// Mitsubishi GX Works2 project: PJT07_16_PLC(20220517_01)   PLC: Q03UDV

FUNCTION_BLOCK Alarm_FB
VAR_INPUT
  IB_Alarm : BOOL;  (* 入力@警報発生(0:-/1:発生) *)
END_VAR
VAR
  VT_AlarmDelayTimer : TIMER;  (* 内部@異常入力ﾃﾞｨﾚｲﾀｲﾏ *)
END_VAR
VAR_INPUT
  IW_DelayTimerVal : INT;  (* 入力@ﾃﾞｨﾚｲﾀｲﾏ値 *)
END_VAR
VAR_OUTPUT
  OB_AlarmHolding : BOOL;  (* 出力@ｱﾗｰﾑ自己保持(0:-/1:保持) *)
END_VAR
VAR_INPUT
  IB_AlarmResetPB : BOOL;  (* 入力@警報ﾘｾｯﾄPB(0:-/1:ﾘｾｯﾄ) *)
END_VAR
VAR
  VT_BuzzerStopTimer : TIMER;  (* 内部@ﾌﾞｻﾞｰｽﾄｯﾌﾟﾀｲﾏ *)
END_VAR
VAR_INPUT
  IW_BzStopTVal : INT;  (* 入力@ﾌﾞｻﾞｰｽﾄｯﾌﾟﾀｲﾏ値 *)
END_VAR
VAR
  VB_BuzzerStopFLG : BOOL;  (* 内部@ﾌﾞｻﾞｰｽﾄｯﾌﾟﾃﾞﾊﾞｲｽ(0:-/1:停止) *)
END_VAR
VAR_OUTPUT
  OB_DisplayFLG : BOOL;  (* 出力@ｱﾗｰﾑ表示ﾃﾞﾊﾞｲｽ(0:点滅/1:点灯) *)
END_VAR
VAR_INPUT
  IB_BuzzerStopPB : BOOL;  (* 入力@ﾌﾞｻﾞｰｽﾄｯﾌﾟPB(0:-/1:ｽﾄｯﾌﾟ) *)
END_VAR
VAR_OUTPUT
  OB_BuzzerFLG : BOOL;  (* 出力@ﾌﾞｻﾞｰﾌﾗｸﾞ *)
END_VAR
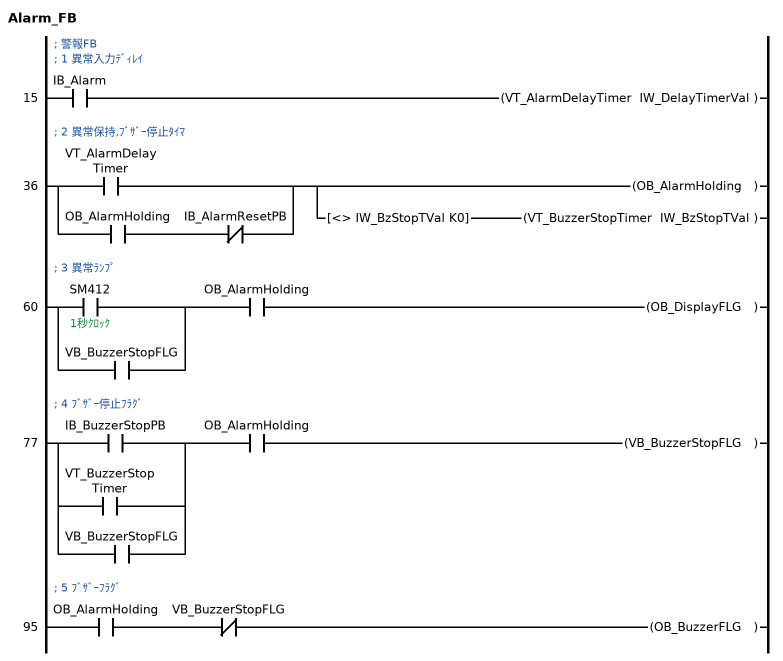
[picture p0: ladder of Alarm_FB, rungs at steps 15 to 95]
; 警報FB
; 1 異常入力ﾃﾞｨﾚｲ
15    LD      IB_Alarm
      OUT     VT_AlarmDelayTimer IW_DelayTimerVal
; 2 異常保持,ﾌﾞｻﾞｰ停止ﾀｲﾏ
36    LD      VT_AlarmDelayTimer
      LD      OB_AlarmHolding
      ANI     IB_AlarmResetPB
      ORB
      OUT     OB_AlarmHolding
      AND<>   IW_BzStopTVal K0
      OUT     VT_BuzzerStopTimer IW_BzStopTVal
; 3 異常ﾗﾝﾌﾟ
60    LD      SM412  ; 1秒ｸﾛｯｸ
      OR      VB_BuzzerStopFLG
      AND     OB_AlarmHolding
      OUT     OB_DisplayFLG
; 4 ﾌﾞｻﾞｰ停止ﾌﾗｸﾞ
77    LD      IB_BuzzerStopPB
      OR      VT_BuzzerStopTimer
      OR      VB_BuzzerStopFLG
      AND     OB_AlarmHolding
      OUT     VB_BuzzerStopFLG
; 5 ﾌﾞｻﾞｰﾌﾗｸﾞ
95    LD      OB_AlarmHolding
      ANI     VB_BuzzerStopFLG
      OUT     OB_BuzzerFLG
END_FUNCTION_BLOCK

PROGRAM 11_Alarm
VAR
  Alarm_FB_1 : Alarm_FB;
  Alarm_FB_2 : Alarm_FB;
END_VAR
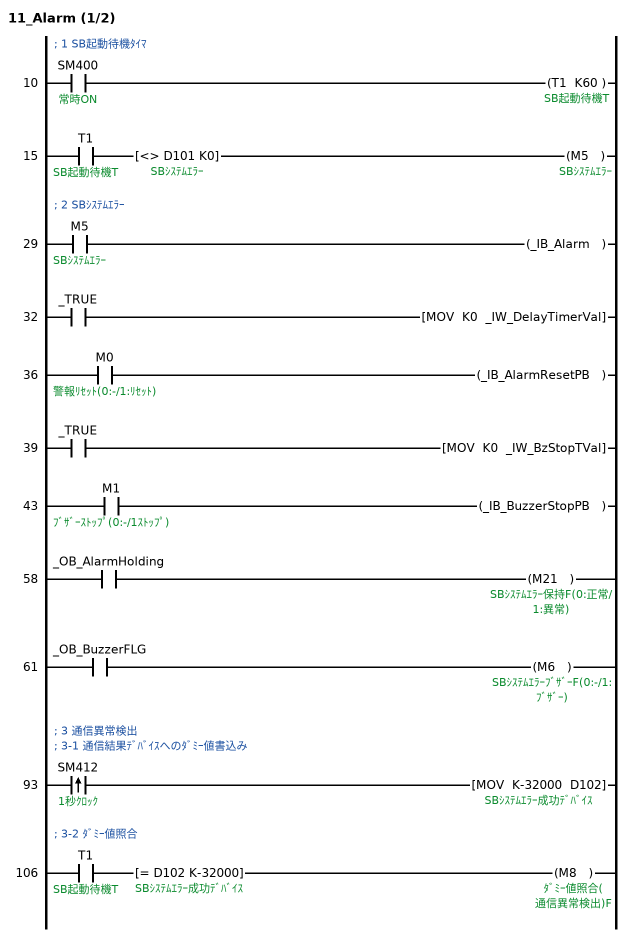
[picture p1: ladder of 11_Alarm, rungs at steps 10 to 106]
; 1 SB起動待機ﾀｲﾏ
10    LD      SM400  ; 常時ON
      OUT     T1 K60  ; SB起動待機T
15    LD      T1  ; SB起動待機T
      AND<>   D101 K0  ; SBｼｽﾃﾑｴﾗｰ
      OUT     M5  ; SBｼｽﾃﾑｴﾗｰ
; FB BLK START Alarm_FB(Alarm_FB_1)
; 2 SBｼｽﾃﾑｴﾗｰ
29    LD      M5  ; SBｼｽﾃﾑｴﾗｰ
      OUT     _IB_Alarm
32    LD      _TRUE
      MOV     K0 _IW_DelayTimerVal
36    LD      M0  ; 警報ﾘｾｯﾄ(0:-/1:ﾘｾｯﾄ)
      OUT     _IB_AlarmResetPB
39    LD      _TRUE
      MOV     K0 _IW_BzStopTVal
43    LD      M1  ; ﾌﾞｻﾞｰｽﾄｯﾌﾟ(0:-/1ｽﾄｯﾌﾟ)
      OUT     _IB_BuzzerStopPB
; FB START
; FB_NAME Alarm_FB
; INSTANCE_NAME Alarm_FB_1
; FB IN_B:IB_Alarm
; FB OUT_OB_AlarmHolding:B
; FB IN_W:IW_DelayTimerVal
; FB OUT_OB_DisplayFLG:B
; FB IN_B:IB_AlarmResetPB
; FB OUT_OB_BuzzerFLG:B
; FB IN_W:IW_BzStopTVal
; FB IN_B:IB_BuzzerStopPB
; FB END
58    LD      _OB_AlarmHolding
      OUT     M21  ; SBｼｽﾃﾑｴﾗｰ保持F(0:正常/1:異常)
61    LD      _OB_BuzzerFLG
      OUT     M6  ; SBｼｽﾃﾑｴﾗｰﾌﾞｻﾞｰF(0:-/1:ﾌﾞｻﾞｰ)
; FB BLK END
; 3 通信異常検出
; 3-1 通信結果ﾃﾞﾊﾞｲｽへのﾀﾞﾐｰ値書込み
93    LDP     SM412  ; 1秒ｸﾛｯｸ
      MOV     K-32000 D102  ; SBｼｽﾃﾑｴﾗｰ成功ﾃﾞﾊﾞｲｽ
; 3-2 ﾀﾞﾐｰ値照合
106   LD      T1  ; SB起動待機T
      AND=    D102 K-32000  ; SBｼｽﾃﾑｴﾗｰ成功ﾃﾞﾊﾞｲｽ
      OUT     M8  ; ﾀﾞﾐｰ値照合(通信異常検出)F
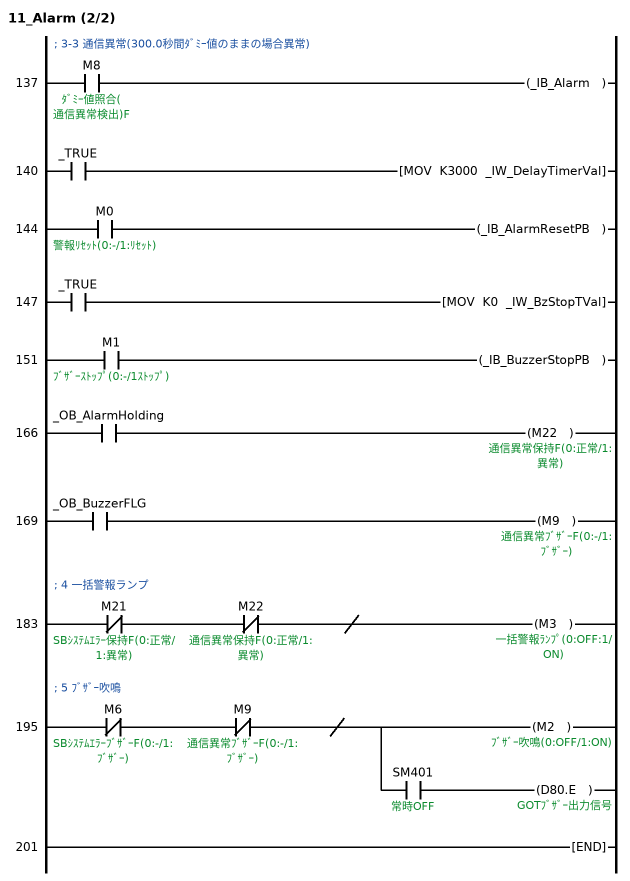
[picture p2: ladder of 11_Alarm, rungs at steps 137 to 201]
; FB BLK START Alarm_FB(Alarm_FB_2)
; 3-3 通信異常(300.0秒間ﾀﾞﾐｰ値のままの場合異常)
137   LD      M8  ; ﾀﾞﾐｰ値照合(通信異常検出)F
      OUT     _IB_Alarm
140   LD      _TRUE
      MOV     K3000 _IW_DelayTimerVal
144   LD      M0  ; 警報ﾘｾｯﾄ(0:-/1:ﾘｾｯﾄ)
      OUT     _IB_AlarmResetPB
147   LD      _TRUE
      MOV     K0 _IW_BzStopTVal
151   LD      M1  ; ﾌﾞｻﾞｰｽﾄｯﾌﾟ(0:-/1ｽﾄｯﾌﾟ)
      OUT     _IB_BuzzerStopPB
; FB START
; FB_NAME Alarm_FB
; INSTANCE_NAME Alarm_FB_2
; FB IN_B:IB_Alarm
; FB OUT_OB_AlarmHolding:B
; FB IN_W:IW_DelayTimerVal
; FB OUT_OB_DisplayFLG:B
; FB IN_B:IB_AlarmResetPB
; FB OUT_OB_BuzzerFLG:B
; FB IN_W:IW_BzStopTVal
; FB IN_B:IB_BuzzerStopPB
; FB END
166   LD      _OB_AlarmHolding
      OUT     M22  ; 通信異常保持F(0:正常/1:異常)
169   LD      _OB_BuzzerFLG
      OUT     M9  ; 通信異常ﾌﾞｻﾞｰF(0:-/1:ﾌﾞｻﾞｰ)
; FB BLK END
; 4 一括警報ランプ
183   LDI     M21  ; SBｼｽﾃﾑｴﾗｰ保持F(0:正常/1:異常)
      ANI     M22  ; 通信異常保持F(0:正常/1:異常)
      INV
      OUT     M3  ; 一括警報ﾗﾝﾌﾟ(0:OFF:1/ON)
; 5 ﾌﾞｻﾞｰ吹鳴
195   LDI     M6  ; SBｼｽﾃﾑｴﾗｰﾌﾞｻﾞｰF(0:-/1:ﾌﾞｻﾞｰ)
      ANI     M9  ; 通信異常ﾌﾞｻﾞｰF(0:-/1:ﾌﾞｻﾞｰ)
      INV
      OUT     M2  ; ﾌﾞｻﾞｰ吹鳴(0:OFF/1:ON)
      AND     SM401  ; 常時OFF
      OUT     D80.E  ; GOTﾌﾞｻﾞｰ出力信号
201   END
END_PROGRAM

PROGRAM 02_#2  // SB_Initial
VAR
  __IST_553ac48fffaf4984 : I+ST_553ac48fffaf4984;
END_VAR
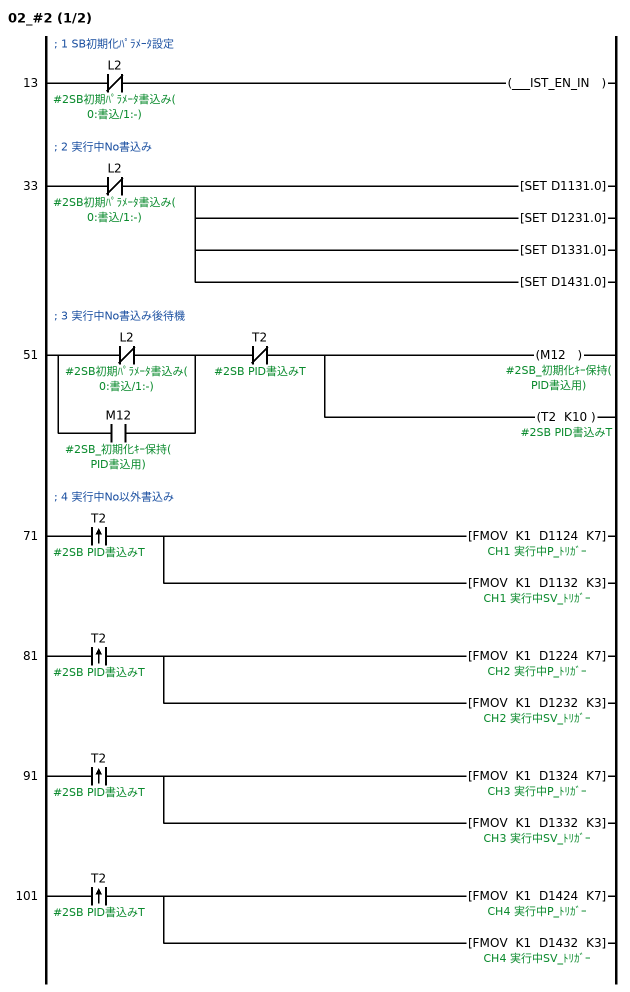
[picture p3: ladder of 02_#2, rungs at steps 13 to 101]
; FB BLK START I+ST_553ac48fffaf4984(__IST_553ac48fffaf4984)
; 1 SB初期化ﾊﾟﾗﾒｰﾀ設定
13    LDI     L2  ; #2SB初期ﾊﾟﾗﾒｰﾀ書込み(0:書込/1:-)
      OUT     ___IST_EN_IN
; FB START
; FB_NAME I+ST_553ac48fffaf4984
; INSTANCE_NAME __IST_553ac48fffaf4984
; FB IN_B:__IST_EN_IN
; FB OUT___IST_EN_OUT:B
; FB END
; FB BLK END
; 2 実行中No書込み
33    LDI     L2  ; #2SB初期ﾊﾟﾗﾒｰﾀ書込み(0:書込/1:-)
      SET     D1131.0
      SET     D1231.0
      SET     D1331.0
      SET     D1431.0
; 3 実行中No書込み後待機
51    LDI     L2  ; #2SB初期ﾊﾟﾗﾒｰﾀ書込み(0:書込/1:-)
      OR      M12  ; #2SB_初期化ｷｰ保持(PID書込用)
      ANI     T2  ; #2SB PID書込みT
      OUT     M12  ; #2SB_初期化ｷｰ保持(PID書込用)
      OUT     T2 K10  ; #2SB PID書込みT
; 4 実行中No以外書込み
71    LDP     T2  ; #2SB PID書込みT
      FMOV    K1 D1124 K7  ; CH1 実行中P_ﾄﾘｶﾞｰ
      FMOV    K1 D1132 K3  ; CH1 実行中SV_ﾄﾘｶﾞｰ
81    LDP     T2  ; #2SB PID書込みT
      FMOV    K1 D1224 K7  ; CH2 実行中P_ﾄﾘｶﾞｰ
      FMOV    K1 D1232 K3  ; CH2 実行中SV_ﾄﾘｶﾞｰ
91    LDP     T2  ; #2SB PID書込みT
      FMOV    K1 D1324 K7  ; CH3 実行中P_ﾄﾘｶﾞｰ
      FMOV    K1 D1332 K3  ; CH3 実行中SV_ﾄﾘｶﾞｰ
101   LDP     T2  ; #2SB PID書込みT
      FMOV    K1 D1424 K7  ; CH4 実行中P_ﾄﾘｶﾞｰ
      FMOV    K1 D1432 K3  ; CH4 実行中SV_ﾄﾘｶﾞｰ
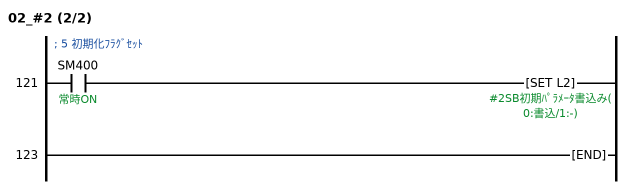
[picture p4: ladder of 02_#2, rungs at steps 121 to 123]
; 5 初期化ﾌﾗｸﾞｾｯﾄ
121   LD      SM400  ; 常時ON
      SET     L2  ; #2SB初期ﾊﾟﾗﾒｰﾀ書込み(0:書込/1:-)
123   END
END_PROGRAM

PROGRAM 22_#2  // SB100
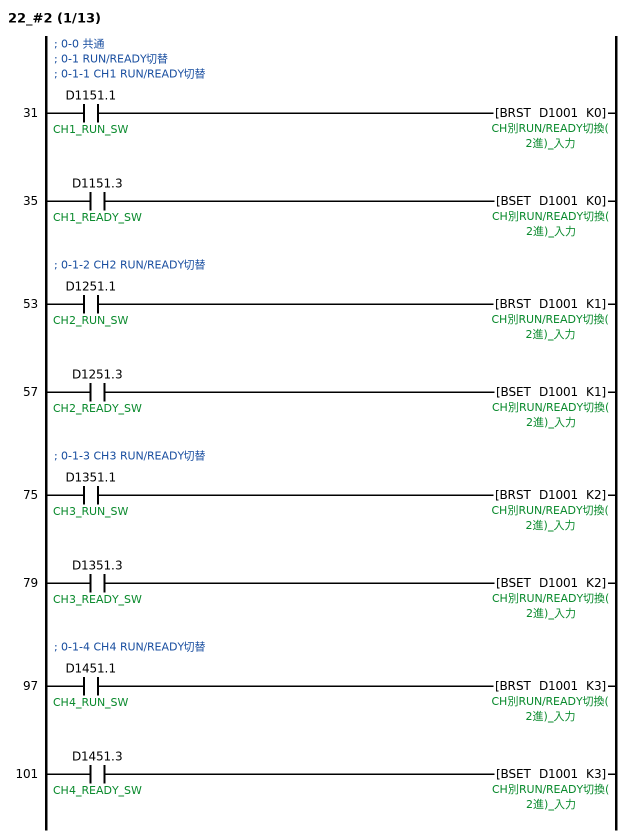
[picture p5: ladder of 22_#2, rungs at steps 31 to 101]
; 0-0 共通
; 0-1 RUN/READY切替
; 0-1-1 CH1 RUN/READY切替
31    LD      D1151.1  ; CH1_RUN_SW
      BRST    D1001 K0  ; CH別RUN/READY切換(2進)_入力
35    LD      D1151.3  ; CH1_READY_SW
      BSET    D1001 K0
; 0-1-2 CH2 RUN/READY切替
53    LD      D1251.1  ; CH2_RUN_SW
      BRST    D1001 K1
57    LD      D1251.3  ; CH2_READY_SW
      BSET    D1001 K1
; 0-1-3 CH3 RUN/READY切替
75    LD      D1351.1  ; CH3_RUN_SW
      BRST    D1001 K2
79    LD      D1351.3  ; CH3_READY_SW
      BSET    D1001 K2
; 0-1-4 CH4 RUN/READY切替
97    LD      D1451.1  ; CH4_RUN_SW
      BRST    D1001 K3
101   LD      D1451.3  ; CH4_READY_SW
      BSET    D1001 K3
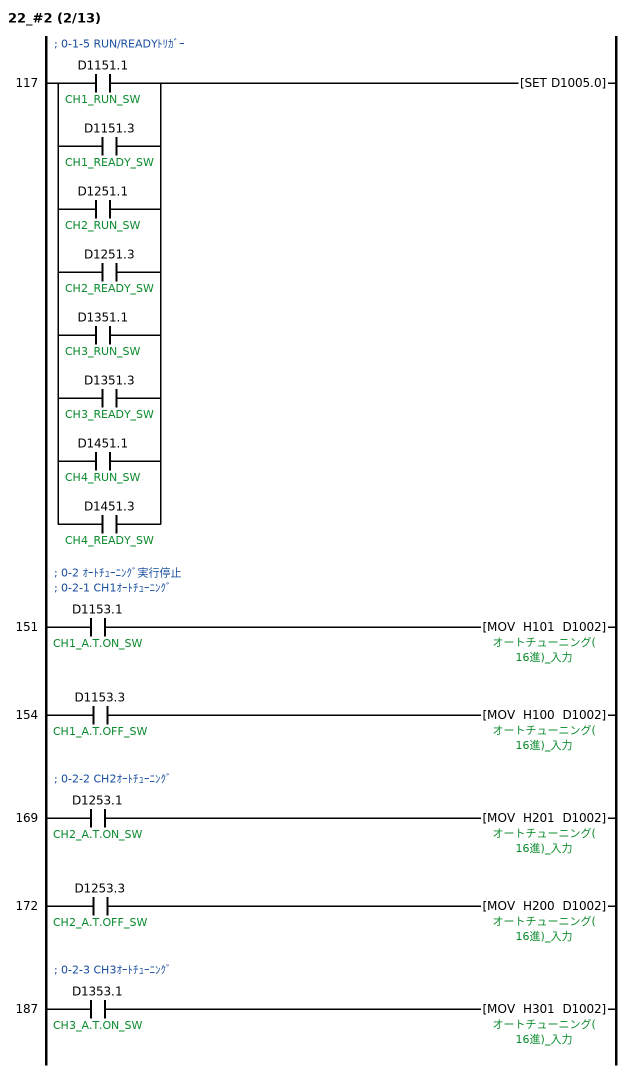
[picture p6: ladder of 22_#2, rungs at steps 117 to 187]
; 0-1-5 RUN/READYﾄﾘｶﾞｰ
117   LD      D1151.1  ; CH1_RUN_SW
      OR      D1151.3  ; CH1_READY_SW
      OR      D1251.1  ; CH2_RUN_SW
      OR      D1251.3  ; CH2_READY_SW
      OR      D1351.1  ; CH3_RUN_SW
      OR      D1351.3  ; CH3_READY_SW
      OR      D1451.1  ; CH4_RUN_SW
      OR      D1451.3  ; CH4_READY_SW
      SET     D1005.0
; 0-2 ｵｰﾄﾁｭｰﾆﾝｸﾞ実行停止
; 0-2-1 CH1ｵｰﾄﾁｭｰﾆﾝｸﾞ
151   LD      D1153.1  ; CH1_A.T.ON_SW
      MOV     H101 D1002  ; オートチューニング(16進)_入力
154   LD      D1153.3  ; CH1_A.T.OFF_SW
      MOV     H100 D1002
; 0-2-2 CH2ｵｰﾄﾁｭｰﾆﾝｸﾞ
169   LD      D1253.1  ; CH2_A.T.ON_SW
      MOV     H201 D1002
172   LD      D1253.3  ; CH2_A.T.OFF_SW
      MOV     H200 D1002
; 0-2-3 CH3ｵｰﾄﾁｭｰﾆﾝｸﾞ
187   LD      D1353.1  ; CH3_A.T.ON_SW
      MOV     H301 D1002
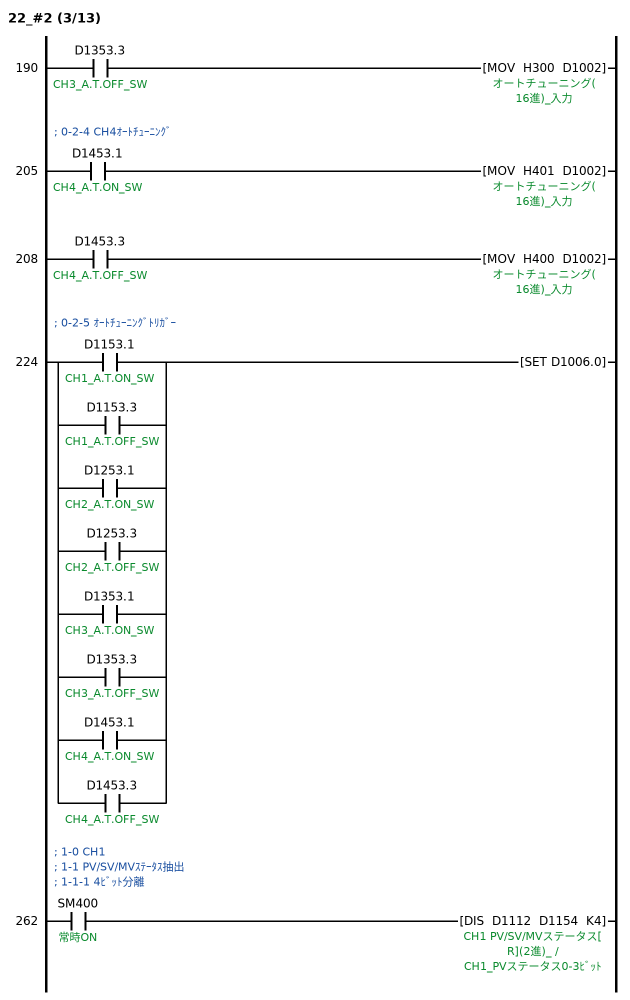
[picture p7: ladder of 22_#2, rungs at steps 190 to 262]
190   LD      D1353.3  ; CH3_A.T.OFF_SW
      MOV     H300 D1002
; 0-2-4 CH4ｵｰﾄﾁｭｰﾆﾝｸﾞ
205   LD      D1453.1  ; CH4_A.T.ON_SW
      MOV     H401 D1002
208   LD      D1453.3  ; CH4_A.T.OFF_SW
      MOV     H400 D1002
; 0-2-5 ｵｰﾄﾁｭｰﾆﾝｸﾞﾄﾘｶﾞｰ
224   LD      D1153.1  ; CH1_A.T.ON_SW
      OR      D1153.3  ; CH1_A.T.OFF_SW
      OR      D1253.1  ; CH2_A.T.ON_SW
      OR      D1253.3  ; CH2_A.T.OFF_SW
      OR      D1353.1  ; CH3_A.T.ON_SW
      OR      D1353.3  ; CH3_A.T.OFF_SW
      OR      D1453.1  ; CH4_A.T.ON_SW
      OR      D1453.3  ; CH4_A.T.OFF_SW
      SET     D1006.0
; 1-0 CH1
; 1-1 PV/SV/MVｽﾃｰﾀｽ抽出
; 1-1-1 4ﾋﾞｯﾄ分離
262   LD      SM400  ; 常時ON
      DIS     D1112 D1154 K4  ; CH1 PV/SV/MVステータス[R](2進)_ / CH1_PVステータス0-3ﾋﾞｯﾄ
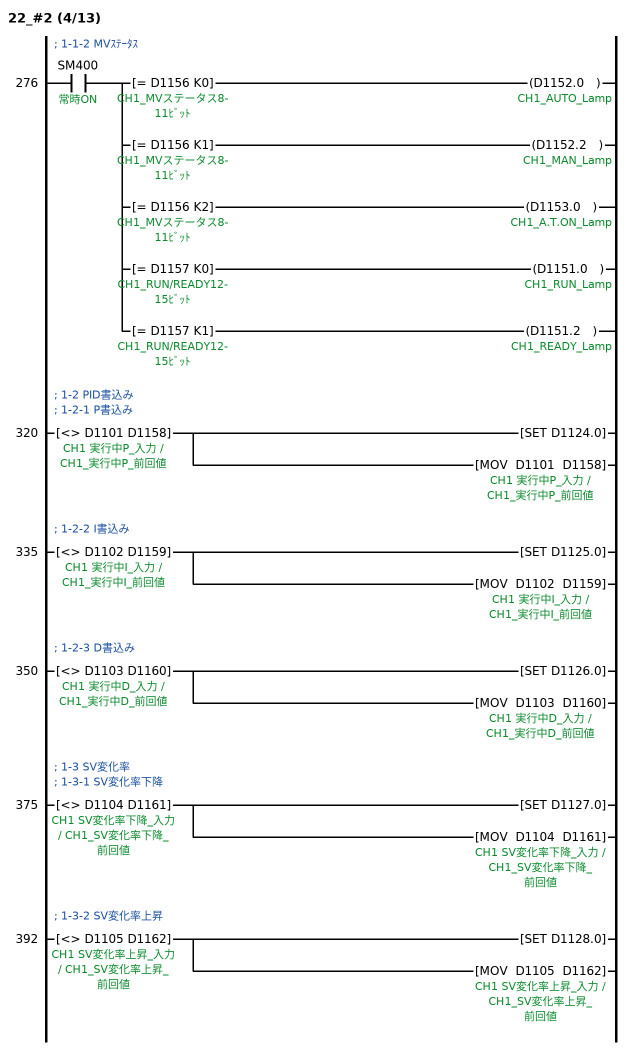
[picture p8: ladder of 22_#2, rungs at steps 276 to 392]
; 1-1-2 MVｽﾃｰﾀｽ
276   LD      SM400  ; 常時ON
      MPS
      AND=    D1156 K0  ; CH1_MVステータス8-11ﾋﾞｯﾄ
      OUT     D1152.0  ; CH1_AUTO_Lamp
      MRD
      AND=    D1156 K1  ; CH1_MVステータス8-11ﾋﾞｯﾄ
      OUT     D1152.2  ; CH1_MAN_Lamp
      MRD
      AND=    D1156 K2  ; CH1_MVステータス8-11ﾋﾞｯﾄ
      OUT     D1153.0  ; CH1_A.T.ON_Lamp
      MRD
      AND=    D1157 K0  ; CH1_RUN/READY12-15ﾋﾞｯﾄ
      OUT     D1151.0  ; CH1_RUN_Lamp
      MPP
      AND=    D1157 K1  ; CH1_RUN/READY12-15ﾋﾞｯﾄ
      OUT     D1151.2  ; CH1_READY_Lamp
; 1-2 PID書込み
; 1-2-1 P書込み
320   LD<>    D1101 D1158  ; CH1 実行中P_入力 / CH1_実行中P_前回値
      SET     D1124.0
      MOV     D1101 D1158
; 1-2-2 I書込み
335   LD<>    D1102 D1159  ; CH1 実行中I_入力 / CH1_実行中I_前回値
      SET     D1125.0
      MOV     D1102 D1159
; 1-2-3 D書込み
350   LD<>    D1103 D1160  ; CH1 実行中D_入力 / CH1_実行中D_前回値
      SET     D1126.0
      MOV     D1103 D1160
; 1-3 SV変化率
; 1-3-1 SV変化率下降
375   LD<>    D1104 D1161  ; CH1 SV変化率下降_入力 / CH1_SV変化率下降_前回値
      SET     D1127.0
      MOV     D1104 D1161
; 1-3-2 SV変化率上昇
392   LD<>    D1105 D1162  ; CH1 SV変化率上昇_入力 / CH1_SV変化率上昇_前回値
      SET     D1128.0
      MOV     D1105 D1162
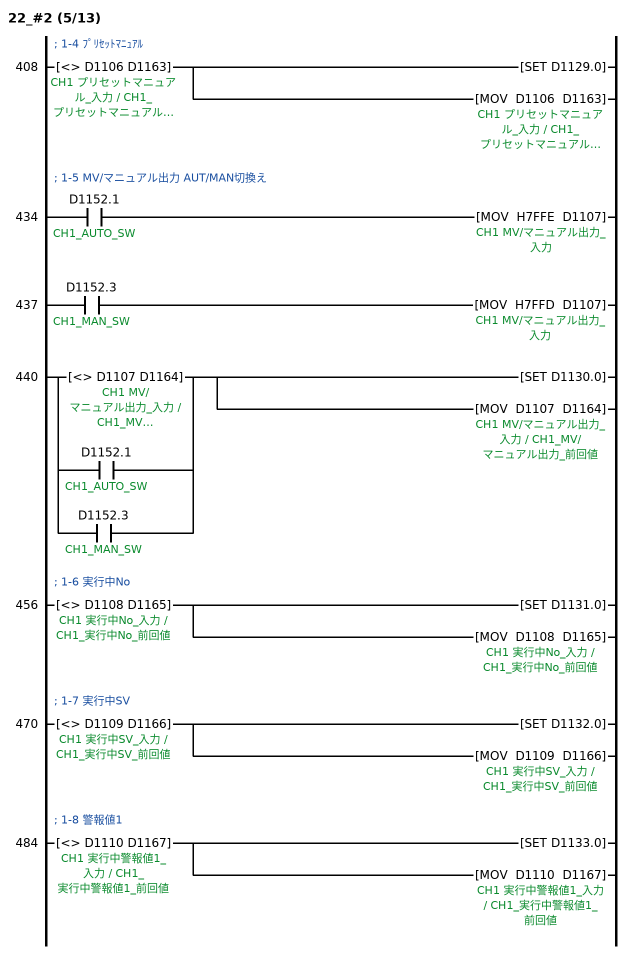
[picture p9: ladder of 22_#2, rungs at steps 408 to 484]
; 1-4 ﾌﾟﾘｾｯﾄﾏﾆｭｱﾙ
408   LD<>    D1106 D1163  ; CH1 プリセットマニュアル_入力 / CH1_プリセットマニュアル_前回値
      SET     D1129.0
      MOV     D1106 D1163
; 1-5 MV/マニュアル出力 AUT/MAN切換え
434   LD      D1152.1  ; CH1_AUTO_SW
      MOV     H7FFE D1107  ; CH1 MV/マニュアル出力_入力
437   LD      D1152.3  ; CH1_MAN_SW
      MOV     H7FFD D1107
440   LD<>    D1107 D1164  ; CH1 MV/マニュアル出力_入力 / CH1_MV/マニュアル出力_前回値
      OR      D1152.1  ; CH1_AUTO_SW
      OR      D1152.3  ; CH1_MAN_SW
      SET     D1130.0
      MOV     D1107 D1164
; 1-6 実行中No
456   LD<>    D1108 D1165  ; CH1 実行中No_入力 / CH1_実行中No_前回値
      SET     D1131.0
      MOV     D1108 D1165
; 1-7 実行中SV
470   LD<>    D1109 D1166  ; CH1 実行中SV_入力 / CH1_実行中SV_前回値
      SET     D1132.0
      MOV     D1109 D1166
; 1-8 警報値1
484   LD<>    D1110 D1167  ; CH1 実行中警報値1_入力 / CH1_実行中警報値1_前回値
      SET     D1133.0
      MOV     D1110 D1167
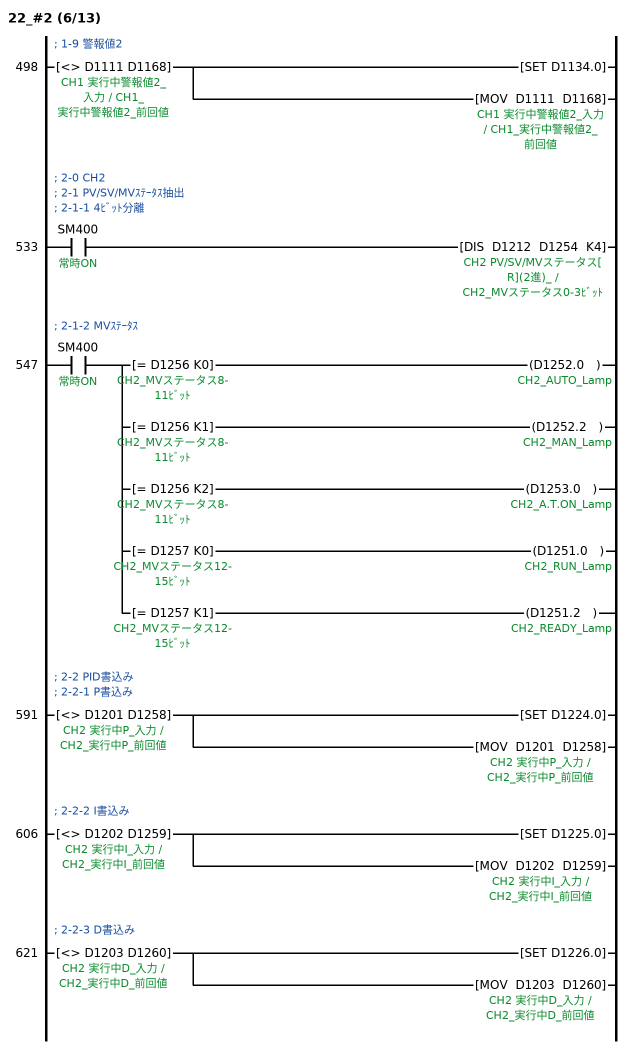
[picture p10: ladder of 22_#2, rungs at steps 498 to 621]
; 1-9 警報値2
498   LD<>    D1111 D1168  ; CH1 実行中警報値2_入力 / CH1_実行中警報値2_前回値
      SET     D1134.0
      MOV     D1111 D1168
; 2-0 CH2
; 2-1 PV/SV/MVｽﾃｰﾀｽ抽出
; 2-1-1 4ﾋﾞｯﾄ分離
533   LD      SM400  ; 常時ON
      DIS     D1212 D1254 K4  ; CH2 PV/SV/MVステータス[R](2進)_ / CH2_MVステータス0-3ﾋﾞｯﾄ
; 2-1-2 MVｽﾃｰﾀｽ
547   LD      SM400  ; 常時ON
      MPS
      AND=    D1256 K0  ; CH2_MVステータス8-11ﾋﾞｯﾄ
      OUT     D1252.0  ; CH2_AUTO_Lamp
      MRD
      AND=    D1256 K1  ; CH2_MVステータス8-11ﾋﾞｯﾄ
      OUT     D1252.2  ; CH2_MAN_Lamp
      MRD
      AND=    D1256 K2  ; CH2_MVステータス8-11ﾋﾞｯﾄ
      OUT     D1253.0  ; CH2_A.T.ON_Lamp
      MRD
      AND=    D1257 K0  ; CH2_MVステータス12-15ﾋﾞｯﾄ
      OUT     D1251.0  ; CH2_RUN_Lamp
      MPP
      AND=    D1257 K1  ; CH2_MVステータス12-15ﾋﾞｯﾄ
      OUT     D1251.2  ; CH2_READY_Lamp
; 2-2 PID書込み
; 2-2-1 P書込み
591   LD<>    D1201 D1258  ; CH2 実行中P_入力 / CH2_実行中P_前回値
      SET     D1224.0
      MOV     D1201 D1258
; 2-2-2 I書込み
606   LD<>    D1202 D1259  ; CH2 実行中I_入力 / CH2_実行中I_前回値
      SET     D1225.0
      MOV     D1202 D1259
; 2-2-3 D書込み
621   LD<>    D1203 D1260  ; CH2 実行中D_入力 / CH2_実行中D_前回値
      SET     D1226.0
      MOV     D1203 D1260
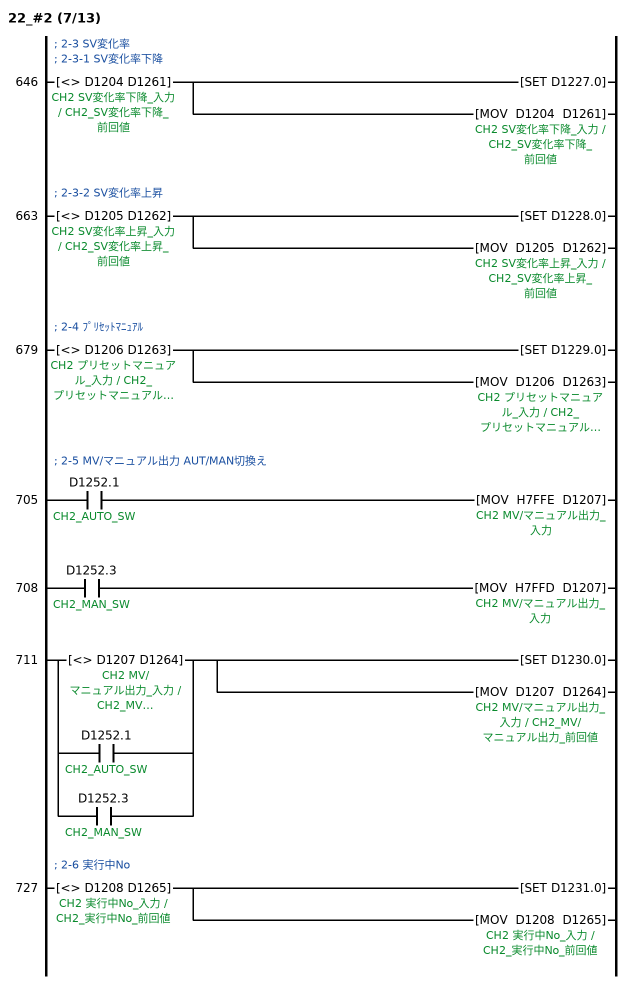
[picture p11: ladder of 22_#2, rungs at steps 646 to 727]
; 2-3 SV変化率
; 2-3-1 SV変化率下降
646   LD<>    D1204 D1261  ; CH2 SV変化率下降_入力 / CH2_SV変化率下降_前回値
      SET     D1227.0
      MOV     D1204 D1261
; 2-3-2 SV変化率上昇
663   LD<>    D1205 D1262  ; CH2 SV変化率上昇_入力 / CH2_SV変化率上昇_前回値
      SET     D1228.0
      MOV     D1205 D1262
; 2-4 ﾌﾟﾘｾｯﾄﾏﾆｭｱﾙ
679   LD<>    D1206 D1263  ; CH2 プリセットマニュアル_入力 / CH2_プリセットマニュアル_前回値
      SET     D1229.0
      MOV     D1206 D1263
; 2-5 MV/マニュアル出力 AUT/MAN切換え
705   LD      D1252.1  ; CH2_AUTO_SW
      MOV     H7FFE D1207  ; CH2 MV/マニュアル出力_入力
708   LD      D1252.3  ; CH2_MAN_SW
      MOV     H7FFD D1207
711   LD<>    D1207 D1264  ; CH2 MV/マニュアル出力_入力 / CH2_MV/マニュアル出力_前回値
      OR      D1252.1  ; CH2_AUTO_SW
      OR      D1252.3  ; CH2_MAN_SW
      SET     D1230.0
      MOV     D1207 D1264
; 2-6 実行中No
727   LD<>    D1208 D1265  ; CH2 実行中No_入力 / CH2_実行中No_前回値
      SET     D1231.0
      MOV     D1208 D1265
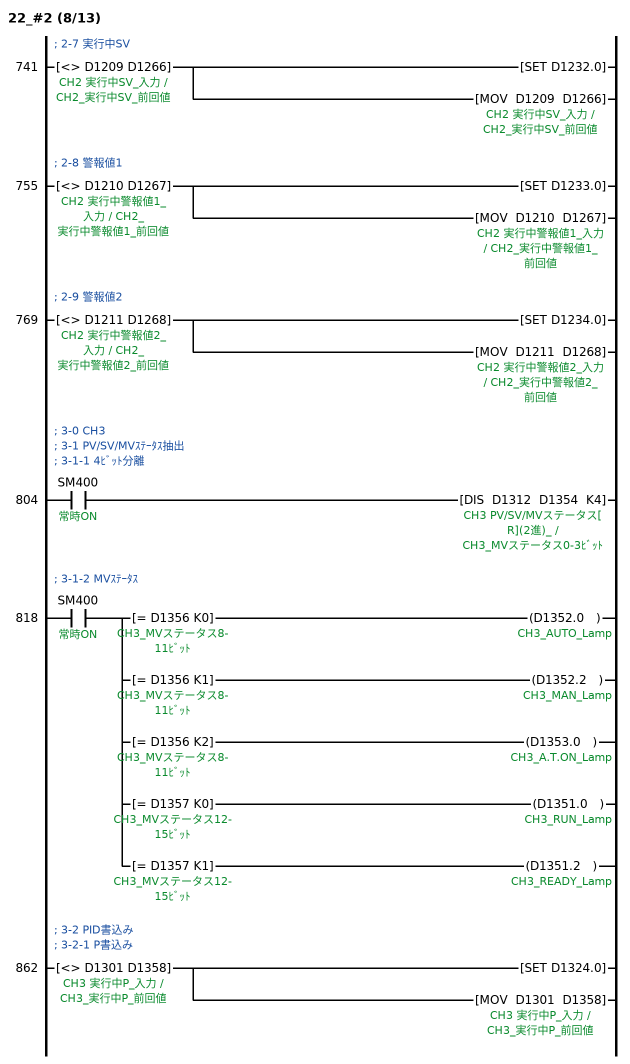
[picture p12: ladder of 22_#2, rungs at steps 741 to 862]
; 2-7 実行中SV
741   LD<>    D1209 D1266  ; CH2 実行中SV_入力 / CH2_実行中SV_前回値
      SET     D1232.0
      MOV     D1209 D1266
; 2-8 警報値1
755   LD<>    D1210 D1267  ; CH2 実行中警報値1_入力 / CH2_実行中警報値1_前回値
      SET     D1233.0
      MOV     D1210 D1267
; 2-9 警報値2
769   LD<>    D1211 D1268  ; CH2 実行中警報値2_入力 / CH2_実行中警報値2_前回値
      SET     D1234.0
      MOV     D1211 D1268
; 3-0 CH3
; 3-1 PV/SV/MVｽﾃｰﾀｽ抽出
; 3-1-1 4ﾋﾞｯﾄ分離
804   LD      SM400  ; 常時ON
      DIS     D1312 D1354 K4  ; CH3 PV/SV/MVステータス[R](2進)_ / CH3_MVステータス0-3ﾋﾞｯﾄ
; 3-1-2 MVｽﾃｰﾀｽ
818   LD      SM400  ; 常時ON
      MPS
      AND=    D1356 K0  ; CH3_MVステータス8-11ﾋﾞｯﾄ
      OUT     D1352.0  ; CH3_AUTO_Lamp
      MRD
      AND=    D1356 K1  ; CH3_MVステータス8-11ﾋﾞｯﾄ
      OUT     D1352.2  ; CH3_MAN_Lamp
      MRD
      AND=    D1356 K2  ; CH3_MVステータス8-11ﾋﾞｯﾄ
      OUT     D1353.0  ; CH3_A.T.ON_Lamp
      MRD
      AND=    D1357 K0  ; CH3_MVステータス12-15ﾋﾞｯﾄ
      OUT     D1351.0  ; CH3_RUN_Lamp
      MPP
      AND=    D1357 K1  ; CH3_MVステータス12-15ﾋﾞｯﾄ
      OUT     D1351.2  ; CH3_READY_Lamp
; 3-2 PID書込み
; 3-2-1 P書込み
862   LD<>    D1301 D1358  ; CH3 実行中P_入力 / CH3_実行中P_前回値
      SET     D1324.0
      MOV     D1301 D1358
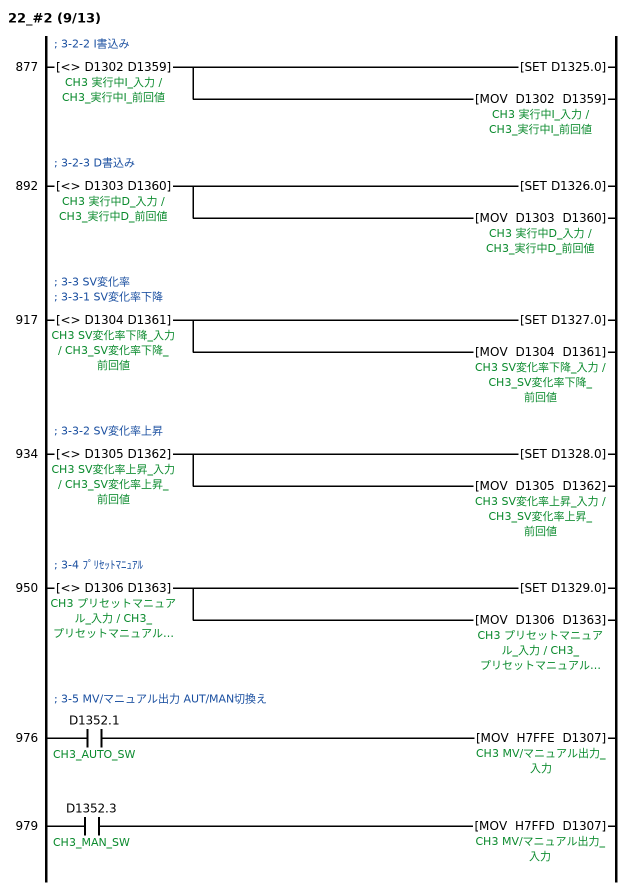
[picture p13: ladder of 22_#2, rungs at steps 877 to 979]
; 3-2-2 I書込み
877   LD<>    D1302 D1359  ; CH3 実行中I_入力 / CH3_実行中I_前回値
      SET     D1325.0
      MOV     D1302 D1359
; 3-2-3 D書込み
892   LD<>    D1303 D1360  ; CH3 実行中D_入力 / CH3_実行中D_前回値
      SET     D1326.0
      MOV     D1303 D1360
; 3-3 SV変化率
; 3-3-1 SV変化率下降
917   LD<>    D1304 D1361  ; CH3 SV変化率下降_入力 / CH3_SV変化率下降_前回値
      SET     D1327.0
      MOV     D1304 D1361
; 3-3-2 SV変化率上昇
934   LD<>    D1305 D1362  ; CH3 SV変化率上昇_入力 / CH3_SV変化率上昇_前回値
      SET     D1328.0
      MOV     D1305 D1362
; 3-4 ﾌﾟﾘｾｯﾄﾏﾆｭｱﾙ
950   LD<>    D1306 D1363  ; CH3 プリセットマニュアル_入力 / CH3_プリセットマニュアル_前回値
      SET     D1329.0
      MOV     D1306 D1363
; 3-5 MV/マニュアル出力 AUT/MAN切換え
976   LD      D1352.1  ; CH3_AUTO_SW
      MOV     H7FFE D1307  ; CH3 MV/マニュアル出力_入力
979   LD      D1352.3  ; CH3_MAN_SW
      MOV     H7FFD D1307
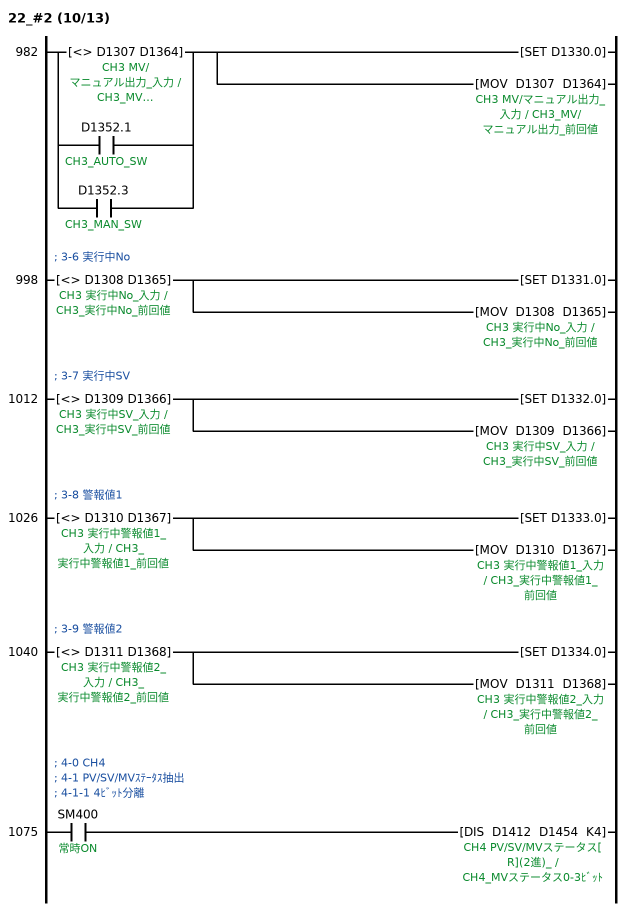
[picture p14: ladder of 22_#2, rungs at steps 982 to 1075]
982   LD<>    D1307 D1364  ; CH3 MV/マニュアル出力_入力 / CH3_MV/マニュアル出力_前回値
      OR      D1352.1  ; CH3_AUTO_SW
      OR      D1352.3  ; CH3_MAN_SW
      SET     D1330.0
      MOV     D1307 D1364
; 3-6 実行中No
998   LD<>    D1308 D1365  ; CH3 実行中No_入力 / CH3_実行中No_前回値
      SET     D1331.0
      MOV     D1308 D1365
; 3-7 実行中SV
1012  LD<>    D1309 D1366  ; CH3 実行中SV_入力 / CH3_実行中SV_前回値
      SET     D1332.0
      MOV     D1309 D1366
; 3-8 警報値1
1026  LD<>    D1310 D1367  ; CH3 実行中警報値1_入力 / CH3_実行中警報値1_前回値
      SET     D1333.0
      MOV     D1310 D1367
; 3-9 警報値2
1040  LD<>    D1311 D1368  ; CH3 実行中警報値2_入力 / CH3_実行中警報値2_前回値
      SET     D1334.0
      MOV     D1311 D1368
; 4-0 CH4
; 4-1 PV/SV/MVｽﾃｰﾀｽ抽出
; 4-1-1 4ﾋﾞｯﾄ分離
1075  LD      SM400  ; 常時ON
      DIS     D1412 D1454 K4  ; CH4 PV/SV/MVステータス[R](2進)_ / CH4_MVステータス0-3ﾋﾞｯﾄ
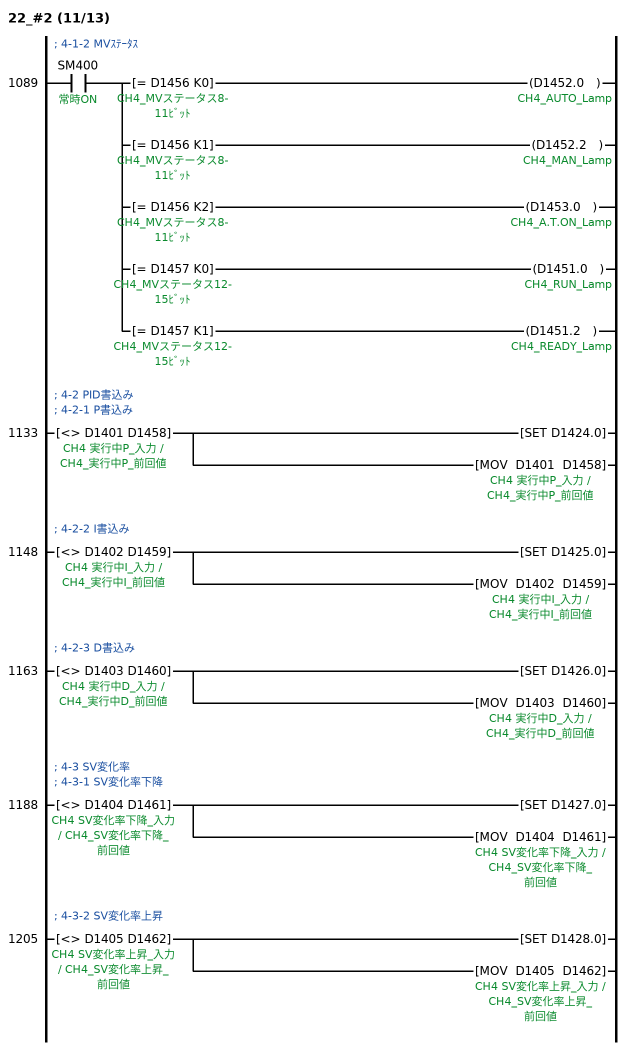
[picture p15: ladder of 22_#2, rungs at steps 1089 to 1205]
; 4-1-2 MVｽﾃｰﾀｽ
1089  LD      SM400  ; 常時ON
      MPS
      AND=    D1456 K0  ; CH4_MVステータス8-11ﾋﾞｯﾄ
      OUT     D1452.0  ; CH4_AUTO_Lamp
      MRD
      AND=    D1456 K1  ; CH4_MVステータス8-11ﾋﾞｯﾄ
      OUT     D1452.2  ; CH4_MAN_Lamp
      MRD
      AND=    D1456 K2  ; CH4_MVステータス8-11ﾋﾞｯﾄ
      OUT     D1453.0  ; CH4_A.T.ON_Lamp
      MRD
      AND=    D1457 K0  ; CH4_MVステータス12-15ﾋﾞｯﾄ
      OUT     D1451.0  ; CH4_RUN_Lamp
      MPP
      AND=    D1457 K1  ; CH4_MVステータス12-15ﾋﾞｯﾄ
      OUT     D1451.2  ; CH4_READY_Lamp
; 4-2 PID書込み
; 4-2-1 P書込み
1133  LD<>    D1401 D1458  ; CH4 実行中P_入力 / CH4_実行中P_前回値
      SET     D1424.0
      MOV     D1401 D1458
; 4-2-2 I書込み
1148  LD<>    D1402 D1459  ; CH4 実行中I_入力 / CH4_実行中I_前回値
      SET     D1425.0
      MOV     D1402 D1459
; 4-2-3 D書込み
1163  LD<>    D1403 D1460  ; CH4 実行中D_入力 / CH4_実行中D_前回値
      SET     D1426.0
      MOV     D1403 D1460
; 4-3 SV変化率
; 4-3-1 SV変化率下降
1188  LD<>    D1404 D1461  ; CH4 SV変化率下降_入力 / CH4_SV変化率下降_前回値
      SET     D1427.0
      MOV     D1404 D1461
; 4-3-2 SV変化率上昇
1205  LD<>    D1405 D1462  ; CH4 SV変化率上昇_入力 / CH4_SV変化率上昇_前回値
      SET     D1428.0
      MOV     D1405 D1462
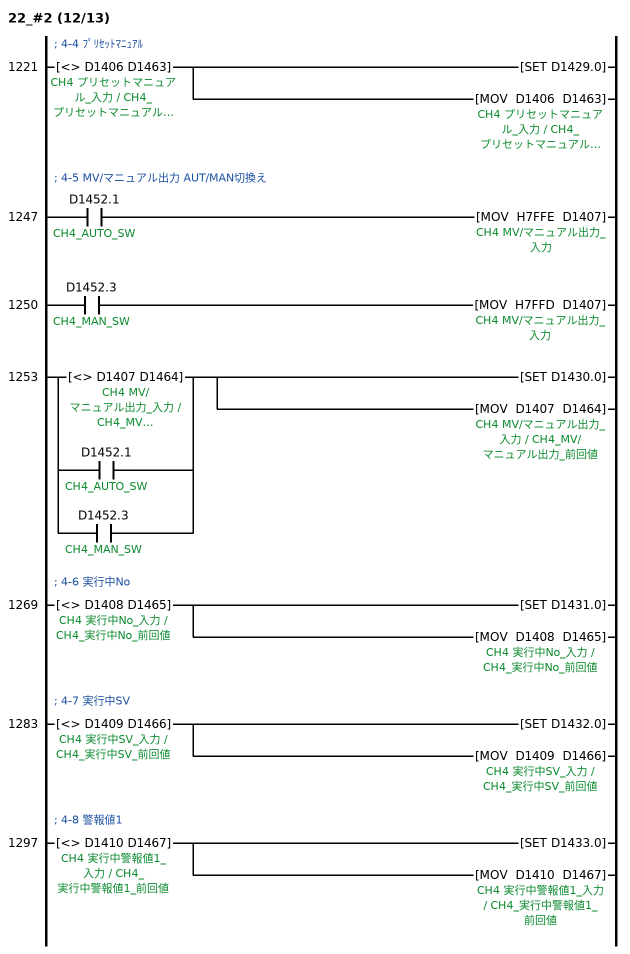
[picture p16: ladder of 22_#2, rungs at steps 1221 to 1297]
; 4-4 ﾌﾟﾘｾｯﾄﾏﾆｭｱﾙ
1221  LD<>    D1406 D1463  ; CH4 プリセットマニュアル_入力 / CH4_プリセットマニュアル_前回値
      SET     D1429.0
      MOV     D1406 D1463
; 4-5 MV/マニュアル出力 AUT/MAN切換え
1247  LD      D1452.1  ; CH4_AUTO_SW
      MOV     H7FFE D1407  ; CH4 MV/マニュアル出力_入力
1250  LD      D1452.3  ; CH4_MAN_SW
      MOV     H7FFD D1407
1253  LD<>    D1407 D1464  ; CH4 MV/マニュアル出力_入力 / CH4_MV/マニュアル出力_前回値
      OR      D1452.1  ; CH4_AUTO_SW
      OR      D1452.3  ; CH4_MAN_SW
      SET     D1430.0
      MOV     D1407 D1464
; 4-6 実行中No
1269  LD<>    D1408 D1465  ; CH4 実行中No_入力 / CH4_実行中No_前回値
      SET     D1431.0
      MOV     D1408 D1465
; 4-7 実行中SV
1283  LD<>    D1409 D1466  ; CH4 実行中SV_入力 / CH4_実行中SV_前回値
      SET     D1432.0
      MOV     D1409 D1466
; 4-8 警報値1
1297  LD<>    D1410 D1467  ; CH4 実行中警報値1_入力 / CH4_実行中警報値1_前回値
      SET     D1433.0
      MOV     D1410 D1467
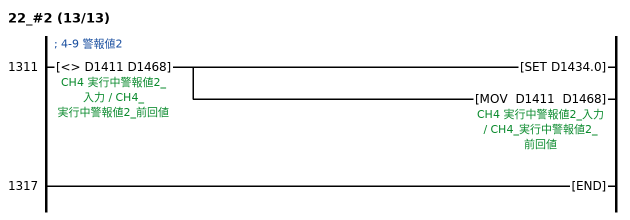
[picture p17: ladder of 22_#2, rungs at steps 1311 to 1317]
; 4-9 警報値2
1311  LD<>    D1411 D1468  ; CH4 実行中警報値2_入力 / CH4_実行中警報値2_前回値
      SET     D1434.0
      MOV     D1411 D1468
1317  END
END_PROGRAM

FUNCTION_BLOCK I+ST_553ac48fffaf4984
VAR_INPUT
  __IST_EN_IN : BOOL;
END_VAR
VAR_OUTPUT
  __IST_EN_OUT : BOOL;
END_VAR
(* IST HEADER START *)
IF NOT __IST_EN_IN THEN __IST_EN_OUT:=FALSE; RETURN; END_IF;
(* VERSION=1:TYPE=STB *)
(* IST HEADER END *)
D1101:=50;		(*CH1 実行中P*)
D1102:=60;		(*CH1 実行中I*)
D1103:=30;		(*CH1 実行中D*)
D1104:=0;		(*CH1 SV変化率下降*)
D1105:=0;		(*CH1 SV変化率上昇*)
D1106:=0;		(*CH1 プリセットマニュアル*)
D1108:=1;		(*CH1 実行中No*)
D1109:=234;		(*CH1 実行中SV*)
D1110:=30000;	(*CH1 実行中警報値1*)
D1111:=-30000;	(*CH1 実行中警報値2*)
D1201:=50;		(*CH2 実行中P*)
D1202:=60;		(*CH2 実行中I*)
D1203:=30;		(*CH2 実行中D*)
D1204:=0;		(*CH2 SV変化率下降*)
D1205:=0;		(*CH2 SV変化率上昇*)
D1206:=0;		(*CH2 プリセットマニュアル*)
D1208:=1;		(*CH2 実行中No*)
D1209:=234;		(*CH2 実行中SV*)
D1210:=30000;	(*CH2 実行中警報値1*)
D1211:=-30000;	(*CH2 実行中警報値2*)
D1301:=50;		(*CH3 実行中P*)
D1302:=60;		(*CH3 実行中I*)
D1303:=30;		(*CH3 実行中D*)
D1304:=0;		(*CH3 SV変化率下降*)
D1305:=0;		(*CH3 SV変化率上昇*)
D1306:=0;		(*CH3 プリセットマニュアル*)
D1308:=1;		(*CH3 実行中No*)
D1309:=234;		(*CH3 実行中SV*)
D1310:=30000;	(*CH3 実行中警報値1*)
D1311:=-30000;	(*CH3 実行中警報値2*)
D1401:=50;		(*CH4 実行中P*)
D1402:=60;		(*CH4 実行中I*)
D1403:=30;		(*CH4 実行中D*)
D1404:=0;		(*CH4 SV変化率下降*)
D1405:=0;		(*CH4 SV変化率上昇*)
D1406:=0;		(*CH4 プリセットマニュアル*)
D1408:=1;		(*CH4 実行中No*)
D1409:=234;		(*CH4 実行中SV*)
D1410:=30000;	(*CH4 実行中警報値1*)
D1411:=-30000;(*CH4 実行中警報値2*)
END_FUNCTION_BLOCK

PROGRAM 23_#3  // SB100
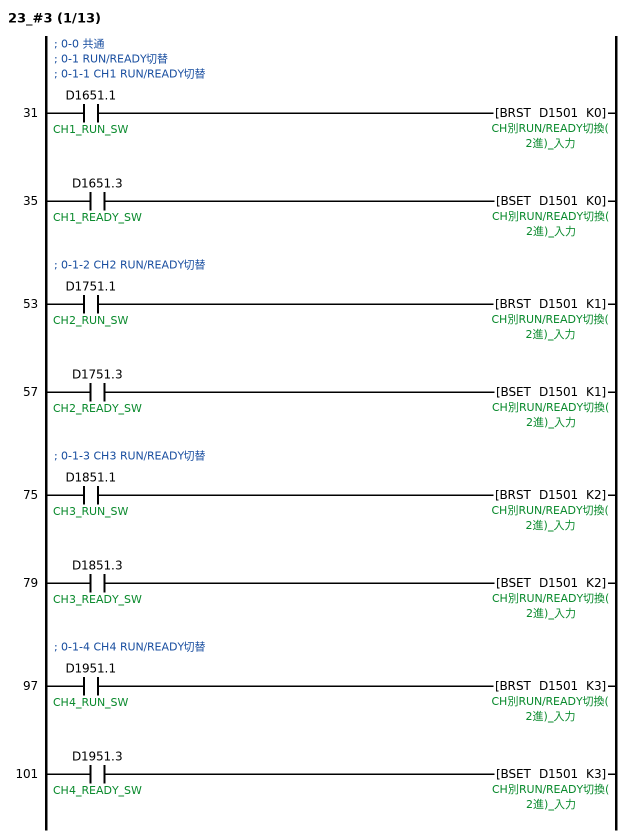
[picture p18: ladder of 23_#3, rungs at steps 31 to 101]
; 0-0 共通
; 0-1 RUN/READY切替
; 0-1-1 CH1 RUN/READY切替
31    LD      D1651.1  ; CH1_RUN_SW
      BRST    D1501 K0  ; CH別RUN/READY切換(2進)_入力
35    LD      D1651.3  ; CH1_READY_SW
      BSET    D1501 K0
; 0-1-2 CH2 RUN/READY切替
53    LD      D1751.1  ; CH2_RUN_SW
      BRST    D1501 K1
57    LD      D1751.3  ; CH2_READY_SW
      BSET    D1501 K1
; 0-1-3 CH3 RUN/READY切替
75    LD      D1851.1  ; CH3_RUN_SW
      BRST    D1501 K2
79    LD      D1851.3  ; CH3_READY_SW
      BSET    D1501 K2
; 0-1-4 CH4 RUN/READY切替
97    LD      D1951.1  ; CH4_RUN_SW
      BRST    D1501 K3
101   LD      D1951.3  ; CH4_READY_SW
      BSET    D1501 K3
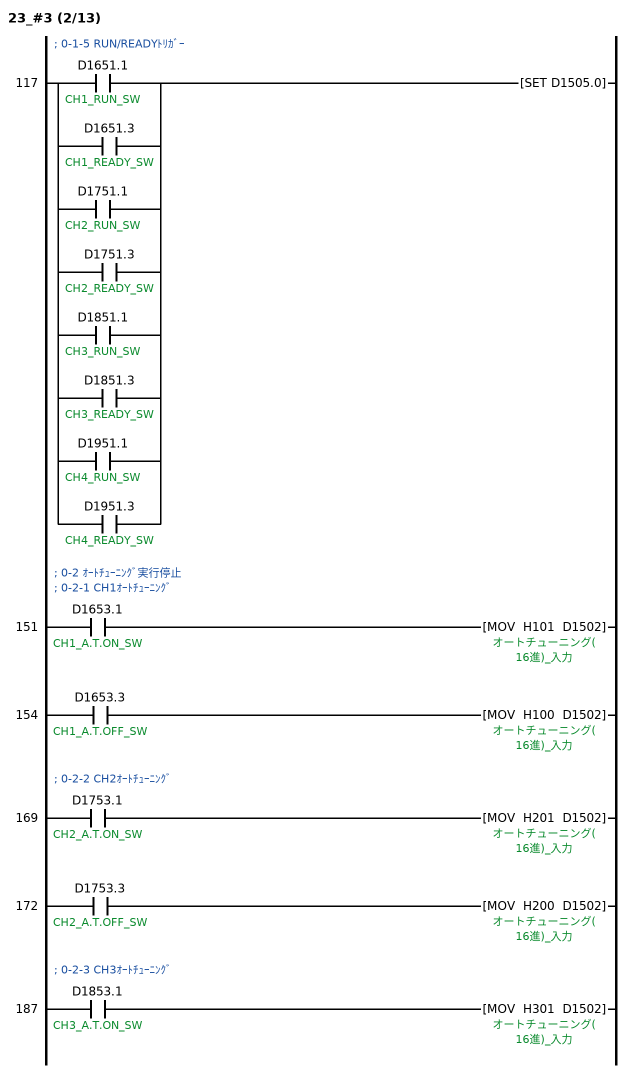
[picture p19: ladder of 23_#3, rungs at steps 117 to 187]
; 0-1-5 RUN/READYﾄﾘｶﾞｰ
117   LD      D1651.1  ; CH1_RUN_SW
      OR      D1651.3  ; CH1_READY_SW
      OR      D1751.1  ; CH2_RUN_SW
      OR      D1751.3  ; CH2_READY_SW
      OR      D1851.1  ; CH3_RUN_SW
      OR      D1851.3  ; CH3_READY_SW
      OR      D1951.1  ; CH4_RUN_SW
      OR      D1951.3  ; CH4_READY_SW
      SET     D1505.0
; 0-2 ｵｰﾄﾁｭｰﾆﾝｸﾞ実行停止
; 0-2-1 CH1ｵｰﾄﾁｭｰﾆﾝｸﾞ
151   LD      D1653.1  ; CH1_A.T.ON_SW
      MOV     H101 D1502  ; オートチューニング(16進)_入力
154   LD      D1653.3  ; CH1_A.T.OFF_SW
      MOV     H100 D1502
; 0-2-2 CH2ｵｰﾄﾁｭｰﾆﾝｸﾞ
169   LD      D1753.1  ; CH2_A.T.ON_SW
      MOV     H201 D1502
172   LD      D1753.3  ; CH2_A.T.OFF_SW
      MOV     H200 D1502
; 0-2-3 CH3ｵｰﾄﾁｭｰﾆﾝｸﾞ
187   LD      D1853.1  ; CH3_A.T.ON_SW
      MOV     H301 D1502
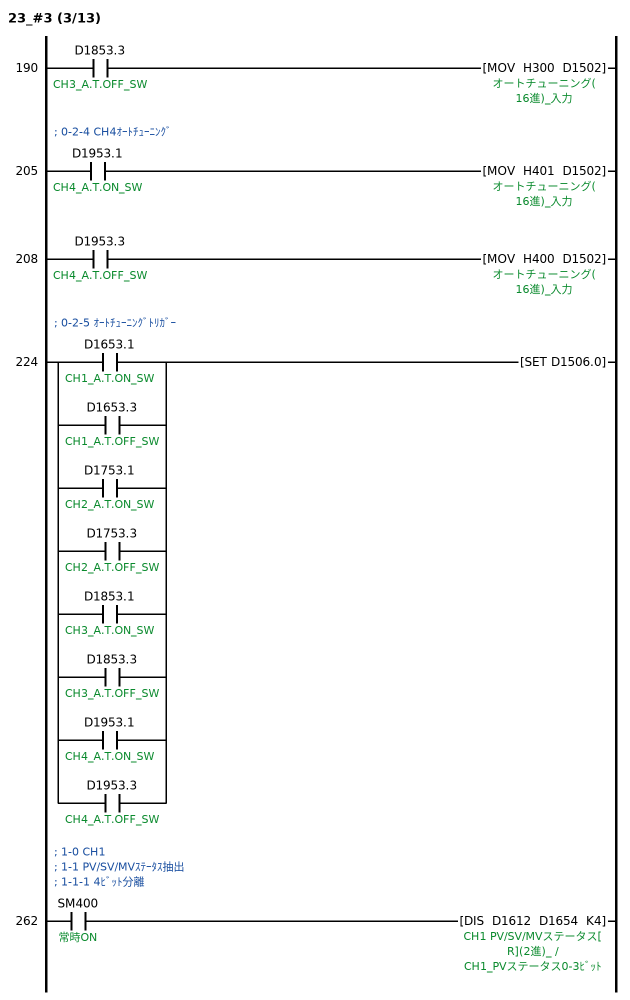
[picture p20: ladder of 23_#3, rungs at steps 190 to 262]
190   LD      D1853.3  ; CH3_A.T.OFF_SW
      MOV     H300 D1502
; 0-2-4 CH4ｵｰﾄﾁｭｰﾆﾝｸﾞ
205   LD      D1953.1  ; CH4_A.T.ON_SW
      MOV     H401 D1502
208   LD      D1953.3  ; CH4_A.T.OFF_SW
      MOV     H400 D1502
; 0-2-5 ｵｰﾄﾁｭｰﾆﾝｸﾞﾄﾘｶﾞｰ
224   LD      D1653.1  ; CH1_A.T.ON_SW
      OR      D1653.3  ; CH1_A.T.OFF_SW
      OR      D1753.1  ; CH2_A.T.ON_SW
      OR      D1753.3  ; CH2_A.T.OFF_SW
      OR      D1853.1  ; CH3_A.T.ON_SW
      OR      D1853.3  ; CH3_A.T.OFF_SW
      OR      D1953.1  ; CH4_A.T.ON_SW
      OR      D1953.3  ; CH4_A.T.OFF_SW
      SET     D1506.0
; 1-0 CH1
; 1-1 PV/SV/MVｽﾃｰﾀｽ抽出
; 1-1-1 4ﾋﾞｯﾄ分離
262   LD      SM400  ; 常時ON
      DIS     D1612 D1654 K4  ; CH1 PV/SV/MVステータス[R](2進)_ / CH1_PVステータス0-3ﾋﾞｯﾄ
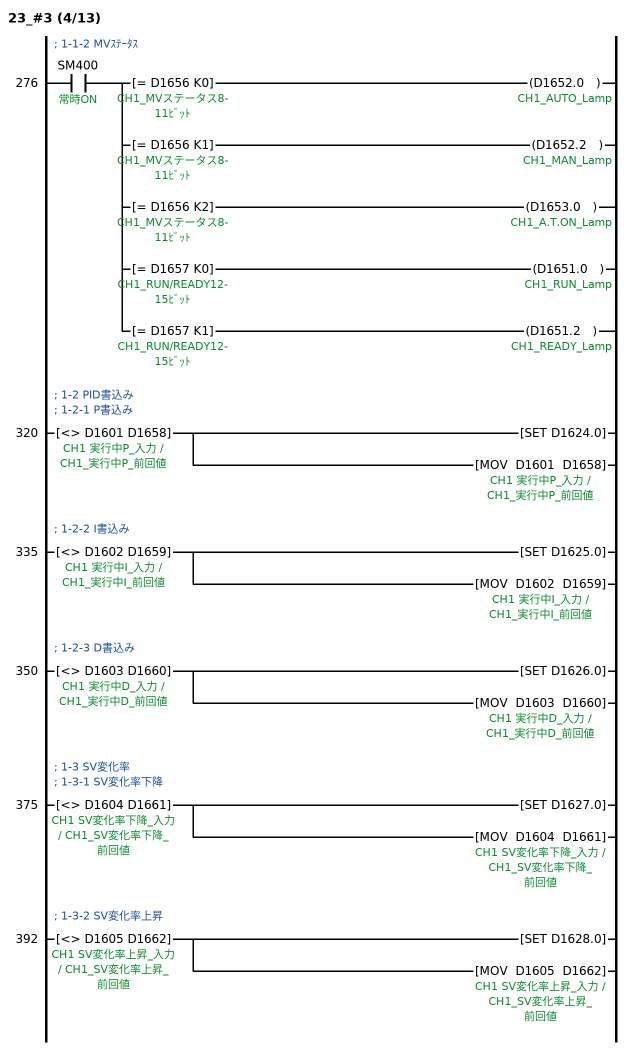
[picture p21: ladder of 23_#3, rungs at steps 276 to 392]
; 1-1-2 MVｽﾃｰﾀｽ
276   LD      SM400  ; 常時ON
      MPS
      AND=    D1656 K0  ; CH1_MVステータス8-11ﾋﾞｯﾄ
      OUT     D1652.0  ; CH1_AUTO_Lamp
      MRD
      AND=    D1656 K1  ; CH1_MVステータス8-11ﾋﾞｯﾄ
      OUT     D1652.2  ; CH1_MAN_Lamp
      MRD
      AND=    D1656 K2  ; CH1_MVステータス8-11ﾋﾞｯﾄ
      OUT     D1653.0  ; CH1_A.T.ON_Lamp
      MRD
      AND=    D1657 K0  ; CH1_RUN/READY12-15ﾋﾞｯﾄ
      OUT     D1651.0  ; CH1_RUN_Lamp
      MPP
      AND=    D1657 K1  ; CH1_RUN/READY12-15ﾋﾞｯﾄ
      OUT     D1651.2  ; CH1_READY_Lamp
; 1-2 PID書込み
; 1-2-1 P書込み
320   LD<>    D1601 D1658  ; CH1 実行中P_入力 / CH1_実行中P_前回値
      SET     D1624.0
      MOV     D1601 D1658
; 1-2-2 I書込み
335   LD<>    D1602 D1659  ; CH1 実行中I_入力 / CH1_実行中I_前回値
      SET     D1625.0
      MOV     D1602 D1659
; 1-2-3 D書込み
350   LD<>    D1603 D1660  ; CH1 実行中D_入力 / CH1_実行中D_前回値
      SET     D1626.0
      MOV     D1603 D1660
; 1-3 SV変化率
; 1-3-1 SV変化率下降
375   LD<>    D1604 D1661  ; CH1 SV変化率下降_入力 / CH1_SV変化率下降_前回値
      SET     D1627.0
      MOV     D1604 D1661
; 1-3-2 SV変化率上昇
392   LD<>    D1605 D1662  ; CH1 SV変化率上昇_入力 / CH1_SV変化率上昇_前回値
      SET     D1628.0
      MOV     D1605 D1662
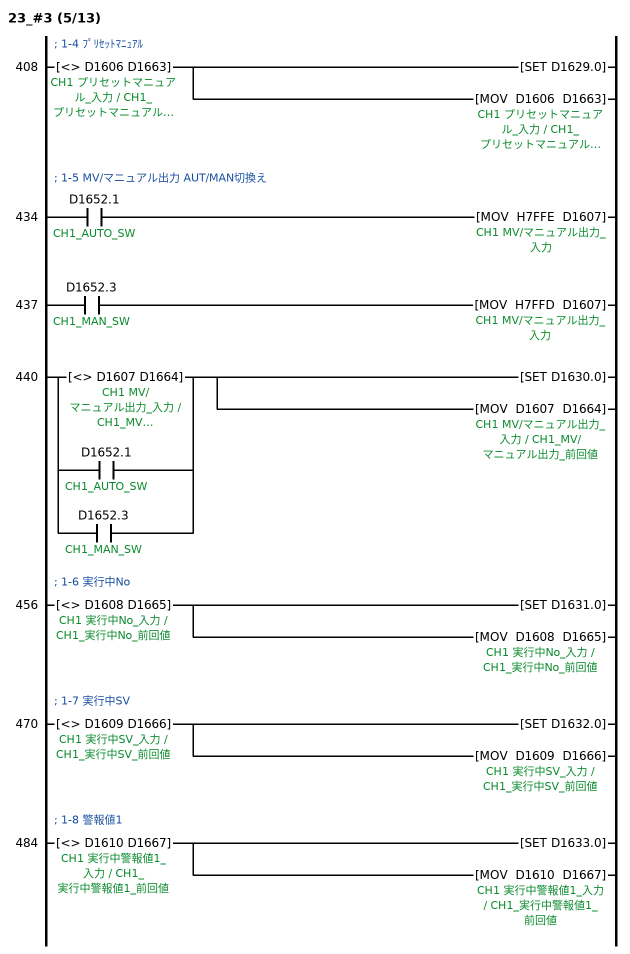
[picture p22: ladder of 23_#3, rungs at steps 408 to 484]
; 1-4 ﾌﾟﾘｾｯﾄﾏﾆｭｱﾙ
408   LD<>    D1606 D1663  ; CH1 プリセットマニュアル_入力 / CH1_プリセットマニュアル_前回値
      SET     D1629.0
      MOV     D1606 D1663
; 1-5 MV/マニュアル出力 AUT/MAN切換え
434   LD      D1652.1  ; CH1_AUTO_SW
      MOV     H7FFE D1607  ; CH1 MV/マニュアル出力_入力
437   LD      D1652.3  ; CH1_MAN_SW
      MOV     H7FFD D1607
440   LD<>    D1607 D1664  ; CH1 MV/マニュアル出力_入力 / CH1_MV/マニュアル出力_前回値
      OR      D1652.1  ; CH1_AUTO_SW
      OR      D1652.3  ; CH1_MAN_SW
      SET     D1630.0
      MOV     D1607 D1664
; 1-6 実行中No
456   LD<>    D1608 D1665  ; CH1 実行中No_入力 / CH1_実行中No_前回値
      SET     D1631.0
      MOV     D1608 D1665
; 1-7 実行中SV
470   LD<>    D1609 D1666  ; CH1 実行中SV_入力 / CH1_実行中SV_前回値
      SET     D1632.0
      MOV     D1609 D1666
; 1-8 警報値1
484   LD<>    D1610 D1667  ; CH1 実行中警報値1_入力 / CH1_実行中警報値1_前回値
      SET     D1633.0
      MOV     D1610 D1667
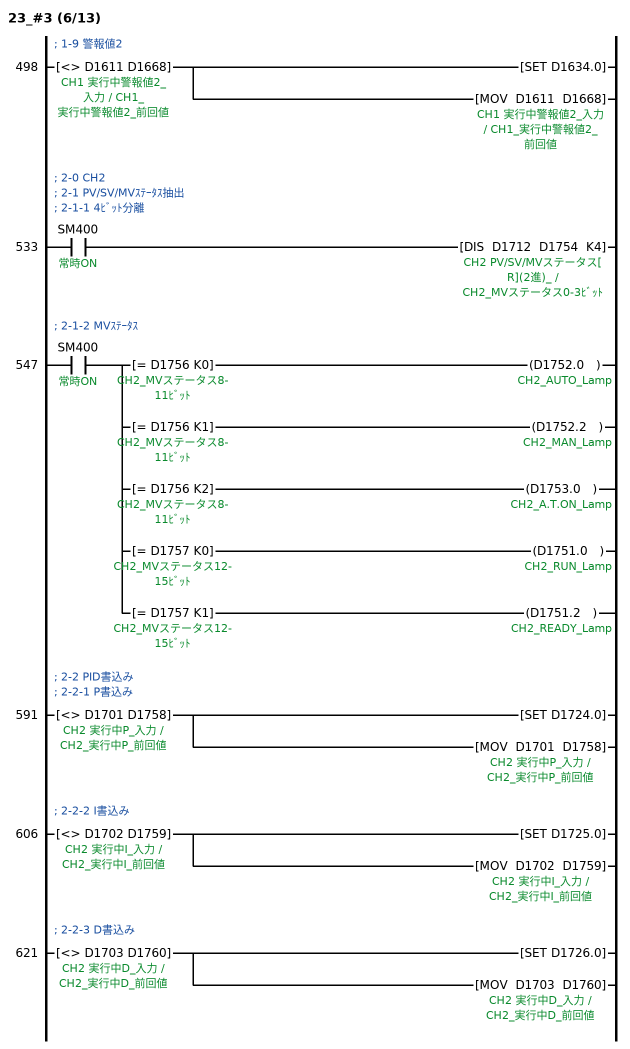
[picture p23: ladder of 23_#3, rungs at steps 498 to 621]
; 1-9 警報値2
498   LD<>    D1611 D1668  ; CH1 実行中警報値2_入力 / CH1_実行中警報値2_前回値
      SET     D1634.0
      MOV     D1611 D1668
; 2-0 CH2
; 2-1 PV/SV/MVｽﾃｰﾀｽ抽出
; 2-1-1 4ﾋﾞｯﾄ分離
533   LD      SM400  ; 常時ON
      DIS     D1712 D1754 K4  ; CH2 PV/SV/MVステータス[R](2進)_ / CH2_MVステータス0-3ﾋﾞｯﾄ
; 2-1-2 MVｽﾃｰﾀｽ
547   LD      SM400  ; 常時ON
      MPS
      AND=    D1756 K0  ; CH2_MVステータス8-11ﾋﾞｯﾄ
      OUT     D1752.0  ; CH2_AUTO_Lamp
      MRD
      AND=    D1756 K1  ; CH2_MVステータス8-11ﾋﾞｯﾄ
      OUT     D1752.2  ; CH2_MAN_Lamp
      MRD
      AND=    D1756 K2  ; CH2_MVステータス8-11ﾋﾞｯﾄ
      OUT     D1753.0  ; CH2_A.T.ON_Lamp
      MRD
      AND=    D1757 K0  ; CH2_MVステータス12-15ﾋﾞｯﾄ
      OUT     D1751.0  ; CH2_RUN_Lamp
      MPP
      AND=    D1757 K1  ; CH2_MVステータス12-15ﾋﾞｯﾄ
      OUT     D1751.2  ; CH2_READY_Lamp
; 2-2 PID書込み
; 2-2-1 P書込み
591   LD<>    D1701 D1758  ; CH2 実行中P_入力 / CH2_実行中P_前回値
      SET     D1724.0
      MOV     D1701 D1758
; 2-2-2 I書込み
606   LD<>    D1702 D1759  ; CH2 実行中I_入力 / CH2_実行中I_前回値
      SET     D1725.0
      MOV     D1702 D1759
; 2-2-3 D書込み
621   LD<>    D1703 D1760  ; CH2 実行中D_入力 / CH2_実行中D_前回値
      SET     D1726.0
      MOV     D1703 D1760
; 2-3 SV変化率
; 2-3-1 SV変化率下降
646   LD<>    D1704 D1761  ; CH2 SV変化率下降_入力 / CH2_SV変化率下降_前回値
      SET     D1727.0
      MOV     D1704 D1761
; 2-3-2 SV変化率上昇
663   LD<>    D1705 D1762  ; CH2 SV変化率上昇_入力 / CH2_SV変化率上昇_前回値
      SET     D1728.0
      MOV     D1705 D1762
; 2-4 ﾌﾟﾘｾｯﾄﾏﾆｭｱﾙ
679   LD<>    D1706 D1763  ; CH2 プリセットマニュアル_入力 / CH2_プリセットマニュアル_前回値
      SET     D1729.0
      MOV     D1706 D1763
; 2-5 MV/マニュアル出力 AUT/MAN切換え
705   LD      D1752.1  ; CH2_AUTO_SW
      MOV     H7FFE D1707  ; CH2 MV/マニュアル出力_入力
708   LD      D1752.3  ; CH2_MAN_SW
      MOV     H7FFD D1707
711   LD<>    D1707 D1764  ; CH2 MV/マニュアル出力_入力 / CH2_MV/マニュアル出力_前回値
      OR      D1752.1  ; CH2_AUTO_SW
      OR      D1752.3  ; CH2_MAN_SW
      SET     D1730.0
      MOV     D1707 D1764
; 2-6 実行中No
727   LD<>    D1708 D1765  ; CH2 実行中No_入力 / CH2_実行中No_前回値
      SET     D1731.0
      MOV     D1708 D1765
; 2-7 実行中SV
741   LD<>    D1709 D1766  ; CH2 実行中SV_入力 / CH2_実行中SV_前回値
      SET     D1732.0
      MOV     D1709 D1766
; 2-8 警報値1
755   LD<>    D1710 D1767  ; CH2 実行中警報値1_入力 / CH2_実行中警報値1_前回値
      SET     D1733.0
      MOV     D1710 D1767
; 2-9 警報値2
769   LD<>    D1711 D1768  ; CH2 実行中警報値2_入力 / CH2_実行中警報値2_前回値
      SET     D1734.0
      MOV     D1711 D1768
; 3-0 CH3
; 3-1 PV/SV/MVｽﾃｰﾀｽ抽出
; 3-1-1 4ﾋﾞｯﾄ分離
804   LD      SM400  ; 常時ON
      DIS     D1812 D1854 K4  ; CH3 PV/SV/MVステータス[R](2進)_ / CH3_MVステータス0-3ﾋﾞｯﾄ
; 3-1-2 MVｽﾃｰﾀｽ
818   LD      SM400  ; 常時ON
      MPS
      AND=    D1856 K0  ; CH3_MVステータス8-11ﾋﾞｯﾄ
      OUT     D1852.0  ; CH3_AUTO_Lamp
      MRD
      AND=    D1856 K1  ; CH3_MVステータス8-11ﾋﾞｯﾄ
      OUT     D1852.2  ; CH3_MAN_Lamp
      MRD
      AND=    D1856 K2  ; CH3_MVステータス8-11ﾋﾞｯﾄ
      OUT     D1853.0  ; CH3_A.T.ON_Lamp
      MRD
      AND=    D1857 K0  ; CH3_MVステータス12-15ﾋﾞｯﾄ
      OUT     D1851.0  ; CH3_RUN_Lamp
      MPP
      AND=    D1857 K1  ; CH3_MVステータス12-15ﾋﾞｯﾄ
      OUT     D1851.2  ; CH3_READY_Lamp
; 3-2 PID書込み
; 3-2-1 P書込み
862   LD<>    D1801 D1858  ; CH3 実行中P_入力 / CH3_実行中P_前回値
      SET     D1824.0
      MOV     D1801 D1858
; 3-2-2 I書込み
877   LD<>    D1802 D1859  ; CH3 実行中I_入力 / CH3_実行中I_前回値
      SET     D1825.0
      MOV     D1802 D1859
; 3-2-3 D書込み
892   LD<>    D1803 D1860  ; CH3 実行中D_入力 / CH3_実行中D_前回値
      SET     D1826.0
      MOV     D1803 D1860
; 3-3 SV変化率
; 3-3-1 SV変化率下降
917   LD<>    D1804 D1861  ; CH3 SV変化率下降_入力 / CH3_SV変化率下降_前回値
      SET     D1827.0
      MOV     D1804 D1861
; 3-3-2 SV変化率上昇
934   LD<>    D1805 D1862  ; CH3 SV変化率上昇_入力 / CH3_SV変化率上昇_前回値
      SET     D1828.0
      MOV     D1805 D1862
; 3-4 ﾌﾟﾘｾｯﾄﾏﾆｭｱﾙ
950   LD<>    D1806 D1863  ; CH3 プリセットマニュアル_入力 / CH3_プリセットマニュアル_前回値
      SET     D1829.0
      MOV     D1806 D1863
; 3-5 MV/マニュアル出力 AUT/MAN切換え
976   LD      D1852.1  ; CH3_AUTO_SW
      MOV     H7FFE D1807  ; CH3 MV/マニュアル出力_入力
979   LD      D1852.3  ; CH3_MAN_SW
      MOV     H7FFD D1807
982   LD<>    D1807 D1864  ; CH3 MV/マニュアル出力_入力 / CH3_MV/マニュアル出力_前回値
      OR      D1852.1  ; CH3_AUTO_SW
      OR      D1852.3  ; CH3_MAN_SW
      SET     D1830.0
      MOV     D1807 D1864
; 3-6 実行中No
998   LD<>    D1808 D1865  ; CH3 実行中No_入力 / CH3_実行中No_前回値
      SET     D1831.0
      MOV     D1808 D1865
; 3-7 実行中SV
1012  LD<>    D1809 D1866  ; CH3 実行中SV_入力 / CH3_実行中SV_前回値
      SET     D1832.0
      MOV     D1809 D1866
; 3-8 警報値1
1026  LD<>    D1810 D1867  ; CH3 実行中警報値1_入力 / CH3_実行中警報値1_前回値
      SET     D1833.0
      MOV     D1810 D1867
; 3-9 警報値2
1040  LD<>    D1811 D1868  ; CH3 実行中警報値2_入力 / CH3_実行中警報値2_前回値
      SET     D1834.0
      MOV     D1811 D1868
; 4-0 CH4
; 4-1 PV/SV/MVｽﾃｰﾀｽ抽出
; 4-1-1 4ﾋﾞｯﾄ分離
1075  LD      SM400  ; 常時ON
      DIS     D1912 D1954 K4  ; CH4 PV/SV/MVステータス[R](2進)_ / CH4_MVステータス0-3ﾋﾞｯﾄ
; 4-1-2 MVｽﾃｰﾀｽ
1089  LD      SM400  ; 常時ON
      MPS
      AND=    D1956 K0  ; CH4_MVステータス8-11ﾋﾞｯﾄ
      OUT     D1952.0  ; CH4_AUTO_Lamp
      MRD
      AND=    D1956 K1  ; CH4_MVステータス8-11ﾋﾞｯﾄ
      OUT     D1952.2  ; CH4_MAN_Lamp
      MRD
      AND=    D1956 K2  ; CH4_MVステータス8-11ﾋﾞｯﾄ
      OUT     D1953.0  ; CH4_A.T.ON_Lamp
      MRD
      AND=    D1957 K0  ; CH4_MVステータス12-15ﾋﾞｯﾄ
      OUT     D1951.0  ; CH4_RUN_Lamp
      MPP
      AND=    D1957 K1  ; CH4_MVステータス12-15ﾋﾞｯﾄ
      OUT     D1951.2  ; CH4_READY_Lamp
; 4-2 PID書込み
; 4-2-1 P書込み
1133  LD<>    D1901 D1958  ; CH4 実行中P_入力 / CH4_実行中P_前回値
      SET     D1924.0
      MOV     D1901 D1958
; 4-2-2 I書込み
1148  LD<>    D1902 D1959  ; CH4 実行中I_入力 / CH4_実行中I_前回値
      SET     D1925.0
      MOV     D1902 D1959
; 4-2-3 D書込み
1163  LD<>    D1903 D1960  ; CH4 実行中D_入力 / CH4_実行中D_前回値
      SET     D1926.0
      MOV     D1903 D1960
; 4-3 SV変化率
; 4-3-1 SV変化率下降
1188  LD<>    D1904 D1961  ; CH4 SV変化率下降_入力 / CH4_SV変化率下降_前回値
      SET     D1927.0
      MOV     D1904 D1961
; 4-3-2 SV変化率上昇
1205  LD<>    D1905 D1962  ; CH4 SV変化率上昇_入力 / CH4_SV変化率上昇_前回値
      SET     D1928.0
      MOV     D1905 D1962
; 4-4 ﾌﾟﾘｾｯﾄﾏﾆｭｱﾙ
1221  LD<>    D1906 D1963  ; CH4 プリセットマニュアル_入力 / CH4_プリセットマニュアル_前回値
      SET     D1929.0
      MOV     D1906 D1963
; 4-5 MV/マニュアル出力 AUT/MAN切換え
1247  LD      D1952.1  ; CH4_AUTO_SW
      MOV     H7FFE D1907  ; CH4 MV/マニュアル出力_入力
1250  LD      D1952.3  ; CH4_MAN_SW
      MOV     H7FFD D1907
1253  LD<>    D1907 D1964  ; CH4 MV/マニュアル出力_入力 / CH4_MV/マニュアル出力_前回値
      OR      D1952.1  ; CH4_AUTO_SW
      OR      D1952.3  ; CH4_MAN_SW
      SET     D1930.0
      MOV     D1907 D1964
; 4-6 実行中No
1269  LD<>    D1908 D1965  ; CH4 実行中No_入力 / CH4_実行中No_前回値
      SET     D1931.0
      MOV     D1908 D1965
; 4-7 実行中SV
1283  LD<>    D1909 D1966  ; CH4 実行中SV_入力 / CH4_実行中SV_前回値
      SET     D1932.0
      MOV     D1909 D1966
; 4-8 警報値1
1297  LD<>    D1910 D1967  ; CH4 実行中警報値1_入力 / CH4_実行中警報値1_前回値
      SET     D1933.0
      MOV     D1910 D1967
; 4-9 警報値2
1311  LD<>    D1911 D1968  ; CH4 実行中警報値2_入力 / CH4_実行中警報値2_前回値
      SET     D1934.0
      MOV     D1911 D1968
1317  END
END_PROGRAM

PROGRAM 24_#4  // SB100
; 0-0 共通
; 0-1 RUN/READY切替
; 0-1-1 CH1 RUN/READY切替
31    LD      D2151.1  ; CH1_RUN_SW
      BRST    D2001 K0  ; CH別RUN/READY切換(2進)_入力
35    LD      D2151.3  ; CH1_READY_SW
      BSET    D2001 K0
; 0-1-2 CH2 RUN/READY切替
53    LD      D2251.1  ; CH2_RUN_SW
      BRST    D2001 K1
57    LD      D2251.3  ; CH2_READY_SW
      BSET    D2001 K1
; 0-1-3 CH3 RUN/READY切替
75    LD      D2351.1  ; CH3_RUN_SW
      BRST    D2001 K2
79    LD      D2351.3  ; CH3_READY_SW
      BSET    D2001 K2
; 0-1-4 CH4 RUN/READY切替
97    LD      D2451.1  ; CH4_RUN_SW
      BRST    D2001 K3
101   LD      D2451.3  ; CH4_READY_SW
      BSET    D2001 K3
; 0-1-5 RUN/READYﾄﾘｶﾞｰ
117   LD      D2151.1  ; CH1_RUN_SW
      OR      D2151.3  ; CH1_READY_SW
      OR      D2251.1  ; CH2_RUN_SW
      OR      D2251.3  ; CH2_READY_SW
      OR      D2351.1  ; CH3_RUN_SW
      OR      D2351.3  ; CH3_READY_SW
      OR      D2451.1  ; CH4_RUN_SW
      OR      D2451.3  ; CH4_READY_SW
      SET     D2005.0
; 0-2 ｵｰﾄﾁｭｰﾆﾝｸﾞ実行停止
; 0-2-1 CH1ｵｰﾄﾁｭｰﾆﾝｸﾞ
151   LD      D2153.1  ; CH1_A.T.ON_SW
      MOV     H101 D2002  ; オートチューニング(16進)_入力
154   LD      D2153.3  ; CH1_A.T.OFF_SW
      MOV     H100 D2002
; 0-2-2 CH2ｵｰﾄﾁｭｰﾆﾝｸﾞ
169   LD      D2253.1  ; CH2_A.T.ON_SW
      MOV     H201 D2002
172   LD      D2253.3  ; CH2_A.T.OFF_SW
      MOV     H200 D2002
; 0-2-3 CH3ｵｰﾄﾁｭｰﾆﾝｸﾞ
187   LD      D2353.1  ; CH3_A.T.ON_SW
      MOV     H301 D2002
190   LD      D2353.3  ; CH3_A.T.OFF_SW
      MOV     H300 D2002
; 0-2-4 CH4ｵｰﾄﾁｭｰﾆﾝｸﾞ
205   LD      D2453.1  ; CH4_A.T.ON_SW
      MOV     H401 D2002
208   LD      D2453.3  ; CH4_A.T.OFF_SW
      MOV     H400 D2002
; 0-2-5 ｵｰﾄﾁｭｰﾆﾝｸﾞﾄﾘｶﾞｰ
224   LD      D2153.1  ; CH1_A.T.ON_SW
      OR      D2153.3  ; CH1_A.T.OFF_SW
      OR      D2253.1  ; CH2_A.T.ON_SW
      OR      D2253.3  ; CH2_A.T.OFF_SW
      OR      D2353.1  ; CH3_A.T.ON_SW
      OR      D2353.3  ; CH3_A.T.OFF_SW
      OR      D2453.1  ; CH4_A.T.ON_SW
      OR      D2453.3  ; CH4_A.T.OFF_SW
      SET     D2006.0
; 1-0 CH1
; 1-1 PV/SV/MVｽﾃｰﾀｽ抽出
; 1-1-1 4ﾋﾞｯﾄ分離
262   LD      SM400  ; 常時ON
      DIS     D2112 D2154 K4  ; CH1 PV/SV/MVステータス[R](2進)_ / CH1_PVステータス0-3ﾋﾞｯﾄ
; 1-1-2 MVｽﾃｰﾀｽ
276   LD      SM400  ; 常時ON
      MPS
      AND=    D2156 K0  ; CH1_MVステータス8-11ﾋﾞｯﾄ
      OUT     D2152.0  ; CH1_AUTO_Lamp
      MRD
      AND=    D2156 K1  ; CH1_MVステータス8-11ﾋﾞｯﾄ
      OUT     D2152.2  ; CH1_MAN_Lamp
      MRD
      AND=    D2156 K2  ; CH1_MVステータス8-11ﾋﾞｯﾄ
      OUT     D2153.0  ; CH1_A.T.ON_Lamp
      MRD
      AND=    D2157 K0  ; CH1_RUN/READY12-15ﾋﾞｯﾄ
      OUT     D2151.0  ; CH1_RUN_Lamp
      MPP
      AND=    D2157 K1  ; CH1_RUN/READY12-15ﾋﾞｯﾄ
      OUT     D2151.2  ; CH1_READY_Lamp
; 1-2 PID書込み
; 1-2-1 P書込み
320   LD<>    D2101 D2158  ; CH1 実行中P_入力 / CH1_実行中P_前回値
      SET     D2124.0
      MOV     D2101 D2158
; 1-2-2 I書込み
335   LD<>    D2102 D2159  ; CH1 実行中I_入力 / CH1_実行中I_前回値
      SET     D2125.0
      MOV     D2102 D2159
; 1-2-3 D書込み
350   LD<>    D2103 D2160  ; CH1 実行中D_入力 / CH1_実行中D_前回値
      SET     D2126.0
      MOV     D2103 D2160
; 1-3 SV変化率
; 1-3-1 SV変化率下降
375   LD<>    D2104 D2161  ; CH1 SV変化率下降_入力 / CH1_SV変化率下降_前回値
      SET     D2127.0
      MOV     D2104 D2161
; 1-3-2 SV変化率上昇
392   LD<>    D2105 D2162  ; CH1 SV変化率上昇_入力 / CH1_SV変化率上昇_前回値
      SET     D2128.0
      MOV     D2105 D2162
; 1-4 ﾌﾟﾘｾｯﾄﾏﾆｭｱﾙ
408   LD<>    D2106 D2163  ; CH1 プリセットマニュアル_入力 / CH1_プリセットマニュアル_前回値
      SET     D2129.0
      MOV     D2106 D2163
; 1-5 MV/マニュアル出力 AUT/MAN切換え
434   LD      D2152.1  ; CH1_AUTO_SW
      MOV     H7FFE D2107  ; CH1 MV/マニュアル出力_入力
437   LD      D2152.3  ; CH1_MAN_SW
      MOV     H7FFD D2107
440   LD<>    D2107 D2164  ; CH1 MV/マニュアル出力_入力 / CH1_MV/マニュアル出力_前回値
      OR      D2152.1  ; CH1_AUTO_SW
      OR      D2152.3  ; CH1_MAN_SW
      SET     D2130.0
      MOV     D2107 D2164
; 1-6 実行中No
456   LD<>    D2108 D2165  ; CH1 実行中No_入力 / CH1_実行中No_前回値
      SET     D2131.0
      MOV     D2108 D2165
; 1-7 実行中SV
470   LD<>    D2109 D2166  ; CH1 実行中SV_入力 / CH1_実行中SV_前回値
      SET     D2132.0
      MOV     D2109 D2166
; 1-8 警報値1
484   LD<>    D2110 D2167  ; CH1 実行中警報値1_入力 / CH1_実行中警報値1_前回値
      SET     D2133.0
      MOV     D2110 D2167
; 1-9 警報値2
498   LD<>    D2111 D2168  ; CH1 実行中警報値2_入力 / CH1_実行中警報値2_前回値
      SET     D2134.0
      MOV     D2111 D2168
; 2-0 CH2
; 2-1 PV/SV/MVｽﾃｰﾀｽ抽出
; 2-1-1 4ﾋﾞｯﾄ分離
533   LD      SM400  ; 常時ON
      DIS     D2212 D2254 K4  ; CH2 PV/SV/MVステータス[R](2進)_ / CH2_MVステータス0-3ﾋﾞｯﾄ
; 2-1-2 MVｽﾃｰﾀｽ
547   LD      SM400  ; 常時ON
      MPS
      AND=    D2256 K0  ; CH2_MVステータス8-11ﾋﾞｯﾄ
      OUT     D2252.0  ; CH2_AUTO_Lamp
      MRD
      AND=    D2256 K1  ; CH2_MVステータス8-11ﾋﾞｯﾄ
      OUT     D2252.2  ; CH2_MAN_Lamp
      MRD
      AND=    D2256 K2  ; CH2_MVステータス8-11ﾋﾞｯﾄ
      OUT     D2253.0  ; CH2_A.T.ON_Lamp
      MRD
      AND=    D2257 K0  ; CH2_MVステータス12-15ﾋﾞｯﾄ
      OUT     D2251.0  ; CH2_RUN_Lamp
      MPP
      AND=    D2257 K1  ; CH2_MVステータス12-15ﾋﾞｯﾄ
      OUT     D2251.2  ; CH2_READY_Lamp
; 2-2 PID書込み
; 2-2-1 P書込み
591   LD<>    D2201 D2258  ; CH2 実行中P_入力 / CH2_実行中P_前回値
      SET     D2224.0
      MOV     D2201 D2258
; 2-2-2 I書込み
606   LD<>    D2202 D2259  ; CH2 実行中I_入力 / CH2_実行中I_前回値
      SET     D2225.0
      MOV     D2202 D2259
; 2-2-3 D書込み
621   LD<>    D2203 D2260  ; CH2 実行中D_入力 / CH2_実行中D_前回値
      SET     D2226.0
      MOV     D2203 D2260
; 2-3 SV変化率
; 2-3-1 SV変化率下降
646   LD<>    D2204 D2261  ; CH2 SV変化率下降_入力 / CH2_SV変化率下降_前回値
      SET     D2227.0
      MOV     D2204 D2261
; 2-3-2 SV変化率上昇
663   LD<>    D2205 D2262  ; CH2 SV変化率上昇_入力 / CH2_SV変化率上昇_前回値
      SET     D2228.0
      MOV     D2205 D2262
; 2-4 ﾌﾟﾘｾｯﾄﾏﾆｭｱﾙ
679   LD<>    D2206 D2263  ; CH2 プリセットマニュアル_入力 / CH2_プリセットマニュアル_前回値
      SET     D2229.0
      MOV     D2206 D2263
; 2-5 MV/マニュアル出力 AUT/MAN切換え
705   LD      D2252.1  ; CH2_AUTO_SW
      MOV     H7FFE D2207  ; CH2 MV/マニュアル出力_入力
708   LD      D2252.3  ; CH2_MAN_SW
      MOV     H7FFD D2207
711   LD<>    D2207 D2264  ; CH2 MV/マニュアル出力_入力 / CH2_MV/マニュアル出力_前回値
      OR      D2252.1  ; CH2_AUTO_SW
      OR      D2252.3  ; CH2_MAN_SW
      SET     D2230.0
      MOV     D2207 D2264
; 2-6 実行中No
727   LD<>    D2208 D2265  ; CH2 実行中No_入力 / CH2_実行中No_前回値
      SET     D2231.0
      MOV     D2208 D2265
; 2-7 実行中SV
741   LD<>    D2209 D2266  ; CH2 実行中SV_入力 / CH2_実行中SV_前回値
      SET     D2232.0
      MOV     D2209 D2266
; 2-8 警報値1
755   LD<>    D2210 D2267  ; CH2 実行中警報値1_入力 / CH2_実行中警報値1_前回値
      SET     D2233.0
      MOV     D2210 D2267
; 2-9 警報値2
769   LD<>    D2211 D2268  ; CH2 実行中警報値2_入力 / CH2_実行中警報値2_前回値
      SET     D2234.0
      MOV     D2211 D2268
; 3-0 CH3
; 3-1 PV/SV/MVｽﾃｰﾀｽ抽出
; 3-1-1 4ﾋﾞｯﾄ分離
804   LD      SM400  ; 常時ON
      DIS     D2312 D2354 K4  ; CH3 PV/SV/MVステータス[R](2進)_ / CH3_MVステータス0-3ﾋﾞｯﾄ
; 3-1-2 MVｽﾃｰﾀｽ
818   LD      SM400  ; 常時ON
      MPS
      AND=    D2356 K0  ; CH3_MVステータス8-11ﾋﾞｯﾄ
      OUT     D2352.0  ; CH3_AUTO_Lamp
      MRD
      AND=    D2356 K1  ; CH3_MVステータス8-11ﾋﾞｯﾄ
      OUT     D2352.2  ; CH3_MAN_Lamp
      MRD
      AND=    D2356 K2  ; CH3_MVステータス8-11ﾋﾞｯﾄ
      OUT     D2353.0  ; CH3_A.T.ON_Lamp
      MRD
      AND=    D2357 K0  ; CH3_MVステータス12-15ﾋﾞｯﾄ
      OUT     D2351.0  ; CH3_RUN_Lamp
      MPP
      AND=    D2357 K1  ; CH3_MVステータス12-15ﾋﾞｯﾄ
      OUT     D2351.2  ; CH3_READY_Lamp
; 3-2 PID書込み
; 3-2-1 P書込み
862   LD<>    D2301 D2358  ; CH3 実行中P_入力 / CH3_実行中P_前回値
      SET     D2324.0
      MOV     D2301 D2358
; 3-2-2 I書込み
877   LD<>    D2302 D2359  ; CH3 実行中I_入力 / CH3_実行中I_前回値
      SET     D2325.0
      MOV     D2302 D2359
; 3-2-3 D書込み
892   LD<>    D2303 D2360  ; CH3 実行中D_入力 / CH3_実行中D_前回値
      SET     D2326.0
      MOV     D2303 D2360
; 3-3 SV変化率
; 3-3-1 SV変化率下降
917   LD<>    D2304 D2361  ; CH3 SV変化率下降_入力 / CH3_SV変化率下降_前回値
      SET     D2327.0
      MOV     D2304 D2361
; 3-3-2 SV変化率上昇
934   LD<>    D2305 D2362  ; CH3 SV変化率上昇_入力 / CH3_SV変化率上昇_前回値
      SET     D2328.0
      MOV     D2305 D2362
; 3-4 ﾌﾟﾘｾｯﾄﾏﾆｭｱﾙ
950   LD<>    D2306 D2363  ; CH3 プリセットマニュアル_入力 / CH3_プリセットマニュアル_前回値
      SET     D2329.0
      MOV     D2306 D2363
; 3-5 MV/マニュアル出力 AUT/MAN切換え
976   LD      D2352.1  ; CH3_AUTO_SW
      MOV     H7FFE D2307  ; CH3 MV/マニュアル出力_入力
979   LD      D2352.3  ; CH3_MAN_SW
      MOV     H7FFD D2307
982   LD<>    D2307 D2364  ; CH3 MV/マニュアル出力_入力 / CH3_MV/マニュアル出力_前回値
      OR      D2352.1  ; CH3_AUTO_SW
      OR      D2352.3  ; CH3_MAN_SW
      SET     D2330.0
      MOV     D2307 D2364
; 3-6 実行中No
998   LD<>    D2308 D2365  ; CH3 実行中No_入力 / CH3_実行中No_前回値
      SET     D2331.0
      MOV     D2308 D2365
; 3-7 実行中SV
1012  LD<>    D2309 D2366  ; CH3 実行中SV_入力 / CH3_実行中SV_前回値
      SET     D2332.0
      MOV     D2309 D2366
; 3-8 警報値1
1026  LD<>    D2310 D2367  ; CH3 実行中警報値1_入力 / CH3_実行中警報値1_前回値
      SET     D2333.0
      MOV     D2310 D2367
; 3-9 警報値2
1040  LD<>    D2311 D2368  ; CH3 実行中警報値2_入力 / CH3_実行中警報値2_前回値
      SET     D2334.0
      MOV     D2311 D2368
; 4-0 CH4
; 4-1 PV/SV/MVｽﾃｰﾀｽ抽出
; 4-1-1 4ﾋﾞｯﾄ分離
1075  LD      SM400  ; 常時ON
      DIS     D2412 D2454 K4  ; CH4 PV/SV/MVステータス[R](2進)_ / CH4_MVステータス0-3ﾋﾞｯﾄ
; 4-1-2 MVｽﾃｰﾀｽ
1089  LD      SM400  ; 常時ON
      MPS
      AND=    D2456 K0  ; CH4_MVステータス8-11ﾋﾞｯﾄ
      OUT     D2452.0  ; CH4_AUTO_Lamp
      MRD
      AND=    D2456 K1  ; CH4_MVステータス8-11ﾋﾞｯﾄ
      OUT     D2452.2  ; CH4_MAN_Lamp
      MRD
      AND=    D2456 K2  ; CH4_MVステータス8-11ﾋﾞｯﾄ
      OUT     D2453.0  ; CH4_A.T.ON_Lamp
      MRD
      AND=    D2457 K0  ; CH4_MVステータス12-15ﾋﾞｯﾄ
      OUT     D2451.0  ; CH4_RUN_Lamp
      MPP
      AND=    D2457 K1  ; CH4_MVステータス12-15ﾋﾞｯﾄ
      OUT     D2451.2  ; CH4_READY_Lamp
; 4-2 PID書込み
; 4-2-1 P書込み
1133  LD<>    D2401 D2458  ; CH4 実行中P_入力 / CH4_実行中P_前回値
      SET     D2424.0
      MOV     D2401 D2458
; 4-2-2 I書込み
1148  LD<>    D2402 D2459  ; CH4 実行中I_入力 / CH4_実行中I_前回値
      SET     D2425.0
      MOV     D2402 D2459
; 4-2-3 D書込み
1163  LD<>    D2403 D2460  ; CH4 実行中D_入力 / CH4_実行中D_前回値
      SET     D2426.0
      MOV     D2403 D2460
; 4-3 SV変化率
; 4-3-1 SV変化率下降
1188  LD<>    D2404 D2461  ; CH4 SV変化率下降_入力 / CH4_SV変化率下降_前回値
      SET     D2427.0
      MOV     D2404 D2461
; 4-3-2 SV変化率上昇
1205  LD<>    D2405 D2462  ; CH4 SV変化率上昇_入力 / CH4_SV変化率上昇_前回値
      SET     D2428.0
      MOV     D2405 D2462
; 4-4 ﾌﾟﾘｾｯﾄﾏﾆｭｱﾙ
1221  LD<>    D2406 D2463  ; CH4 プリセットマニュアル_入力 / CH4_プリセットマニュアル_前回値
      SET     D2429.0
      MOV     D2406 D2463
; 4-5 MV/マニュアル出力 AUT/MAN切換え
1247  LD      D2452.1  ; CH4_AUTO_SW
      MOV     H7FFE D2407  ; CH4 MV/マニュアル出力_入力
1250  LD      D2452.3  ; CH4_MAN_SW
      MOV     H7FFD D2407
1253  LD<>    D2407 D2464  ; CH4 MV/マニュアル出力_入力 / CH4_MV/マニュアル出力_前回値
      OR      D2452.1  ; CH4_AUTO_SW
      OR      D2452.3  ; CH4_MAN_SW
      SET     D2430.0
      MOV     D2407 D2464
; 4-6 実行中No
1269  LD<>    D2408 D2465  ; CH4 実行中No_入力 / CH4_実行中No_前回値
      SET     D2431.0
      MOV     D2408 D2465
; 4-7 実行中SV
1283  LD<>    D2409 D2466  ; CH4 実行中SV_入力 / CH4_実行中SV_前回値
      SET     D2432.0
      MOV     D2409 D2466
; 4-8 警報値1
1297  LD<>    D2410 D2467  ; CH4 実行中警報値1_入力 / CH4_実行中警報値1_前回値
      SET     D2433.0
      MOV     D2410 D2467
; 4-9 警報値2
1311  LD<>    D2411 D2468  ; CH4 実行中警報値2_入力 / CH4_実行中警報値2_前回値
      SET     D2434.0
      MOV     D2411 D2468
1317  END
END_PROGRAM

PROGRAM 25_#5  // SB100
; 0-0 共通
; 0-1 RUN/READY切替
; 0-1-1 CH1 RUN/READY切替
31    LD      D2651.1  ; CH1_RUN_SW
      BRST    D2501 K0  ; CH別RUN/READY切換(2進)_入力
35    LD      D2651.3  ; CH1_READY_SW
      BSET    D2501 K0
; 0-1-2 CH2 RUN/READY切替
53    LD      D2751.1  ; CH2_RUN_SW
      BRST    D2501 K1
57    LD      D2751.3  ; CH2_READY_SW
      BSET    D2501 K1
; 0-1-3 CH3 RUN/READY切替
75    LD      D2851.1  ; CH3_RUN_SW
      BRST    D2501 K2
79    LD      D2851.3  ; CH3_READY_SW
      BSET    D2501 K2
; 0-1-4 CH4 RUN/READY切替
97    LD      D2951.1  ; CH4_RUN_SW
      BRST    D2501 K3
101   LD      D2951.3  ; CH4_READY_SW
      BSET    D2501 K3
; 0-1-5 RUN/READYﾄﾘｶﾞｰ
117   LD      D2651.1  ; CH1_RUN_SW
      OR      D2651.3  ; CH1_READY_SW
      OR      D2751.1  ; CH2_RUN_SW
      OR      D2751.3  ; CH2_READY_SW
      OR      D2851.1  ; CH3_RUN_SW
      OR      D2851.3  ; CH3_READY_SW
      OR      D2951.1  ; CH4_RUN_SW
      OR      D2951.3  ; CH4_READY_SW
      SET     D2505.0
; 0-2 ｵｰﾄﾁｭｰﾆﾝｸﾞ実行停止
; 0-2-1 CH1ｵｰﾄﾁｭｰﾆﾝｸﾞ
151   LD      D2653.1  ; CH1_A.T.ON_SW
      MOV     H101 D2502  ; オートチューニング(16進)_入力
154   LD      D2653.3  ; CH1_A.T.OFF_SW
      MOV     H100 D2502
; 0-2-2 CH2ｵｰﾄﾁｭｰﾆﾝｸﾞ
169   LD      D2753.1  ; CH2_A.T.ON_SW
      MOV     H201 D2502
172   LD      D2753.3  ; CH2_A.T.OFF_SW
      MOV     H200 D2502
; 0-2-3 CH3ｵｰﾄﾁｭｰﾆﾝｸﾞ
187   LD      D2853.1  ; CH3_A.T.ON_SW
      MOV     H301 D2502
190   LD      D2853.3  ; CH3_A.T.OFF_SW
      MOV     H300 D2502
; 0-2-4 CH4ｵｰﾄﾁｭｰﾆﾝｸﾞ
205   LD      D2953.1  ; CH4_A.T.ON_SW
      MOV     H401 D2502
208   LD      D2953.3  ; CH4_A.T.OFF_SW
      MOV     H400 D2502
; 0-2-5 ｵｰﾄﾁｭｰﾆﾝｸﾞﾄﾘｶﾞｰ
224   LD      D2653.1  ; CH1_A.T.ON_SW
      OR      D2653.3  ; CH1_A.T.OFF_SW
      OR      D2753.1  ; CH2_A.T.ON_SW
      OR      D2753.3  ; CH2_A.T.OFF_SW
      OR      D2853.1  ; CH3_A.T.ON_SW
      OR      D2853.3  ; CH3_A.T.OFF_SW
      OR      D2953.1  ; CH4_A.T.ON_SW
      OR      D2953.3  ; CH4_A.T.OFF_SW
      SET     D2506.0
; 1-0 CH1
; 1-1 PV/SV/MVｽﾃｰﾀｽ抽出
; 1-1-1 4ﾋﾞｯﾄ分離
262   LD      SM400  ; 常時ON
      DIS     D2612 D2654 K4  ; CH1 PV/SV/MVステータス[R](2進)_ / CH1_PVステータス0-3ﾋﾞｯﾄ
; 1-1-2 MVｽﾃｰﾀｽ
276   LD      SM400  ; 常時ON
      MPS
      AND=    D2656 K0  ; CH1_MVステータス8-11ﾋﾞｯﾄ
      OUT     D2652.0  ; CH1_AUTO_Lamp
      MRD
      AND=    D2656 K1  ; CH1_MVステータス8-11ﾋﾞｯﾄ
      OUT     D2652.2  ; CH1_MAN_Lamp
      MRD
      AND=    D2656 K2  ; CH1_MVステータス8-11ﾋﾞｯﾄ
      OUT     D2653.0  ; CH1_A.T.ON_Lamp
      MRD
      AND=    D2657 K0  ; CH1_RUN/READY12-15ﾋﾞｯﾄ
      OUT     D2651.0  ; CH1_RUN_Lamp
      MPP
      AND=    D2657 K1  ; CH1_RUN/READY12-15ﾋﾞｯﾄ
      OUT     D2651.2  ; CH1_READY_Lamp
; 1-2 PID書込み
; 1-2-1 P書込み
320   LD<>    D2601 D2658  ; CH1 実行中P_入力 / CH1_実行中P_前回値
      SET     D2624.0
      MOV     D2601 D2658
; 1-2-2 I書込み
335   LD<>    D2602 D2659  ; CH1 実行中I_入力 / CH1_実行中I_前回値
      SET     D2625.0
      MOV     D2602 D2659
; 1-2-3 D書込み
350   LD<>    D2603 D2660  ; CH1 実行中D_入力 / CH1_実行中D_前回値
      SET     D2626.0
      MOV     D2603 D2660
; 1-3 SV変化率
; 1-3-1 SV変化率下降
375   LD<>    D2604 D2661  ; CH1 SV変化率下降_入力 / CH1_SV変化率下降_前回値
      SET     D2627.0
      MOV     D2604 D2661
; 1-3-2 SV変化率上昇
392   LD<>    D2605 D2662  ; CH1 SV変化率上昇_入力 / CH1_SV変化率上昇_前回値
      SET     D2628.0
      MOV     D2605 D2662
; 1-4 ﾌﾟﾘｾｯﾄﾏﾆｭｱﾙ
408   LD<>    D2606 D2663  ; CH1 プリセットマニュアル_入力 / CH1_プリセットマニュアル_前回値
      SET     D2629.0
      MOV     D2606 D2663
; 1-5 MV/マニュアル出力 AUT/MAN切換え
434   LD      D2652.1  ; CH1_AUTO_SW
      MOV     H7FFE D2607  ; CH1 MV/マニュアル出力_入力
437   LD      D2652.3  ; CH1_MAN_SW
      MOV     H7FFD D2607
440   LD<>    D2607 D2664  ; CH1 MV/マニュアル出力_入力 / CH1_MV/マニュアル出力_前回値
      OR      D2652.1  ; CH1_AUTO_SW
      OR      D2652.3  ; CH1_MAN_SW
      SET     D2630.0
      MOV     D2607 D2664
; 1-6 実行中No
456   LD<>    D2608 D2665  ; CH1 実行中No_入力 / CH1_実行中No_前回値
      SET     D2631.0
      MOV     D2608 D2665
; 1-7 実行中SV
470   LD<>    D2609 D2666  ; CH1 実行中SV_入力 / CH1_実行中SV_前回値
      SET     D2632.0
      MOV     D2609 D2666
; 1-8 警報値1
484   LD<>    D2610 D2667  ; CH1 実行中警報値1_入力 / CH1_実行中警報値1_前回値
      SET     D2633.0
      MOV     D2610 D2667
; 1-9 警報値2
498   LD<>    D2611 D2668  ; CH1 実行中警報値2_入力 / CH1_実行中警報値2_前回値
      SET     D2634.0
      MOV     D2611 D2668
; 2-0 CH2
; 2-1 PV/SV/MVｽﾃｰﾀｽ抽出
; 2-1-1 4ﾋﾞｯﾄ分離
533   LD      SM400  ; 常時ON
      DIS     D2712 D2754 K4  ; CH2 PV/SV/MVステータス[R](2進)_ / CH2_MVステータス0-3ﾋﾞｯﾄ
; 2-1-2 MVｽﾃｰﾀｽ
547   LD      SM400  ; 常時ON
      MPS
      AND=    D2756 K0  ; CH2_MVステータス8-11ﾋﾞｯﾄ
      OUT     D2752.0  ; CH2_AUTO_Lamp
      MRD
      AND=    D2756 K1  ; CH2_MVステータス8-11ﾋﾞｯﾄ
      OUT     D2752.2  ; CH2_MAN_Lamp
      MRD
      AND=    D2756 K2  ; CH2_MVステータス8-11ﾋﾞｯﾄ
      OUT     D2753.0  ; CH2_A.T.ON_Lamp
      MRD
      AND=    D2757 K0  ; CH2_MVステータス12-15ﾋﾞｯﾄ
      OUT     D2751.0  ; CH2_RUN_Lamp
      MPP
      AND=    D2757 K1  ; CH2_MVステータス12-15ﾋﾞｯﾄ
      OUT     D2751.2  ; CH2_READY_Lamp
; 2-2 PID書込み
; 2-2-1 P書込み
591   LD<>    D2701 D2758  ; CH2 実行中P_入力 / CH2_実行中P_前回値
      SET     D2724.0
      MOV     D2701 D2758
; 2-2-2 I書込み
606   LD<>    D2702 D2759  ; CH2 実行中I_入力 / CH2_実行中I_前回値
      SET     D2725.0
      MOV     D2702 D2759
; 2-2-3 D書込み
621   LD<>    D2703 D2760  ; CH2 実行中D_入力 / CH2_実行中D_前回値
      SET     D2726.0
      MOV     D2703 D2760
; 2-3 SV変化率
; 2-3-1 SV変化率下降
646   LD<>    D2704 D2761  ; CH2 SV変化率下降_入力 / CH2_SV変化率下降_前回値
      SET     D2727.0
      MOV     D2704 D2761
; 2-3-2 SV変化率上昇
663   LD<>    D2705 D2762  ; CH2 SV変化率上昇_入力 / CH2_SV変化率上昇_前回値
      SET     D2728.0
      MOV     D2705 D2762
; 2-4 ﾌﾟﾘｾｯﾄﾏﾆｭｱﾙ
679   LD<>    D2706 D2763  ; CH2 プリセットマニュアル_入力 / CH2_プリセットマニュアル_前回値
      SET     D2729.0
      MOV     D2706 D2763
; 2-5 MV/マニュアル出力 AUT/MAN切換え
705   LD      D2752.1  ; CH2_AUTO_SW
      MOV     H7FFE D2707  ; CH2 MV/マニュアル出力_入力
708   LD      D2752.3  ; CH2_MAN_SW
      MOV     H7FFD D2707
711   LD<>    D2707 D2764  ; CH2 MV/マニュアル出力_入力 / CH2_MV/マニュアル出力_前回値
      OR      D2752.1  ; CH2_AUTO_SW
      OR      D2752.3  ; CH2_MAN_SW
      SET     D2730.0
      MOV     D2707 D2764
; 2-6 実行中No
727   LD<>    D2708 D2765  ; CH2 実行中No_入力 / CH2_実行中No_前回値
      SET     D2731.0
      MOV     D2708 D2765
; 2-7 実行中SV
741   LD<>    D2709 D2766  ; CH2 実行中SV_入力 / CH2_実行中SV_前回値
      SET     D2732.0
      MOV     D2709 D2766
; 2-8 警報値1
755   LD<>    D2710 D2767  ; CH2 実行中警報値1_入力 / CH2_実行中警報値1_前回値
      SET     D2733.0
      MOV     D2710 D2767
; 2-9 警報値2
769   LD<>    D2711 D2768  ; CH2 実行中警報値2_入力 / CH2_実行中警報値2_前回値
      SET     D2734.0
      MOV     D2711 D2768
; 3-0 CH3
; 3-1 PV/SV/MVｽﾃｰﾀｽ抽出
; 3-1-1 4ﾋﾞｯﾄ分離
804   LD      SM400  ; 常時ON
      DIS     D2812 D2854 K4  ; CH3 PV/SV/MVステータス[R](2進)_ / CH3_MVステータス0-3ﾋﾞｯﾄ
; 3-1-2 MVｽﾃｰﾀｽ
818   LD      SM400  ; 常時ON
      MPS
      AND=    D2856 K0  ; CH3_MVステータス8-11ﾋﾞｯﾄ
      OUT     D2852.0  ; CH3_AUTO_Lamp
      MRD
      AND=    D2856 K1  ; CH3_MVステータス8-11ﾋﾞｯﾄ
      OUT     D2852.2  ; CH3_MAN_Lamp
      MRD
      AND=    D2856 K2  ; CH3_MVステータス8-11ﾋﾞｯﾄ
      OUT     D2853.0  ; CH3_A.T.ON_Lamp
      MRD
      AND=    D2857 K0  ; CH3_MVステータス12-15ﾋﾞｯﾄ
      OUT     D2851.0  ; CH3_RUN_Lamp
      MPP
      AND=    D2857 K1  ; CH3_MVステータス12-15ﾋﾞｯﾄ
      OUT     D2851.2  ; CH3_READY_Lamp
; 3-2 PID書込み
; 3-2-1 P書込み
862   LD<>    D2801 D2858  ; CH3 実行中P_入力 / CH3_実行中P_前回値
      SET     D2824.0
      MOV     D2801 D2858
; 3-2-2 I書込み
877   LD<>    D2802 D2859  ; CH3 実行中I_入力 / CH3_実行中I_前回値
      SET     D2825.0
      MOV     D2802 D2859
; 3-2-3 D書込み
892   LD<>    D2803 D2860  ; CH3 実行中D_入力 / CH3_実行中D_前回値
      SET     D2826.0
      MOV     D2803 D2860
; 3-3 SV変化率
; 3-3-1 SV変化率下降
917   LD<>    D2804 D2861  ; CH3 SV変化率下降_入力 / CH3_SV変化率下降_前回値
      SET     D2827.0
      MOV     D2804 D2861
; 3-3-2 SV変化率上昇
934   LD<>    D2805 D2862  ; CH3 SV変化率上昇_入力 / CH3_SV変化率上昇_前回値
      SET     D2828.0
      MOV     D2805 D2862
; 3-4 ﾌﾟﾘｾｯﾄﾏﾆｭｱﾙ
950   LD<>    D2806 D2863  ; CH3 プリセットマニュアル_入力 / CH3_プリセットマニュアル_前回値
      SET     D2829.0
      MOV     D2806 D2863
; 3-5 MV/マニュアル出力 AUT/MAN切換え
976   LD      D2852.1  ; CH3_AUTO_SW
      MOV     H7FFE D2807  ; CH3 MV/マニュアル出力_入力
979   LD      D2852.3  ; CH3_MAN_SW
      MOV     H7FFD D2807
982   LD<>    D2807 D2864  ; CH3 MV/マニュアル出力_入力 / CH3_MV/マニュアル出力_前回値
      OR      D2852.1  ; CH3_AUTO_SW
      OR      D2852.3  ; CH3_MAN_SW
      SET     D2830.0
      MOV     D2807 D2864
; 3-6 実行中No
998   LD<>    D2808 D2865  ; CH3 実行中No_入力 / CH3_実行中No_前回値
      SET     D2831.0
      MOV     D2808 D2865
; 3-7 実行中SV
1012  LD<>    D2809 D2866  ; CH3 実行中SV_入力 / CH3_実行中SV_前回値
      SET     D2832.0
      MOV     D2809 D2866
; 3-8 警報値1
1026  LD<>    D2810 D2867  ; CH3 実行中警報値1_入力 / CH3_実行中警報値1_前回値
      SET     D2833.0
      MOV     D2810 D2867
; 3-9 警報値2
1040  LD<>    D2811 D2868  ; CH3 実行中警報値2_入力 / CH3_実行中警報値2_前回値
      SET     D2834.0
      MOV     D2811 D2868
; 4-0 CH4
; 4-1 PV/SV/MVｽﾃｰﾀｽ抽出
; 4-1-1 4ﾋﾞｯﾄ分離
1075  LD      SM400  ; 常時ON
      DIS     D2912 D2954 K4  ; CH4 PV/SV/MVステータス[R](2進)_ / CH4_MVステータス0-3ﾋﾞｯﾄ
; 4-1-2 MVｽﾃｰﾀｽ
1089  LD      SM400  ; 常時ON
      MPS
      AND=    D2956 K0  ; CH4_MVステータス8-11ﾋﾞｯﾄ
      OUT     D2952.0  ; CH4_AUTO_Lamp
      MRD
      AND=    D2956 K1  ; CH4_MVステータス8-11ﾋﾞｯﾄ
      OUT     D2952.2  ; CH4_MAN_Lamp
      MRD
      AND=    D2956 K2  ; CH4_MVステータス8-11ﾋﾞｯﾄ
      OUT     D2953.0  ; CH4_A.T.ON_Lamp
      MRD
      AND=    D2957 K0  ; CH4_MVステータス12-15ﾋﾞｯﾄ
      OUT     D2951.0  ; CH4_RUN_Lamp
      MPP
      AND=    D2957 K1  ; CH4_MVステータス12-15ﾋﾞｯﾄ
      OUT     D2951.2  ; CH4_READY_Lamp
; 4-2 PID書込み
; 4-2-1 P書込み
1133  LD<>    D2901 D2958  ; CH4 実行中P_入力 / CH4_実行中P_前回値
      SET     D2924.0
      MOV     D2901 D2958
; 4-2-2 I書込み
1148  LD<>    D2902 D2959  ; CH4 実行中I_入力 / CH4_実行中I_前回値
      SET     D2925.0
      MOV     D2902 D2959
; 4-2-3 D書込み
1163  LD<>    D2903 D2960  ; CH4 実行中D_入力 / CH4_実行中D_前回値
      SET     D2926.0
      MOV     D2903 D2960
; 4-3 SV変化率
; 4-3-1 SV変化率下降
1188  LD<>    D2904 D2961  ; CH4 SV変化率下降_入力 / CH4_SV変化率下降_前回値
      SET     D2927.0
      MOV     D2904 D2961
; 4-3-2 SV変化率上昇
1205  LD<>    D2905 D2962  ; CH4 SV変化率上昇_入力 / CH4_SV変化率上昇_前回値
      SET     D2928.0
      MOV     D2905 D2962
; 4-4 ﾌﾟﾘｾｯﾄﾏﾆｭｱﾙ
1221  LD<>    D2906 D2963  ; CH4 プリセットマニュアル_入力 / CH4_プリセットマニュアル_前回値
      SET     D2929.0
      MOV     D2906 D2963
; 4-5 MV/マニュアル出力 AUT/MAN切換え
1247  LD      D2952.1  ; CH4_AUTO_SW
      MOV     H7FFE D2907  ; CH4 MV/マニュアル出力_入力
1250  LD      D2952.3  ; CH4_MAN_SW
      MOV     H7FFD D2907
1253  LD<>    D2907 D2964  ; CH4 MV/マニュアル出力_入力 / CH4_MV/マニュアル出力_前回値
      OR      D2952.1  ; CH4_AUTO_SW
      OR      D2952.3  ; CH4_MAN_SW
      SET     D2930.0
      MOV     D2907 D2964
; 4-6 実行中No
1269  LD<>    D2908 D2965  ; CH4 実行中No_入力 / CH4_実行中No_前回値
      SET     D2931.0
      MOV     D2908 D2965
; 4-7 実行中SV
1283  LD<>    D2909 D2966  ; CH4 実行中SV_入力 / CH4_実行中SV_前回値
      SET     D2932.0
      MOV     D2909 D2966
; 4-8 警報値1
1297  LD<>    D2910 D2967  ; CH4 実行中警報値1_入力 / CH4_実行中警報値1_前回値
      SET     D2933.0
      MOV     D2910 D2967
; 4-9 警報値2
1311  LD<>    D2911 D2968  ; CH4 実行中警報値2_入力 / CH4_実行中警報値2_前回値
      SET     D2934.0
      MOV     D2911 D2968
1317  END
END_PROGRAM

PROGRAM 26_#6  // SB100
; 0-0 共通
; 0-1 RUN/READY切替
; 0-1-1 CH1 RUN/READY切替
31    LD      D3151.1  ; CH1_RUN_SW
      BRST    D3001 K0  ; CH別RUN/READY切換(2進)_入力
35    LD      D3151.3  ; CH1_READY_SW
      BSET    D3001 K0
; 0-1-2 CH2 RUN/READY切替
53    LD      D3251.1  ; CH2_RUN_SW
      BRST    D3001 K1
57    LD      D3251.3  ; CH2_READY_SW
      BSET    D3001 K1
; 0-1-3 CH3 RUN/READY切替
75    LD      D3351.1  ; CH3_RUN_SW
      BRST    D3001 K2
79    LD      D3351.3  ; CH3_READY_SW
      BSET    D3001 K2
; 0-1-4 CH4 RUN/READY切替
97    LD      D3451.1  ; CH4_RUN_SW
      BRST    D3001 K3
101   LD      D3451.3  ; CH4_READY_SW
      BSET    D3001 K3
; 0-1-5 RUN/READYﾄﾘｶﾞｰ
117   LD      D3151.1  ; CH1_RUN_SW
      OR      D3151.3  ; CH1_READY_SW
      OR      D3251.1  ; CH2_RUN_SW
      OR      D3251.3  ; CH2_READY_SW
      OR      D3351.1  ; CH3_RUN_SW
      OR      D3351.3  ; CH3_READY_SW
      OR      D3451.1  ; CH4_RUN_SW
      OR      D3451.3  ; CH4_READY_SW
      SET     D3005.0
; 0-2 ｵｰﾄﾁｭｰﾆﾝｸﾞ実行停止
; 0-2-1 CH1ｵｰﾄﾁｭｰﾆﾝｸﾞ
151   LD      D3153.1  ; CH1_A.T.ON_SW
      MOV     H101 D3002  ; オートチューニング(16進)_入力
154   LD      D3153.3  ; CH1_A.T.OFF_SW
      MOV     H100 D3002
; 0-2-2 CH2ｵｰﾄﾁｭｰﾆﾝｸﾞ
169   LD      D3253.1  ; CH2_A.T.ON_SW
      MOV     H201 D3002
172   LD      D3253.3  ; CH2_A.T.OFF_SW
      MOV     H200 D3002
; 0-2-3 CH3ｵｰﾄﾁｭｰﾆﾝｸﾞ
187   LD      D3353.1  ; CH3_A.T.ON_SW
      MOV     H301 D3002
190   LD      D3353.3  ; CH3_A.T.OFF_SW
      MOV     H300 D3002
; 0-2-4 CH4ｵｰﾄﾁｭｰﾆﾝｸﾞ
205   LD      D3453.1  ; CH4_A.T.ON_SW
      MOV     H401 D3002
208   LD      D3453.3  ; CH4_A.T.OFF_SW
      MOV     H400 D3002
; 0-2-5 ｵｰﾄﾁｭｰﾆﾝｸﾞﾄﾘｶﾞｰ
224   LD      D3153.1  ; CH1_A.T.ON_SW
      OR      D3153.3  ; CH1_A.T.OFF_SW
      OR      D3253.1  ; CH2_A.T.ON_SW
      OR      D3253.3  ; CH2_A.T.OFF_SW
      OR      D3353.1  ; CH3_A.T.ON_SW
      OR      D3353.3  ; CH3_A.T.OFF_SW
      OR      D3453.1  ; CH4_A.T.ON_SW
      OR      D3453.3  ; CH4_A.T.OFF_SW
      SET     D3006.0
; 1-0 CH1
; 1-1 PV/SV/MVｽﾃｰﾀｽ抽出
; 1-1-1 4ﾋﾞｯﾄ分離
262   LD      SM400  ; 常時ON
      DIS     D3112 D3154 K4  ; CH1 PV/SV/MVステータス[R](2進)_ / CH1_PVステータス0-3ﾋﾞｯﾄ
; 1-1-2 MVｽﾃｰﾀｽ
276   LD      SM400  ; 常時ON
      MPS
      AND=    D3156 K0  ; CH1_MVステータス8-11ﾋﾞｯﾄ
      OUT     D3152.0  ; CH1_AUTO_Lamp
      MRD
      AND=    D3156 K1  ; CH1_MVステータス8-11ﾋﾞｯﾄ
      OUT     D3152.2  ; CH1_MAN_Lamp
      MRD
      AND=    D3156 K2  ; CH1_MVステータス8-11ﾋﾞｯﾄ
      OUT     D3153.0  ; CH1_A.T.ON_Lamp
      MRD
      AND=    D3157 K0  ; CH1_RUN/READY12-15ﾋﾞｯﾄ
      OUT     D3151.0  ; CH1_RUN_Lamp
      MPP
      AND=    D3157 K1  ; CH1_RUN/READY12-15ﾋﾞｯﾄ
      OUT     D3151.2  ; CH1_READY_Lamp
; 1-2 PID書込み
; 1-2-1 P書込み
320   LD<>    D3101 D3158  ; CH1 実行中P_入力 / CH1_実行中P_前回値
      SET     D3124.0
      MOV     D3101 D3158
; 1-2-2 I書込み
335   LD<>    D3102 D3159  ; CH1 実行中I_入力 / CH1_実行中I_前回値
      SET     D3125.0
      MOV     D3102 D3159
; 1-2-3 D書込み
350   LD<>    D3103 D3160  ; CH1 実行中D_入力 / CH1_実行中D_前回値
      SET     D3126.0
      MOV     D3103 D3160
; 1-3 SV変化率
; 1-3-1 SV変化率下降
375   LD<>    D3104 D3161  ; CH1 SV変化率下降_入力 / CH1_SV変化率下降_前回値
      SET     D3127.0
      MOV     D3104 D3161
; 1-3-2 SV変化率上昇
392   LD<>    D3105 D3162  ; CH1 SV変化率上昇_入力 / CH1_SV変化率上昇_前回値
      SET     D3128.0
      MOV     D3105 D3162
; 1-4 ﾌﾟﾘｾｯﾄﾏﾆｭｱﾙ
408   LD<>    D3106 D3163  ; CH1 プリセットマニュアル_入力 / CH1_プリセットマニュアル_前回値
      SET     D3129.0
      MOV     D3106 D3163
; 1-5 MV/マニュアル出力 AUT/MAN切換え
434   LD      D3152.1  ; CH1_AUTO_SW
      MOV     H7FFE D3107  ; CH1 MV/マニュアル出力_入力
437   LD      D3152.3  ; CH1_MAN_SW
      MOV     H7FFD D3107
440   LD<>    D3107 D3164  ; CH1 MV/マニュアル出力_入力 / CH1_MV/マニュアル出力_前回値
      OR      D3152.1  ; CH1_AUTO_SW
      OR      D3152.3  ; CH1_MAN_SW
      SET     D3130.0
      MOV     D3107 D3164
; 1-6 実行中No
456   LD<>    D3108 D3165  ; CH1 実行中No_入力 / CH1_実行中No_前回値
      SET     D3131.0
      MOV     D3108 D3165
; 1-7 実行中SV
470   LD<>    D3109 D3166  ; CH1 実行中SV_入力 / CH1_実行中SV_前回値
      SET     D3132.0
      MOV     D3109 D3166
; 1-8 警報値1
484   LD<>    D3110 D3167  ; CH1 実行中警報値1_入力 / CH1_実行中警報値1_前回値
      SET     D3133.0
      MOV     D3110 D3167
; 1-9 警報値2
498   LD<>    D3111 D3168  ; CH1 実行中警報値2_入力 / CH1_実行中警報値2_前回値
      SET     D3134.0
      MOV     D3111 D3168
; 2-0 CH2
; 2-1 PV/SV/MVｽﾃｰﾀｽ抽出
; 2-1-1 4ﾋﾞｯﾄ分離
533   LD      SM400  ; 常時ON
      DIS     D3212 D3254 K4  ; CH2 PV/SV/MVステータス[R](2進)_ / CH2_MVステータス0-3ﾋﾞｯﾄ
; 2-1-2 MVｽﾃｰﾀｽ
547   LD      SM400  ; 常時ON
      MPS
      AND=    D3256 K0  ; CH2_MVステータス8-11ﾋﾞｯﾄ
      OUT     D3252.0  ; CH2_AUTO_Lamp
      MRD
      AND=    D3256 K1  ; CH2_MVステータス8-11ﾋﾞｯﾄ
      OUT     D3252.2  ; CH2_MAN_Lamp
      MRD
      AND=    D3256 K2  ; CH2_MVステータス8-11ﾋﾞｯﾄ
      OUT     D3253.0  ; CH2_A.T.ON_Lamp
      MRD
      AND=    D3257 K0  ; CH2_MVステータス12-15ﾋﾞｯﾄ
      OUT     D3251.0  ; CH2_RUN_Lamp
      MPP
      AND=    D3257 K1  ; CH2_MVステータス12-15ﾋﾞｯﾄ
      OUT     D3251.2  ; CH2_READY_Lamp
; 2-2 PID書込み
; 2-2-1 P書込み
591   LD<>    D3201 D3258  ; CH2 実行中P_入力 / CH2_実行中P_前回値
      SET     D3224.0
      MOV     D3201 D3258
; 2-2-2 I書込み
606   LD<>    D3202 D3259  ; CH2 実行中I_入力 / CH2_実行中I_前回値
      SET     D3225.0
      MOV     D3202 D3259
; 2-2-3 D書込み
621   LD<>    D3203 D3260  ; CH2 実行中D_入力 / CH2_実行中D_前回値
      SET     D3226.0
      MOV     D3203 D3260
; 2-3 SV変化率
; 2-3-1 SV変化率下降
646   LD<>    D3204 D3261  ; CH2 SV変化率下降_入力 / CH2_SV変化率下降_前回値
      SET     D3227.0
      MOV     D3204 D3261
; 2-3-2 SV変化率上昇
663   LD<>    D3205 D3262  ; CH2 SV変化率上昇_入力 / CH2_SV変化率上昇_前回値
      SET     D3228.0
      MOV     D3205 D3262
; 2-4 ﾌﾟﾘｾｯﾄﾏﾆｭｱﾙ
679   LD<>    D3206 D3263  ; CH2 プリセットマニュアル_入力 / CH2_プリセットマニュアル_前回値
      SET     D3229.0
      MOV     D3206 D3263
; 2-5 MV/マニュアル出力 AUT/MAN切換え
705   LD      D3252.1  ; CH2_AUTO_SW
      MOV     H7FFE D3207  ; CH2 MV/マニュアル出力_入力
708   LD      D3252.3  ; CH2_MAN_SW
      MOV     H7FFD D3207
711   LD<>    D3207 D3264  ; CH2 MV/マニュアル出力_入力 / CH2_MV/マニュアル出力_前回値
      OR      D3252.1  ; CH2_AUTO_SW
      OR      D3252.3  ; CH2_MAN_SW
      SET     D3230.0
      MOV     D3207 D3264
; 2-6 実行中No
727   LD<>    D3208 D3265  ; CH2 実行中No_入力 / CH2_実行中No_前回値
      SET     D3231.0
      MOV     D3208 D3265
; 2-7 実行中SV
741   LD<>    D3209 D3266  ; CH2 実行中SV_入力 / CH2_実行中SV_前回値
      SET     D3232.0
      MOV     D3209 D3266
; 2-8 警報値1
755   LD<>    D3210 D3267  ; CH2 実行中警報値1_入力 / CH2_実行中警報値1_前回値
      SET     D3233.0
      MOV     D3210 D3267
; 2-9 警報値2
769   LD<>    D3211 D3268  ; CH2 実行中警報値2_入力 / CH2_実行中警報値2_前回値
      SET     D3234.0
      MOV     D3211 D3268
; 3-0 CH3
; 3-1 PV/SV/MVｽﾃｰﾀｽ抽出
; 3-1-1 4ﾋﾞｯﾄ分離
804   LD      SM400  ; 常時ON
      DIS     D3312 D3354 K4  ; CH3 PV/SV/MVステータス[R](2進)_ / CH3_MVステータス0-3ﾋﾞｯﾄ
; 3-1-2 MVｽﾃｰﾀｽ
818   LD      SM400  ; 常時ON
      MPS
      AND=    D3356 K0  ; CH3_MVステータス8-11ﾋﾞｯﾄ
      OUT     D3352.0  ; CH3_AUTO_Lamp
      MRD
      AND=    D3356 K1  ; CH3_MVステータス8-11ﾋﾞｯﾄ
      OUT     D3352.2  ; CH3_MAN_Lamp
      MRD
      AND=    D3356 K2  ; CH3_MVステータス8-11ﾋﾞｯﾄ
      OUT     D3353.0  ; CH3_A.T.ON_Lamp
      MRD
      AND=    D3357 K0  ; CH3_MVステータス12-15ﾋﾞｯﾄ
      OUT     D3351.0  ; CH3_RUN_Lamp
      MPP
      AND=    D3357 K1  ; CH3_MVステータス12-15ﾋﾞｯﾄ
      OUT     D3351.2  ; CH3_READY_Lamp
; 3-2 PID書込み
; 3-2-1 P書込み
862   LD<>    D3301 D3358  ; CH3 実行中P_入力 / CH3_実行中P_前回値
      SET     D3324.0
      MOV     D3301 D3358
; 3-2-2 I書込み
877   LD<>    D3302 D3359  ; CH3 実行中I_入力 / CH3_実行中I_前回値
      SET     D3325.0
      MOV     D3302 D3359
; 3-2-3 D書込み
892   LD<>    D3303 D3360  ; CH3 実行中D_入力 / CH3_実行中D_前回値
      SET     D3326.0
      MOV     D3303 D3360
; 3-3 SV変化率
; 3-3-1 SV変化率下降
917   LD<>    D3304 D3361  ; CH3 SV変化率下降_入力 / CH3_SV変化率下降_前回値
      SET     D3327.0
      MOV     D3304 D3361
; 3-3-2 SV変化率上昇
934   LD<>    D3305 D3362  ; CH3 SV変化率上昇_入力 / CH3_SV変化率上昇_前回値
      SET     D3328.0
      MOV     D3305 D3362
; 3-4 ﾌﾟﾘｾｯﾄﾏﾆｭｱﾙ
950   LD<>    D3306 D3363  ; CH3 プリセットマニュアル_入力 / CH3_プリセットマニュアル_前回値
      SET     D3329.0
      MOV     D3306 D3363
; 3-5 MV/マニュアル出力 AUT/MAN切換え
976   LD      D3352.1  ; CH3_AUTO_SW
      MOV     H7FFE D3307  ; CH3 MV/マニュアル出力_入力
979   LD      D3352.3  ; CH3_MAN_SW
      MOV     H7FFD D3307
982   LD<>    D3307 D3364  ; CH3 MV/マニュアル出力_入力 / CH3_MV/マニュアル出力_前回値
      OR      D3352.1  ; CH3_AUTO_SW
      OR      D3352.3  ; CH3_MAN_SW
      SET     D3330.0
      MOV     D3307 D3364
; 3-6 実行中No
998   LD<>    D3308 D3365  ; CH3 実行中No_入力 / CH3_実行中No_前回値
      SET     D3331.0
      MOV     D3308 D3365
; 3-7 実行中SV
1012  LD<>    D3309 D3366  ; CH3 実行中SV_入力 / CH3_実行中SV_前回値
      SET     D3332.0
      MOV     D3309 D3366
; 3-8 警報値1
1026  LD<>    D3310 D3367  ; CH3 実行中警報値1_入力 / CH3_実行中警報値1_前回値
      SET     D3333.0
      MOV     D3310 D3367
; 3-9 警報値2
1040  LD<>    D3311 D3368  ; CH3 実行中警報値2_入力 / CH3_実行中警報値2_前回値
      SET     D3334.0
      MOV     D3311 D3368
; 4-0 CH4
; 4-1 PV/SV/MVｽﾃｰﾀｽ抽出
; 4-1-1 4ﾋﾞｯﾄ分離
1075  LD      SM400  ; 常時ON
      DIS     D3412 D3454 K4  ; CH4 PV/SV/MVステータス[R](2進)_ / CH4_MVステータス0-3ﾋﾞｯﾄ
; 4-1-2 MVｽﾃｰﾀｽ
1089  LD      SM400  ; 常時ON
      MPS
      AND=    D3456 K0  ; CH4_MVステータス8-11ﾋﾞｯﾄ
      OUT     D3452.0  ; CH4_AUTO_Lamp
      MRD
      AND=    D3456 K1  ; CH4_MVステータス8-11ﾋﾞｯﾄ
      OUT     D3452.2  ; CH4_MAN_Lamp
      MRD
      AND=    D3456 K2  ; CH4_MVステータス8-11ﾋﾞｯﾄ
      OUT     D3453.0  ; CH4_A.T.ON_Lamp
      MRD
      AND=    D3457 K0  ; CH4_MVステータス12-15ﾋﾞｯﾄ
      OUT     D3451.0  ; CH4_RUN_Lamp
      MPP
      AND=    D3457 K1  ; CH4_MVステータス12-15ﾋﾞｯﾄ
      OUT     D3451.2  ; CH4_READY_Lamp
; 4-2 PID書込み
; 4-2-1 P書込み
1133  LD<>    D3401 D3458  ; CH4 実行中P_入力 / CH4_実行中P_前回値
      SET     D3424.0
      MOV     D3401 D3458
; 4-2-2 I書込み
1148  LD<>    D3402 D3459  ; CH4 実行中I_入力 / CH4_実行中I_前回値
      SET     D3425.0
      MOV     D3402 D3459
; 4-2-3 D書込み
1163  LD<>    D3403 D3460  ; CH4 実行中D_入力 / CH4_実行中D_前回値
      SET     D3426.0
      MOV     D3403 D3460
; 4-3 SV変化率
; 4-3-1 SV変化率下降
1188  LD<>    D3404 D3461  ; CH4 SV変化率下降_入力 / CH4_SV変化率下降_前回値
      SET     D3427.0
      MOV     D3404 D3461
; 4-3-2 SV変化率上昇
1205  LD<>    D3405 D3462  ; CH4 SV変化率上昇_入力 / CH4_SV変化率上昇_前回値
      SET     D3428.0
      MOV     D3405 D3462
; 4-4 ﾌﾟﾘｾｯﾄﾏﾆｭｱﾙ
1221  LD<>    D3406 D3463  ; CH4 プリセットマニュアル_入力 / CH4_プリセットマニュアル_前回値
      SET     D3429.0
      MOV     D3406 D3463
; 4-5 MV/マニュアル出力 AUT/MAN切換え
1247  LD      D3452.1  ; CH4_AUTO_SW
      MOV     H7FFE D3407  ; CH4 MV/マニュアル出力_入力
1250  LD      D3452.3  ; CH4_MAN_SW
      MOV     H7FFD D3407
1253  LD<>    D3407 D3464  ; CH4 MV/マニュアル出力_入力 / CH4_MV/マニュアル出力_前回値
      OR      D3452.1  ; CH4_AUTO_SW
      OR      D3452.3  ; CH4_MAN_SW
      SET     D3430.0
      MOV     D3407 D3464
; 4-6 実行中No
1269  LD<>    D3408 D3465  ; CH4 実行中No_入力 / CH4_実行中No_前回値
      SET     D3431.0
      MOV     D3408 D3465
; 4-7 実行中SV
1283  LD<>    D3409 D3466  ; CH4 実行中SV_入力 / CH4_実行中SV_前回値
      SET     D3432.0
      MOV     D3409 D3466
; 4-8 警報値1
1297  LD<>    D3410 D3467  ; CH4 実行中警報値1_入力 / CH4_実行中警報値1_前回値
      SET     D3433.0
      MOV     D3410 D3467
; 4-9 警報値2
1311  LD<>    D3411 D3468  ; CH4 実行中警報値2_入力 / CH4_実行中警報値2_前回値
      SET     D3434.0
      MOV     D3411 D3468
1317  END
END_PROGRAM

PROGRAM 27_#7  // SB100
; 0-0 共通
; 0-1 RUN/READY切替
; 0-1-1 CH1 RUN/READY切替
31    LD      D3651.1  ; CH1_RUN_SW
      BRST    D3501 K0  ; CH別RUN/READY切換(2進)_入力
35    LD      D3651.3  ; CH1_READY_SW
      BSET    D3501 K0
; 0-1-2 CH2 RUN/READY切替
53    LD      D3751.1  ; CH2_RUN_SW
      BRST    D3501 K1
57    LD      D3751.3  ; CH2_READY_SW
      BSET    D3501 K1
; 0-1-3 CH3 RUN/READY切替
75    LD      D3851.1  ; CH3_RUN_SW
      BRST    D3501 K2
79    LD      D3851.3  ; CH3_READY_SW
      BSET    D3501 K2
; 0-1-4 CH4 RUN/READY切替
97    LD      D3951.1  ; CH4_RUN_SW
      BRST    D3501 K3
101   LD      D3951.3  ; CH4_READY_SW
      BSET    D3501 K3
; 0-1-5 RUN/READYﾄﾘｶﾞｰ
117   LD      D3651.1  ; CH1_RUN_SW
      OR      D3651.3  ; CH1_READY_SW
      OR      D3751.1  ; CH2_RUN_SW
      OR      D3751.3  ; CH2_READY_SW
      OR      D3851.1  ; CH3_RUN_SW
      OR      D3851.3  ; CH3_READY_SW
      OR      D3951.1  ; CH4_RUN_SW
      OR      D3951.3  ; CH4_READY_SW
      SET     D3505.0
; 0-2 ｵｰﾄﾁｭｰﾆﾝｸﾞ実行停止
; 0-2-1 CH1ｵｰﾄﾁｭｰﾆﾝｸﾞ
151   LD      D3653.1  ; CH1_A.T.ON_SW
      MOV     H101 D3502  ; オートチューニング(16進)_入力
154   LD      D3653.3  ; CH1_A.T.OFF_SW
      MOV     H100 D3502
; 0-2-2 CH2ｵｰﾄﾁｭｰﾆﾝｸﾞ
169   LD      D3753.1  ; CH2_A.T.ON_SW
      MOV     H201 D3502
172   LD      D3753.3  ; CH2_A.T.OFF_SW
      MOV     H200 D3502
; 0-2-3 CH3ｵｰﾄﾁｭｰﾆﾝｸﾞ
187   LD      D3853.1  ; CH3_A.T.ON_SW
      MOV     H301 D3502
190   LD      D3853.3  ; CH3_A.T.OFF_SW
      MOV     H300 D3502
; 0-2-4 CH4ｵｰﾄﾁｭｰﾆﾝｸﾞ
205   LD      D3953.1  ; CH4_A.T.ON_SW
      MOV     H401 D3502
208   LD      D3953.3  ; CH4_A.T.OFF_SW
      MOV     H400 D3502
; 0-2-5 ｵｰﾄﾁｭｰﾆﾝｸﾞﾄﾘｶﾞｰ
224   LD      D3653.1  ; CH1_A.T.ON_SW
      OR      D3653.3  ; CH1_A.T.OFF_SW
      OR      D3753.1  ; CH2_A.T.ON_SW
      OR      D3753.3  ; CH2_A.T.OFF_SW
      OR      D3853.1  ; CH3_A.T.ON_SW
      OR      D3853.3  ; CH3_A.T.OFF_SW
      OR      D3953.1  ; CH4_A.T.ON_SW
      OR      D3953.3  ; CH4_A.T.OFF_SW
      SET     D3506.0
; 1-0 CH1
; 1-1 PV/SV/MVｽﾃｰﾀｽ抽出
; 1-1-1 4ﾋﾞｯﾄ分離
262   LD      SM400  ; 常時ON
      DIS     D3612 D3654 K4  ; CH1 PV/SV/MVステータス[R](2進)_ / CH1_PVステータス0-3ﾋﾞｯﾄ
; 1-1-2 MVｽﾃｰﾀｽ
276   LD      SM400  ; 常時ON
      MPS
      AND=    D3656 K0  ; CH1_MVステータス8-11ﾋﾞｯﾄ
      OUT     D3652.0  ; CH1_AUTO_Lamp
      MRD
      AND=    D3656 K1  ; CH1_MVステータス8-11ﾋﾞｯﾄ
      OUT     D3652.2  ; CH1_MAN_Lamp
      MRD
      AND=    D3656 K2  ; CH1_MVステータス8-11ﾋﾞｯﾄ
      OUT     D3653.0  ; CH1_A.T.ON_Lamp
      MRD
      AND=    D3657 K0  ; CH1_RUN/READY12-15ﾋﾞｯﾄ
      OUT     D3651.0  ; CH1_RUN_Lamp
      MPP
      AND=    D3657 K1  ; CH1_RUN/READY12-15ﾋﾞｯﾄ
      OUT     D3651.2  ; CH1_READY_Lamp
; 1-2 PID書込み
; 1-2-1 P書込み
320   LD<>    D3601 D3658  ; CH1 実行中P_入力 / CH1_実行中P_前回値
      SET     D3624.0
      MOV     D3601 D3658
; 1-2-2 I書込み
335   LD<>    D3602 D3659  ; CH1 実行中I_入力 / CH1_実行中I_前回値
      SET     D3625.0
      MOV     D3602 D3659
; 1-2-3 D書込み
350   LD<>    D3603 D3660  ; CH1 実行中D_入力 / CH1_実行中D_前回値
      SET     D3626.0
      MOV     D3603 D3660
; 1-3 SV変化率
; 1-3-1 SV変化率下降
375   LD<>    D3604 D3661  ; CH1 SV変化率下降_入力 / CH1_SV変化率下降_前回値
      SET     D3627.0
      MOV     D3604 D3661
; 1-3-2 SV変化率上昇
392   LD<>    D3605 D3662  ; CH1 SV変化率上昇_入力 / CH1_SV変化率上昇_前回値
      SET     D3628.0
      MOV     D3605 D3662
; 1-4 ﾌﾟﾘｾｯﾄﾏﾆｭｱﾙ
408   LD<>    D3606 D3663  ; CH1 プリセットマニュアル_入力 / CH1_プリセットマニュアル_前回値
      SET     D3629.0
      MOV     D3606 D3663
; 1-5 MV/マニュアル出力 AUT/MAN切換え
434   LD      D3652.1  ; CH1_AUTO_SW
      MOV     H7FFE D3607  ; CH1 MV/マニュアル出力_入力
437   LD      D3652.3  ; CH1_MAN_SW
      MOV     H7FFD D3607
440   LD<>    D3607 D3664  ; CH1 MV/マニュアル出力_入力 / CH1_MV/マニュアル出力_前回値
      OR      D3652.1  ; CH1_AUTO_SW
      OR      D3652.3  ; CH1_MAN_SW
      SET     D3630.0
      MOV     D3607 D3664
; 1-6 実行中No
456   LD<>    D3608 D3665  ; CH1 実行中No_入力 / CH1_実行中No_前回値
      SET     D3631.0
      MOV     D3608 D3665
; 1-7 実行中SV
470   LD<>    D3609 D3666  ; CH1 実行中SV_入力 / CH1_実行中SV_前回値
      SET     D3632.0
      MOV     D3609 D3666
; 1-8 警報値1
484   LD<>    D3610 D3667  ; CH1 実行中警報値1_入力 / CH1_実行中警報値1_前回値
      SET     D3633.0
      MOV     D3610 D3667
; 1-9 警報値2
498   LD<>    D3611 D3668  ; CH1 実行中警報値2_入力 / CH1_実行中警報値2_前回値
      SET     D3634.0
      MOV     D3611 D3668
; 2-0 CH2
; 2-1 PV/SV/MVｽﾃｰﾀｽ抽出
; 2-1-1 4ﾋﾞｯﾄ分離
533   LD      SM400  ; 常時ON
      DIS     D3712 D3754 K4  ; CH2 PV/SV/MVステータス[R](2進)_ / CH2_MVステータス0-3ﾋﾞｯﾄ
; 2-1-2 MVｽﾃｰﾀｽ
547   LD      SM400  ; 常時ON
      MPS
      AND=    D3756 K0  ; CH2_MVステータス8-11ﾋﾞｯﾄ
      OUT     D3752.0  ; CH2_AUTO_Lamp
      MRD
      AND=    D3756 K1  ; CH2_MVステータス8-11ﾋﾞｯﾄ
      OUT     D3752.2  ; CH2_MAN_Lamp
      MRD
      AND=    D3756 K2  ; CH2_MVステータス8-11ﾋﾞｯﾄ
      OUT     D3753.0  ; CH2_A.T.ON_Lamp
      MRD
      AND=    D3757 K0  ; CH2_MVステータス12-15ﾋﾞｯﾄ
      OUT     D3751.0  ; CH2_RUN_Lamp
      MPP
      AND=    D3757 K1  ; CH2_MVステータス12-15ﾋﾞｯﾄ
      OUT     D3751.2  ; CH2_READY_Lamp
; 2-2 PID書込み
; 2-2-1 P書込み
591   LD<>    D3701 D3758  ; CH2 実行中P_入力 / CH2_実行中P_前回値
      SET     D3724.0
      MOV     D3701 D3758
; 2-2-2 I書込み
606   LD<>    D3702 D3759  ; CH2 実行中I_入力 / CH2_実行中I_前回値
      SET     D3725.0
      MOV     D3702 D3759
; 2-2-3 D書込み
621   LD<>    D3703 D3760  ; CH2 実行中D_入力 / CH2_実行中D_前回値
      SET     D3726.0
      MOV     D3703 D3760
; 2-3 SV変化率
; 2-3-1 SV変化率下降
646   LD<>    D3704 D3761  ; CH2 SV変化率下降_入力 / CH2_SV変化率下降_前回値
      SET     D3727.0
      MOV     D3704 D3761
; 2-3-2 SV変化率上昇
663   LD<>    D3705 D3762  ; CH2 SV変化率上昇_入力 / CH2_SV変化率上昇_前回値
      SET     D3728.0
      MOV     D3705 D3762
; 2-4 ﾌﾟﾘｾｯﾄﾏﾆｭｱﾙ
679   LD<>    D3706 D3763  ; CH2 プリセットマニュアル_入力 / CH2_プリセットマニュアル_前回値
      SET     D3729.0
      MOV     D3706 D3763
; 2-5 MV/マニュアル出力 AUT/MAN切換え
705   LD      D3752.1  ; CH2_AUTO_SW
      MOV     H7FFE D3707  ; CH2 MV/マニュアル出力_入力
708   LD      D3752.3  ; CH2_MAN_SW
      MOV     H7FFD D3707
711   LD<>    D3707 D3764  ; CH2 MV/マニュアル出力_入力 / CH2_MV/マニュアル出力_前回値
      OR      D3752.1  ; CH2_AUTO_SW
      OR      D3752.3  ; CH2_MAN_SW
      SET     D3730.0
      MOV     D3707 D3764
; 2-6 実行中No
727   LD<>    D3708 D3765  ; CH2 実行中No_入力 / CH2_実行中No_前回値
      SET     D3731.0
      MOV     D3708 D3765
; 2-7 実行中SV
741   LD<>    D3709 D3766  ; CH2 実行中SV_入力 / CH2_実行中SV_前回値
      SET     D3732.0
      MOV     D3709 D3766
; 2-8 警報値1
755   LD<>    D3710 D3767  ; CH2 実行中警報値1_入力 / CH2_実行中警報値1_前回値
      SET     D3733.0
      MOV     D3710 D3767
; 2-9 警報値2
769   LD<>    D3711 D3768  ; CH2 実行中警報値2_入力 / CH2_実行中警報値2_前回値
      SET     D3734.0
      MOV     D3711 D3768
; 3-0 CH3
; 3-1 PV/SV/MVｽﾃｰﾀｽ抽出
; 3-1-1 4ﾋﾞｯﾄ分離
804   LD      SM400  ; 常時ON
      DIS     D3812 D3854 K4  ; CH3 PV/SV/MVステータス[R](2進)_ / CH3_MVステータス0-3ﾋﾞｯﾄ
; 3-1-2 MVｽﾃｰﾀｽ
818   LD      SM400  ; 常時ON
      MPS
      AND=    D3856 K0  ; CH3_MVステータス8-11ﾋﾞｯﾄ
      OUT     D3852.0  ; CH3_AUTO_Lamp
      MRD
      AND=    D3856 K1  ; CH3_MVステータス8-11ﾋﾞｯﾄ
      OUT     D3852.2  ; CH3_MAN_Lamp
      MRD
      AND=    D3856 K2  ; CH3_MVステータス8-11ﾋﾞｯﾄ
      OUT     D3853.0  ; CH3_A.T.ON_Lamp
      MRD
      AND=    D3857 K0  ; CH3_MVステータス12-15ﾋﾞｯﾄ
      OUT     D3851.0  ; CH3_RUN_Lamp
      MPP
      AND=    D3857 K1  ; CH3_MVステータス12-15ﾋﾞｯﾄ
      OUT     D3851.2  ; CH3_READY_Lamp
; 3-2 PID書込み
; 3-2-1 P書込み
862   LD<>    D3801 D3858  ; CH3 実行中P_入力 / CH3_実行中P_前回値
      SET     D3824.0
      MOV     D3801 D3858
; 3-2-2 I書込み
877   LD<>    D3802 D3859  ; CH3 実行中I_入力 / CH3_実行中I_前回値
      SET     D3825.0
      MOV     D3802 D3859
; 3-2-3 D書込み
892   LD<>    D3803 D3860  ; CH3 実行中D_入力 / CH3_実行中D_前回値
      SET     D3826.0
      MOV     D3803 D3860
; 3-3 SV変化率
; 3-3-1 SV変化率下降
917   LD<>    D3804 D3861  ; CH3 SV変化率下降_入力 / CH3_SV変化率下降_前回値
      SET     D3827.0
      MOV     D3804 D3861
; 3-3-2 SV変化率上昇
934   LD<>    D3805 D3862  ; CH3 SV変化率上昇_入力 / CH3_SV変化率上昇_前回値
      SET     D3828.0
      MOV     D3805 D3862
; 3-4 ﾌﾟﾘｾｯﾄﾏﾆｭｱﾙ
950   LD<>    D3806 D3863  ; CH3 プリセットマニュアル_入力 / CH3_プリセットマニュアル_前回値
      SET     D3829.0
      MOV     D3806 D3863
; 3-5 MV/マニュアル出力 AUT/MAN切換え
976   LD      D3852.1  ; CH3_AUTO_SW
      MOV     H7FFE D3807  ; CH3 MV/マニュアル出力_入力
979   LD      D3852.3  ; CH3_MAN_SW
      MOV     H7FFD D3807
982   LD<>    D3807 D3864  ; CH3 MV/マニュアル出力_入力 / CH3_MV/マニュアル出力_前回値
      OR      D3852.1  ; CH3_AUTO_SW
      OR      D3852.3  ; CH3_MAN_SW
      SET     D3830.0
      MOV     D3807 D3864
; 3-6 実行中No
998   LD<>    D3808 D3865  ; CH3 実行中No_入力 / CH3_実行中No_前回値
      SET     D3831.0
      MOV     D3808 D3865
; 3-7 実行中SV
1012  LD<>    D3809 D3866  ; CH3 実行中SV_入力 / CH3_実行中SV_前回値
      SET     D3832.0
      MOV     D3809 D3866
; 3-8 警報値1
1026  LD<>    D3810 D3867  ; CH3 実行中警報値1_入力 / CH3_実行中警報値1_前回値
      SET     D3833.0
      MOV     D3810 D3867
; 3-9 警報値2
1040  LD<>    D3811 D3868  ; CH3 実行中警報値2_入力 / CH3_実行中警報値2_前回値
      SET     D3834.0
      MOV     D3811 D3868
; 4-0 CH4
; 4-1 PV/SV/MVｽﾃｰﾀｽ抽出
; 4-1-1 4ﾋﾞｯﾄ分離
1075  LD      SM400  ; 常時ON
      DIS     D3912 D3954 K4  ; CH4 PV/SV/MVステータス[R](2進)_ / CH4_MVステータス0-3ﾋﾞｯﾄ
; 4-1-2 MVｽﾃｰﾀｽ
1089  LD      SM400  ; 常時ON
      MPS
      AND=    D3956 K0  ; CH4_MVステータス8-11ﾋﾞｯﾄ
      OUT     D3952.0  ; CH4_AUTO_Lamp
      MRD
      AND=    D3956 K1  ; CH4_MVステータス8-11ﾋﾞｯﾄ
      OUT     D3952.2  ; CH4_MAN_Lamp
      MRD
      AND=    D3956 K2  ; CH4_MVステータス8-11ﾋﾞｯﾄ
      OUT     D3953.0  ; CH4_A.T.ON_Lamp
      MRD
      AND=    D3957 K0  ; CH4_MVステータス12-15ﾋﾞｯﾄ
      OUT     D3951.0  ; CH4_RUN_Lamp
      MPP
      AND=    D3957 K1  ; CH4_MVステータス12-15ﾋﾞｯﾄ
      OUT     D3951.2  ; CH4_READY_Lamp
; 4-2 PID書込み
; 4-2-1 P書込み
1133  LD<>    D3901 D3958  ; CH4 実行中P_入力 / CH4_実行中P_前回値
      SET     D3924.0
      MOV     D3901 D3958
; 4-2-2 I書込み
1148  LD<>    D3902 D3959  ; CH4 実行中I_入力 / CH4_実行中I_前回値
      SET     D3925.0
      MOV     D3902 D3959
; 4-2-3 D書込み
1163  LD<>    D3903 D3960  ; CH4 実行中D_入力 / CH4_実行中D_前回値
      SET     D3926.0
      MOV     D3903 D3960
; 4-3 SV変化率
; 4-3-1 SV変化率下降
1188  LD<>    D3904 D3961  ; CH4 SV変化率下降_入力 / CH4_SV変化率下降_前回値
      SET     D3927.0
      MOV     D3904 D3961
; 4-3-2 SV変化率上昇
1205  LD<>    D3905 D3962  ; CH4 SV変化率上昇_入力 / CH4_SV変化率上昇_前回値
      SET     D3928.0
      MOV     D3905 D3962
; 4-4 ﾌﾟﾘｾｯﾄﾏﾆｭｱﾙ
1221  LD<>    D3906 D3963  ; CH4 プリセットマニュアル_入力 / CH4_プリセットマニュアル_前回値
      SET     D3929.0
      MOV     D3906 D3963
; 4-5 MV/マニュアル出力 AUT/MAN切換え
1247  LD      D3952.1  ; CH4_AUTO_SW
      MOV     H7FFE D3907  ; CH4 MV/マニュアル出力_入力
1250  LD      D3952.3  ; CH4_MAN_SW
      MOV     H7FFD D3907
1253  LD<>    D3907 D3964  ; CH4 MV/マニュアル出力_入力 / CH4_MV/マニュアル出力_前回値
      OR      D3952.1  ; CH4_AUTO_SW
      OR      D3952.3  ; CH4_MAN_SW
      SET     D3930.0
      MOV     D3907 D3964
; 4-6 実行中No
1269  LD<>    D3908 D3965  ; CH4 実行中No_入力 / CH4_実行中No_前回値
      SET     D3931.0
      MOV     D3908 D3965
; 4-7 実行中SV
1283  LD<>    D3909 D3966  ; CH4 実行中SV_入力 / CH4_実行中SV_前回値
      SET     D3932.0
      MOV     D3909 D3966
; 4-8 警報値1
1297  LD<>    D3910 D3967  ; CH4 実行中警報値1_入力 / CH4_実行中警報値1_前回値
      SET     D3933.0
      MOV     D3910 D3967
; 4-9 警報値2
1311  LD<>    D3911 D3968  ; CH4 実行中警報値2_入力 / CH4_実行中警報値2_前回値
      SET     D3934.0
      MOV     D3911 D3968
1317  END
END_PROGRAM

PROGRAM 28_#8  // SB100
; 0-0 共通
; 0-1 RUN/READY切替
; 0-1-1 CH1 RUN/READY切替
31    LD      D4151.1  ; CH1_RUN_SW
      BRST    D4001 K0  ; CH別RUN/READY切換(2進)_入力
35    LD      D4151.3  ; CH1_READY_SW
      BSET    D4001 K0
; 0-1-2 CH2 RUN/READY切替
53    LD      D4251.1  ; CH2_RUN_SW
      BRST    D4001 K1
57    LD      D4251.3  ; CH2_READY_SW
      BSET    D4001 K1
; 0-1-3 CH3 RUN/READY切替
75    LD      D4351.1  ; CH3_RUN_SW
      BRST    D4001 K2
79    LD      D4351.3  ; CH3_READY_SW
      BSET    D4001 K2
; 0-1-4 CH4 RUN/READY切替
97    LD      D4451.1  ; CH4_RUN_SW
      BRST    D4001 K3
101   LD      D4451.3  ; CH4_READY_SW
      BSET    D4001 K3
; 0-1-5 RUN/READYﾄﾘｶﾞｰ
117   LD      D4151.1  ; CH1_RUN_SW
      OR      D4151.3  ; CH1_READY_SW
      OR      D4251.1  ; CH2_RUN_SW
      OR      D4251.3  ; CH2_READY_SW
      OR      D4351.1  ; CH3_RUN_SW
      OR      D4351.3  ; CH3_READY_SW
      OR      D4451.1  ; CH4_RUN_SW
      OR      D4451.3  ; CH4_READY_SW
      SET     D4005.0
; 0-2 ｵｰﾄﾁｭｰﾆﾝｸﾞ実行停止
; 0-2-1 CH1ｵｰﾄﾁｭｰﾆﾝｸﾞ
151   LD      D4153.1  ; CH1_A.T.ON_SW
      MOV     H101 D4002  ; オートチューニング(16進)_入力
154   LD      D4153.3  ; CH1_A.T.OFF_SW
      MOV     H100 D4002
; 0-2-2 CH2ｵｰﾄﾁｭｰﾆﾝｸﾞ
169   LD      D4253.1  ; CH2_A.T.ON_SW
      MOV     H201 D4002
172   LD      D4253.3  ; CH2_A.T.OFF_SW
      MOV     H200 D4002
; 0-2-3 CH3ｵｰﾄﾁｭｰﾆﾝｸﾞ
187   LD      D4353.1  ; CH3_A.T.ON_SW
      MOV     H301 D4002
190   LD      D4353.3  ; CH3_A.T.OFF_SW
      MOV     H300 D4002
; 0-2-4 CH4ｵｰﾄﾁｭｰﾆﾝｸﾞ
205   LD      D4453.1  ; CH4_A.T.ON_SW
      MOV     H401 D4002
208   LD      D4453.3  ; CH4_A.T.OFF_SW
      MOV     H400 D4002
; 0-2-5 ｵｰﾄﾁｭｰﾆﾝｸﾞﾄﾘｶﾞｰ
224   LD      D4153.1  ; CH1_A.T.ON_SW
      OR      D4153.3  ; CH1_A.T.OFF_SW
      OR      D4253.1  ; CH2_A.T.ON_SW
      OR      D4253.3  ; CH2_A.T.OFF_SW
      OR      D4353.1  ; CH3_A.T.ON_SW
      OR      D4353.3  ; CH3_A.T.OFF_SW
      OR      D4453.1  ; CH4_A.T.ON_SW
      OR      D4453.3  ; CH4_A.T.OFF_SW
      SET     D4006.0
; 1-0 CH1
; 1-1 PV/SV/MVｽﾃｰﾀｽ抽出
; 1-1-1 4ﾋﾞｯﾄ分離
262   LD      SM400  ; 常時ON
      DIS     D4112 D4154 K4  ; CH1 PV/SV/MVステータス[R](2進)_ / CH1_PVステータス0-3ﾋﾞｯﾄ
; 1-1-2 MVｽﾃｰﾀｽ
276   LD      SM400  ; 常時ON
      MPS
      AND=    D4156 K0  ; CH1_MVステータス8-11ﾋﾞｯﾄ
      OUT     D4152.0  ; CH1_AUTO_Lamp
      MRD
      AND=    D4156 K1  ; CH1_MVステータス8-11ﾋﾞｯﾄ
      OUT     D4152.2  ; CH1_MAN_Lamp
      MRD
      AND=    D4156 K2  ; CH1_MVステータス8-11ﾋﾞｯﾄ
      OUT     D4153.0  ; CH1_A.T.ON_Lamp
      MRD
      AND=    D4157 K0  ; CH1_RUN/READY12-15ﾋﾞｯﾄ
      OUT     D4151.0  ; CH1_RUN_Lamp
      MPP
      AND=    D4157 K1  ; CH1_RUN/READY12-15ﾋﾞｯﾄ
      OUT     D4151.2  ; CH1_READY_Lamp
; 1-2 PID書込み
; 1-2-1 P書込み
320   LD<>    D4101 D4158  ; CH1 実行中P_入力 / CH1_実行中P_前回値
      SET     D4124.0
      MOV     D4101 D4158
; 1-2-2 I書込み
335   LD<>    D4102 D4159  ; CH1 実行中I_入力 / CH1_実行中I_前回値
      SET     D4125.0
      MOV     D4102 D4159
; 1-2-3 D書込み
350   LD<>    D4103 D4160  ; CH1 実行中D_入力 / CH1_実行中D_前回値
      SET     D4126.0
      MOV     D4103 D4160
; 1-3 SV変化率
; 1-3-1 SV変化率下降
375   LD<>    D4104 D4161  ; CH1 SV変化率下降_入力 / CH1_SV変化率下降_前回値
      SET     D4127.0
      MOV     D4104 D4161
; 1-3-2 SV変化率上昇
392   LD<>    D4105 D4162  ; CH1 SV変化率上昇_入力 / CH1_SV変化率上昇_前回値
      SET     D4128.0
      MOV     D4105 D4162
; 1-4 ﾌﾟﾘｾｯﾄﾏﾆｭｱﾙ
408   LD<>    D4106 D4163  ; CH1 プリセットマニュアル_入力 / CH1_プリセットマニュアル_前回値
      SET     D4129.0
      MOV     D4106 D4163
; 1-5 MV/マニュアル出力 AUT/MAN切換え
434   LD      D4152.1  ; CH1_AUTO_SW
      MOV     H7FFE D4107  ; CH1 MV/マニュアル出力_入力
437   LD      D4152.3  ; CH1_MAN_SW
      MOV     H7FFD D4107
440   LD<>    D4107 D4164  ; CH1 MV/マニュアル出力_入力 / CH1_MV/マニュアル出力_前回値
      OR      D4152.1  ; CH1_AUTO_SW
      OR      D4152.3  ; CH1_MAN_SW
      SET     D4130.0
      MOV     D4107 D4164
; 1-6 実行中No
456   LD<>    D4108 D4165  ; CH1 実行中No_入力 / CH1_実行中No_前回値
      SET     D4131.0
      MOV     D4108 D4165
; 1-7 実行中SV
470   LD<>    D4109 D4166  ; CH1 実行中SV_入力 / CH1_実行中SV_前回値
      SET     D4132.0
      MOV     D4109 D4166
; 1-8 警報値1
484   LD<>    D4110 D4167  ; CH1 実行中警報値1_入力 / CH1_実行中警報値1_前回値
      SET     D4133.0
      MOV     D4110 D4167
; 1-9 警報値2
498   LD<>    D4111 D4168  ; CH1 実行中警報値2_入力 / CH1_実行中警報値2_前回値
      SET     D4134.0
      MOV     D4111 D4168
; 2-0 CH2
; 2-1 PV/SV/MVｽﾃｰﾀｽ抽出
; 2-1-1 4ﾋﾞｯﾄ分離
533   LD      SM400  ; 常時ON
      DIS     D4212 D4254 K4  ; CH2 PV/SV/MVステータス[R](2進)_ / CH2_MVステータス0-3ﾋﾞｯﾄ
; 2-1-2 MVｽﾃｰﾀｽ
547   LD      SM400  ; 常時ON
      MPS
      AND=    D4256 K0  ; CH2_MVステータス8-11ﾋﾞｯﾄ
      OUT     D4252.0  ; CH2_AUTO_Lamp
      MRD
      AND=    D4256 K1  ; CH2_MVステータス8-11ﾋﾞｯﾄ
      OUT     D4252.2  ; CH2_MAN_Lamp
      MRD
      AND=    D4256 K2  ; CH2_MVステータス8-11ﾋﾞｯﾄ
      OUT     D4253.0  ; CH2_A.T.ON_Lamp
      MRD
      AND=    D4257 K0  ; CH2_MVステータス12-15ﾋﾞｯﾄ
      OUT     D4251.0  ; CH2_RUN_Lamp
      MPP
      AND=    D4257 K1  ; CH2_MVステータス12-15ﾋﾞｯﾄ
      OUT     D4251.2  ; CH2_READY_Lamp
; 2-2 PID書込み
; 2-2-1 P書込み
591   LD<>    D4201 D4258  ; CH2 実行中P_入力 / CH2_実行中P_前回値
      SET     D4224.0
      MOV     D4201 D4258
; 2-2-2 I書込み
606   LD<>    D4202 D4259  ; CH2 実行中I_入力 / CH2_実行中I_前回値
      SET     D4225.0
      MOV     D4202 D4259
; 2-2-3 D書込み
621   LD<>    D4203 D4260  ; CH2 実行中D_入力 / CH2_実行中D_前回値
      SET     D4226.0
      MOV     D4203 D4260
; 2-3 SV変化率
; 2-3-1 SV変化率下降
646   LD<>    D4204 D4261  ; CH2 SV変化率下降_入力 / CH2_SV変化率下降_前回値
      SET     D4227.0
      MOV     D4204 D4261
; 2-3-2 SV変化率上昇
663   LD<>    D4205 D4262  ; CH2 SV変化率上昇_入力 / CH2_SV変化率上昇_前回値
      SET     D4228.0
      MOV     D4205 D4262
; 2-4 ﾌﾟﾘｾｯﾄﾏﾆｭｱﾙ
679   LD<>    D4206 D4263  ; CH2 プリセットマニュアル_入力 / CH2_プリセットマニュアル_前回値
      SET     D4229.0
      MOV     D4206 D4263
; 2-5 MV/マニュアル出力 AUT/MAN切換え
705   LD      D4252.1  ; CH2_AUTO_SW
      MOV     H7FFE D4207  ; CH2 MV/マニュアル出力_入力
708   LD      D4252.3  ; CH2_MAN_SW
      MOV     H7FFD D4207
711   LD<>    D4207 D4264  ; CH2 MV/マニュアル出力_入力 / CH2_MV/マニュアル出力_前回値
      OR      D4252.1  ; CH2_AUTO_SW
      OR      D4252.3  ; CH2_MAN_SW
      SET     D4230.0
      MOV     D4207 D4264
; 2-6 実行中No
727   LD<>    D4208 D4265  ; CH2 実行中No_入力 / CH2_実行中No_前回値
      SET     D4231.0
      MOV     D4208 D4265
; 2-7 実行中SV
741   LD<>    D4209 D4266  ; CH2 実行中SV_入力 / CH2_実行中SV_前回値
      SET     D4232.0
      MOV     D4209 D4266
; 2-8 警報値1
755   LD<>    D4210 D4267  ; CH2 実行中警報値1_入力 / CH2_実行中警報値1_前回値
      SET     D4233.0
      MOV     D4210 D4267
; 2-9 警報値2
769   LD<>    D4211 D4268  ; CH2 実行中警報値2_入力 / CH2_実行中警報値2_前回値
      SET     D4234.0
      MOV     D4211 D4268
; 3-0 CH3
; 3-1 PV/SV/MVｽﾃｰﾀｽ抽出
; 3-1-1 4ﾋﾞｯﾄ分離
804   LD      SM400  ; 常時ON
      DIS     D4312 D4354 K4  ; CH3 PV/SV/MVステータス[R](2進)_ / CH3_MVステータス0-3ﾋﾞｯﾄ
; 3-1-2 MVｽﾃｰﾀｽ
818   LD      SM400  ; 常時ON
      MPS
      AND=    D4356 K0  ; CH3_MVステータス8-11ﾋﾞｯﾄ
      OUT     D4352.0  ; CH3_AUTO_Lamp
      MRD
      AND=    D4356 K1  ; CH3_MVステータス8-11ﾋﾞｯﾄ
      OUT     D4352.2  ; CH3_MAN_Lamp
      MRD
      AND=    D4356 K2  ; CH3_MVステータス8-11ﾋﾞｯﾄ
      OUT     D4353.0  ; CH3_A.T.ON_Lamp
      MRD
      AND=    D4357 K0  ; CH3_MVステータス12-15ﾋﾞｯﾄ
      OUT     D4351.0  ; CH3_RUN_Lamp
      MPP
      AND=    D4357 K1  ; CH3_MVステータス12-15ﾋﾞｯﾄ
      OUT     D4351.2  ; CH3_READY_Lamp
; 3-2 PID書込み
; 3-2-1 P書込み
862   LD<>    D4301 D4358  ; CH3 実行中P_入力 / CH3_実行中P_前回値
      SET     D4324.0
      MOV     D4301 D4358
; 3-2-2 I書込み
877   LD<>    D4302 D4359  ; CH3 実行中I_入力 / CH3_実行中I_前回値
      SET     D4325.0
      MOV     D4302 D4359
; 3-2-3 D書込み
892   LD<>    D4303 D4360  ; CH3 実行中D_入力 / CH3_実行中D_前回値
      SET     D4326.0
      MOV     D4303 D4360
; 3-3 SV変化率
; 3-3-1 SV変化率下降
917   LD<>    D4304 D4361  ; CH3 SV変化率下降_入力 / CH3_SV変化率下降_前回値
      SET     D4327.0
      MOV     D4304 D4361
; 3-3-2 SV変化率上昇
934   LD<>    D4305 D4362  ; CH3 SV変化率上昇_入力 / CH3_SV変化率上昇_前回値
      SET     D4328.0
      MOV     D4305 D4362
; 3-4 ﾌﾟﾘｾｯﾄﾏﾆｭｱﾙ
950   LD<>    D4306 D4363  ; CH3 プリセットマニュアル_入力 / CH3_プリセットマニュアル_前回値
      SET     D4329.0
      MOV     D4306 D4363
; 3-5 MV/マニュアル出力 AUT/MAN切換え
976   LD      D4352.1  ; CH3_AUTO_SW
      MOV     H7FFE D4307  ; CH3 MV/マニュアル出力_入力
979   LD      D4352.3  ; CH3_MAN_SW
      MOV     H7FFD D4307
982   LD<>    D4307 D4364  ; CH3 MV/マニュアル出力_入力 / CH3_MV/マニュアル出力_前回値
      OR      D4352.1  ; CH3_AUTO_SW
      OR      D4352.3  ; CH3_MAN_SW
      SET     D4330.0
      MOV     D4307 D4364
; 3-6 実行中No
998   LD<>    D4308 D4365  ; CH3 実行中No_入力 / CH3_実行中No_前回値
      SET     D4331.0
      MOV     D4308 D4365
; 3-7 実行中SV
1012  LD<>    D4309 D4366  ; CH3 実行中SV_入力 / CH3_実行中SV_前回値
      SET     D4332.0
      MOV     D4309 D4366
; 3-8 警報値1
1026  LD<>    D4310 D4367  ; CH3 実行中警報値1_入力 / CH3_実行中警報値1_前回値
      SET     D4333.0
      MOV     D4310 D4367
; 3-9 警報値2
1040  LD<>    D4311 D4368  ; CH3 実行中警報値2_入力 / CH3_実行中警報値2_前回値
      SET     D4334.0
      MOV     D4311 D4368
; 4-0 CH4
; 4-1 PV/SV/MVｽﾃｰﾀｽ抽出
; 4-1-1 4ﾋﾞｯﾄ分離
1075  LD      SM400  ; 常時ON
      DIS     D4412 D4454 K4  ; CH4 PV/SV/MVステータス[R](2進)_ / CH4_MVステータス0-3ﾋﾞｯﾄ
; 4-1-2 MVｽﾃｰﾀｽ
1089  LD      SM400  ; 常時ON
      MPS
      AND=    D4456 K0  ; CH4_MVステータス8-11ﾋﾞｯﾄ
      OUT     D4452.0  ; CH4_AUTO_Lamp
      MRD
      AND=    D4456 K1  ; CH4_MVステータス8-11ﾋﾞｯﾄ
      OUT     D4452.2  ; CH4_MAN_Lamp
      MRD
      AND=    D4456 K2  ; CH4_MVステータス8-11ﾋﾞｯﾄ
      OUT     D4453.0  ; CH4_A.T.ON_Lamp
      MRD
      AND=    D4457 K0  ; CH4_MVステータス12-15ﾋﾞｯﾄ
      OUT     D4451.0  ; CH4_RUN_Lamp
      MPP
      AND=    D4457 K1  ; CH4_MVステータス12-15ﾋﾞｯﾄ
      OUT     D4451.2  ; CH4_READY_Lamp
; 4-2 PID書込み
; 4-2-1 P書込み
1133  LD<>    D4401 D4458  ; CH4 実行中P_入力 / CH4_実行中P_前回値
      SET     D4424.0
      MOV     D4401 D4458
; 4-2-2 I書込み
1148  LD<>    D4402 D4459  ; CH4 実行中I_入力 / CH4_実行中I_前回値
      SET     D4425.0
      MOV     D4402 D4459
; 4-2-3 D書込み
1163  LD<>    D4403 D4460  ; CH4 実行中D_入力 / CH4_実行中D_前回値
      SET     D4426.0
      MOV     D4403 D4460
; 4-3 SV変化率
; 4-3-1 SV変化率下降
1188  LD<>    D4404 D4461  ; CH4 SV変化率下降_入力 / CH4_SV変化率下降_前回値
      SET     D4427.0
      MOV     D4404 D4461
; 4-3-2 SV変化率上昇
1205  LD<>    D4405 D4462  ; CH4 SV変化率上昇_入力 / CH4_SV変化率上昇_前回値
      SET     D4428.0
      MOV     D4405 D4462
; 4-4 ﾌﾟﾘｾｯﾄﾏﾆｭｱﾙ
1221  LD<>    D4406 D4463  ; CH4 プリセットマニュアル_入力 / CH4_プリセットマニュアル_前回値
      SET     D4429.0
      MOV     D4406 D4463
; 4-5 MV/マニュアル出力 AUT/MAN切換え
1247  LD      D4452.1  ; CH4_AUTO_SW
      MOV     H7FFE D4407  ; CH4 MV/マニュアル出力_入力
1250  LD      D4452.3  ; CH4_MAN_SW
      MOV     H7FFD D4407
1253  LD<>    D4407 D4464  ; CH4 MV/マニュアル出力_入力 / CH4_MV/マニュアル出力_前回値
      OR      D4452.1  ; CH4_AUTO_SW
      OR      D4452.3  ; CH4_MAN_SW
      SET     D4430.0
      MOV     D4407 D4464
; 4-6 実行中No
1269  LD<>    D4408 D4465  ; CH4 実行中No_入力 / CH4_実行中No_前回値
      SET     D4431.0
      MOV     D4408 D4465
; 4-7 実行中SV
1283  LD<>    D4409 D4466  ; CH4 実行中SV_入力 / CH4_実行中SV_前回値
      SET     D4432.0
      MOV     D4409 D4466
; 4-8 警報値1
1297  LD<>    D4410 D4467  ; CH4 実行中警報値1_入力 / CH4_実行中警報値1_前回値
      SET     D4433.0
      MOV     D4410 D4467
; 4-9 警報値2
1311  LD<>    D4411 D4468  ; CH4 実行中警報値2_入力 / CH4_実行中警報値2_前回値
      SET     D4434.0
      MOV     D4411 D4468
1317  END
END_PROGRAM

PROGRAM 29_#9  // SB100
; 0-0 共通
; 0-1 RUN/READY切替
; 0-1-1 CH1 RUN/READY切替
31    LD      D4651.1  ; CH1_RUN_SW
      BRST    D4501 K0  ; CH別RUN/READY切換(2進)_入力
35    LD      D4651.3  ; CH1_READY_SW
      BSET    D4501 K0
; 0-1-2 CH2 RUN/READY切替
53    LD      D4751.1  ; CH2_RUN_SW
      BRST    D4501 K1
57    LD      D4751.3  ; CH2_READY_SW
      BSET    D4501 K1
; 0-1-3 CH3 RUN/READY切替
75    LD      D4851.1  ; CH3_RUN_SW
      BRST    D4501 K2
79    LD      D4851.3  ; CH3_READY_SW
      BSET    D4501 K2
; 0-1-4 CH4 RUN/READY切替
97    LD      D4951.1  ; CH4_RUN_SW
      BRST    D4501 K3
101   LD      D4951.3  ; CH4_READY_SW
      BSET    D4501 K3
; 0-1-5 RUN/READYﾄﾘｶﾞｰ
117   LD      D4651.1  ; CH1_RUN_SW
      OR      D4651.3  ; CH1_READY_SW
      OR      D4751.1  ; CH2_RUN_SW
      OR      D4751.3  ; CH2_READY_SW
      OR      D4851.1  ; CH3_RUN_SW
      OR      D4851.3  ; CH3_READY_SW
      OR      D4951.1  ; CH4_RUN_SW
      OR      D4951.3  ; CH4_READY_SW
      SET     D4505.0
; 0-2 ｵｰﾄﾁｭｰﾆﾝｸﾞ実行停止
; 0-2-1 CH1ｵｰﾄﾁｭｰﾆﾝｸﾞ
151   LD      D4653.1  ; CH1_A.T.ON_SW
      MOV     H101 D4502  ; オートチューニング(16進)_入力
154   LD      D4653.3  ; CH1_A.T.OFF_SW
      MOV     H100 D4502
; 0-2-2 CH2ｵｰﾄﾁｭｰﾆﾝｸﾞ
169   LD      D4753.1  ; CH2_A.T.ON_SW
      MOV     H201 D4502
172   LD      D4753.3  ; CH2_A.T.OFF_SW
      MOV     H200 D4502
; 0-2-3 CH3ｵｰﾄﾁｭｰﾆﾝｸﾞ
187   LD      D4853.1  ; CH3_A.T.ON_SW
      MOV     H301 D4502
190   LD      D4853.3  ; CH3_A.T.OFF_SW
      MOV     H300 D4502
; 0-2-4 CH4ｵｰﾄﾁｭｰﾆﾝｸﾞ
205   LD      D4953.1  ; CH4_A.T.ON_SW
      MOV     H401 D4502
208   LD      D4953.3  ; CH4_A.T.OFF_SW
      MOV     H400 D4502
; 0-2-5 ｵｰﾄﾁｭｰﾆﾝｸﾞﾄﾘｶﾞｰ
224   LD      D4653.1  ; CH1_A.T.ON_SW
      OR      D4653.3  ; CH1_A.T.OFF_SW
      OR      D4753.1  ; CH2_A.T.ON_SW
      OR      D4753.3  ; CH2_A.T.OFF_SW
      OR      D4853.1  ; CH3_A.T.ON_SW
      OR      D4853.3  ; CH3_A.T.OFF_SW
      OR      D4953.1  ; CH4_A.T.ON_SW
      OR      D4953.3  ; CH4_A.T.OFF_SW
      SET     D4506.0
; 1-0 CH1
; 1-1 PV/SV/MVｽﾃｰﾀｽ抽出
; 1-1-1 4ﾋﾞｯﾄ分離
262   LD      SM400  ; 常時ON
      DIS     D4612 D4654 K4  ; CH1 PV/SV/MVステータス[R](2進)_ / CH1_PVステータス0-3ﾋﾞｯﾄ
; 1-1-2 MVｽﾃｰﾀｽ
276   LD      SM400  ; 常時ON
      MPS
      AND=    D4656 K0  ; CH1_MVステータス8-11ﾋﾞｯﾄ
      OUT     D4652.0  ; CH1_AUTO_Lamp
      MRD
      AND=    D4656 K1  ; CH1_MVステータス8-11ﾋﾞｯﾄ
      OUT     D4652.2  ; CH1_MAN_Lamp
      MRD
      AND=    D4656 K2  ; CH1_MVステータス8-11ﾋﾞｯﾄ
      OUT     D4653.0  ; CH1_A.T.ON_Lamp
      MRD
      AND=    D4657 K0  ; CH1_RUN/READY12-15ﾋﾞｯﾄ
      OUT     D4651.0  ; CH1_RUN_Lamp
      MPP
      AND=    D4657 K1  ; CH1_RUN/READY12-15ﾋﾞｯﾄ
      OUT     D4651.2  ; CH1_READY_Lamp
; 1-2 PID書込み
; 1-2-1 P書込み
320   LD<>    D4601 D4658  ; CH1 実行中P_入力 / CH1_実行中P_前回値
      SET     D4624.0
      MOV     D4601 D4658
; 1-2-2 I書込み
335   LD<>    D4602 D4659  ; CH1 実行中I_入力 / CH1_実行中I_前回値
      SET     D4625.0
      MOV     D4602 D4659
; 1-2-3 D書込み
350   LD<>    D4603 D4660  ; CH1 実行中D_入力 / CH1_実行中D_前回値
      SET     D4626.0
      MOV     D4603 D4660
; 1-3 SV変化率
; 1-3-1 SV変化率下降
375   LD<>    D4604 D4661  ; CH1 SV変化率下降_入力 / CH1_SV変化率下降_前回値
      SET     D4627.0
      MOV     D4604 D4661
; 1-3-2 SV変化率上昇
392   LD<>    D4605 D4662  ; CH1 SV変化率上昇_入力 / CH1_SV変化率上昇_前回値
      SET     D4628.0
      MOV     D4605 D4662
; 1-4 ﾌﾟﾘｾｯﾄﾏﾆｭｱﾙ
408   LD<>    D4606 D4663  ; CH1 プリセットマニュアル_入力 / CH1_プリセットマニュアル_前回値
      SET     D4629.0
      MOV     D4606 D4663
; 1-5 MV/マニュアル出力 AUT/MAN切換え
434   LD      D4652.1  ; CH1_AUTO_SW
      MOV     H7FFE D4607  ; CH1 MV/マニュアル出力_入力
437   LD      D4652.3  ; CH1_MAN_SW
      MOV     H7FFD D4607
440   LD<>    D4607 D4664  ; CH1 MV/マニュアル出力_入力 / CH1_MV/マニュアル出力_前回値
      OR      D4652.1  ; CH1_AUTO_SW
      OR      D4652.3  ; CH1_MAN_SW
      SET     D4630.0
      MOV     D4607 D4664
; 1-6 実行中No
456   LD<>    D4608 D4665  ; CH1 実行中No_入力 / CH1_実行中No_前回値
      SET     D4631.0
      MOV     D4608 D4665
; 1-7 実行中SV
470   LD<>    D4609 D4666  ; CH1 実行中SV_入力 / CH1_実行中SV_前回値
      SET     D4632.0
      MOV     D4609 D4666
; 1-8 警報値1
484   LD<>    D4610 D4667  ; CH1 実行中警報値1_入力 / CH1_実行中警報値1_前回値
      SET     D4633.0
      MOV     D4610 D4667
; 1-9 警報値2
498   LD<>    D4611 D4668  ; CH1 実行中警報値2_入力 / CH1_実行中警報値2_前回値
      SET     D4634.0
      MOV     D4611 D4668
; 2-0 CH2
; 2-1 PV/SV/MVｽﾃｰﾀｽ抽出
; 2-1-1 4ﾋﾞｯﾄ分離
533   LD      SM400  ; 常時ON
      DIS     D4712 D4754 K4  ; CH2 PV/SV/MVステータス[R](2進)_ / CH2_MVステータス0-3ﾋﾞｯﾄ
; 2-1-2 MVｽﾃｰﾀｽ
547   LD      SM400  ; 常時ON
      MPS
      AND=    D4756 K0  ; CH2_MVステータス8-11ﾋﾞｯﾄ
      OUT     D4752.0  ; CH2_AUTO_Lamp
      MRD
      AND=    D4756 K1  ; CH2_MVステータス8-11ﾋﾞｯﾄ
      OUT     D4752.2  ; CH2_MAN_Lamp
      MRD
      AND=    D4756 K2  ; CH2_MVステータス8-11ﾋﾞｯﾄ
      OUT     D4753.0  ; CH2_A.T.ON_Lamp
      MRD
      AND=    D4757 K0  ; CH2_MVステータス12-15ﾋﾞｯﾄ
      OUT     D4751.0  ; CH2_RUN_Lamp
      MPP
      AND=    D4757 K1  ; CH2_MVステータス12-15ﾋﾞｯﾄ
      OUT     D4751.2  ; CH2_READY_Lamp
; 2-2 PID書込み
; 2-2-1 P書込み
591   LD<>    D4701 D4758  ; CH2 実行中P_入力 / CH2_実行中P_前回値
      SET     D4724.0
      MOV     D4701 D4758
; 2-2-2 I書込み
606   LD<>    D4702 D4759  ; CH2 実行中I_入力 / CH2_実行中I_前回値
      SET     D4725.0
      MOV     D4702 D4759
; 2-2-3 D書込み
621   LD<>    D4703 D4760  ; CH2 実行中D_入力 / CH2_実行中D_前回値
      SET     D4726.0
      MOV     D4703 D4760
; 2-3 SV変化率
; 2-3-1 SV変化率下降
646   LD<>    D4704 D4761  ; CH2 SV変化率下降_入力 / CH2_SV変化率下降_前回値
      SET     D4727.0
      MOV     D4704 D4761
; 2-3-2 SV変化率上昇
663   LD<>    D4705 D4762  ; CH2 SV変化率上昇_入力 / CH2_SV変化率上昇_前回値
      SET     D4728.0
      MOV     D4705 D4762
; 2-4 ﾌﾟﾘｾｯﾄﾏﾆｭｱﾙ
679   LD<>    D4706 D4763  ; CH2 プリセットマニュアル_入力 / CH2_プリセットマニュアル_前回値
      SET     D4729.0
      MOV     D4706 D4763
; 2-5 MV/マニュアル出力 AUT/MAN切換え
705   LD      D4752.1  ; CH2_AUTO_SW
      MOV     H7FFE D4707  ; CH2 MV/マニュアル出力_入力
708   LD      D4752.3  ; CH2_MAN_SW
      MOV     H7FFD D4707
711   LD<>    D4707 D4764  ; CH2 MV/マニュアル出力_入力 / CH2_MV/マニュアル出力_前回値
      OR      D4752.1  ; CH2_AUTO_SW
      OR      D4752.3  ; CH2_MAN_SW
      SET     D4730.0
      MOV     D4707 D4764
; 2-6 実行中No
727   LD<>    D4708 D4765  ; CH2 実行中No_入力 / CH2_実行中No_前回値
      SET     D4731.0
      MOV     D4708 D4765
; 2-7 実行中SV
741   LD<>    D4709 D4766  ; CH2 実行中SV_入力 / CH2_実行中SV_前回値
      SET     D4732.0
      MOV     D4709 D4766
; 2-8 警報値1
755   LD<>    D4710 D4767  ; CH2 実行中警報値1_入力 / CH2_実行中警報値1_前回値
      SET     D4733.0
      MOV     D4710 D4767
; 2-9 警報値2
769   LD<>    D4711 D4768  ; CH2 実行中警報値2_入力 / CH2_実行中警報値2_前回値
      SET     D4734.0
      MOV     D4711 D4768
; 3-0 CH3
; 3-1 PV/SV/MVｽﾃｰﾀｽ抽出
; 3-1-1 4ﾋﾞｯﾄ分離
804   LD      SM400  ; 常時ON
      DIS     D4812 D4854 K4  ; CH3 PV/SV/MVステータス[R](2進)_ / CH3_MVステータス0-3ﾋﾞｯﾄ
; 3-1-2 MVｽﾃｰﾀｽ
818   LD      SM400  ; 常時ON
      MPS
      AND=    D4856 K0  ; CH3_MVステータス8-11ﾋﾞｯﾄ
      OUT     D4852.0  ; CH3_AUTO_Lamp
      MRD
      AND=    D4856 K1  ; CH3_MVステータス8-11ﾋﾞｯﾄ
      OUT     D4852.2  ; CH3_MAN_Lamp
      MRD
      AND=    D4856 K2  ; CH3_MVステータス8-11ﾋﾞｯﾄ
      OUT     D4853.0  ; CH3_A.T.ON_Lamp
      MRD
      AND=    D4857 K0  ; CH3_MVステータス12-15ﾋﾞｯﾄ
      OUT     D4851.0  ; CH3_RUN_Lamp
      MPP
      AND=    D4857 K1  ; CH3_MVステータス12-15ﾋﾞｯﾄ
      OUT     D4851.2  ; CH3_READY_Lamp
; 3-2 PID書込み
; 3-2-1 P書込み
862   LD<>    D4801 D4858  ; CH3 実行中P_入力 / CH3_実行中P_前回値
      SET     D4824.0
      MOV     D4801 D4858
; 3-2-2 I書込み
877   LD<>    D4802 D4859  ; CH3 実行中I_入力 / CH3_実行中I_前回値
      SET     D4825.0
      MOV     D4802 D4859
; 3-2-3 D書込み
892   LD<>    D4803 D4860  ; CH3 実行中D_入力 / CH3_実行中D_前回値
      SET     D4826.0
      MOV     D4803 D4860
; 3-3 SV変化率
; 3-3-1 SV変化率下降
917   LD<>    D4804 D4861  ; CH3 SV変化率下降_入力 / CH3_SV変化率下降_前回値
      SET     D4827.0
      MOV     D4804 D4861
; 3-3-2 SV変化率上昇
934   LD<>    D4805 D4862  ; CH3 SV変化率上昇_入力 / CH3_SV変化率上昇_前回値
      SET     D4828.0
      MOV     D4805 D4862
; 3-4 ﾌﾟﾘｾｯﾄﾏﾆｭｱﾙ
950   LD<>    D4806 D4863  ; CH3 プリセットマニュアル_入力 / CH3_プリセットマニュアル_前回値
      SET     D4829.0
      MOV     D4806 D4863
; 3-5 MV/マニュアル出力 AUT/MAN切換え
976   LD      D4852.1  ; CH3_AUTO_SW
      MOV     H7FFE D4807  ; CH3 MV/マニュアル出力_入力
979   LD      D4852.3  ; CH3_MAN_SW
      MOV     H7FFD D4807
982   LD<>    D4807 D4864  ; CH3 MV/マニュアル出力_入力 / CH3_MV/マニュアル出力_前回値
      OR      D4852.1  ; CH3_AUTO_SW
      OR      D4852.3  ; CH3_MAN_SW
      SET     D4830.0
      MOV     D4807 D4864
; 3-6 実行中No
998   LD<>    D4808 D4865  ; CH3 実行中No_入力 / CH3_実行中No_前回値
      SET     D4831.0
      MOV     D4808 D4865
; 3-7 実行中SV
1012  LD<>    D4809 D4866  ; CH3 実行中SV_入力 / CH3_実行中SV_前回値
      SET     D4832.0
      MOV     D4809 D4866
; 3-8 警報値1
1026  LD<>    D4810 D4867  ; CH3 実行中警報値1_入力 / CH3_実行中警報値1_前回値
      SET     D4833.0
      MOV     D4810 D4867
; 3-9 警報値2
1040  LD<>    D4811 D4868  ; CH3 実行中警報値2_入力 / CH3_実行中警報値2_前回値
      SET     D4834.0
      MOV     D4811 D4868
; 4-0 CH4
; 4-1 PV/SV/MVｽﾃｰﾀｽ抽出
; 4-1-1 4ﾋﾞｯﾄ分離
1075  LD      SM400  ; 常時ON
      DIS     D4912 D4954 K4  ; CH4 PV/SV/MVステータス[R](2進)_ / CH4_MVステータス0-3ﾋﾞｯﾄ
; 4-1-2 MVｽﾃｰﾀｽ
1089  LD      SM400  ; 常時ON
      MPS
      AND=    D4956 K0  ; CH4_MVステータス8-11ﾋﾞｯﾄ
      OUT     D4952.0  ; CH4_AUTO_Lamp
      MRD
      AND=    D4956 K1  ; CH4_MVステータス8-11ﾋﾞｯﾄ
      OUT     D4952.2  ; CH4_MAN_Lamp
      MRD
      AND=    D4956 K2  ; CH4_MVステータス8-11ﾋﾞｯﾄ
      OUT     D4953.0  ; CH4_A.T.ON_Lamp
      MRD
      AND=    D4957 K0  ; CH4_MVステータス12-15ﾋﾞｯﾄ
      OUT     D4951.0  ; CH4_RUN_Lamp
      MPP
      AND=    D4957 K1  ; CH4_MVステータス12-15ﾋﾞｯﾄ
      OUT     D4951.2  ; CH4_READY_Lamp
; 4-2 PID書込み
; 4-2-1 P書込み
1133  LD<>    D4901 D4958  ; CH4 実行中P_入力 / CH4_実行中P_前回値
      SET     D4924.0
      MOV     D4901 D4958
; 4-2-2 I書込み
1148  LD<>    D4902 D4959  ; CH4 実行中I_入力 / CH4_実行中I_前回値
      SET     D4925.0
      MOV     D4902 D4959
; 4-2-3 D書込み
1163  LD<>    D4903 D4960  ; CH4 実行中D_入力 / CH4_実行中D_前回値
      SET     D4926.0
      MOV     D4903 D4960
; 4-3 SV変化率
; 4-3-1 SV変化率下降
1188  LD<>    D4904 D4961  ; CH4 SV変化率下降_入力 / CH4_SV変化率下降_前回値
      SET     D4927.0
      MOV     D4904 D4961
; 4-3-2 SV変化率上昇
1205  LD<>    D4905 D4962  ; CH4 SV変化率上昇_入力 / CH4_SV変化率上昇_前回値
      SET     D4928.0
      MOV     D4905 D4962
; 4-4 ﾌﾟﾘｾｯﾄﾏﾆｭｱﾙ
1221  LD<>    D4906 D4963  ; CH4 プリセットマニュアル_入力 / CH4_プリセットマニュアル_前回値
      SET     D4929.0
      MOV     D4906 D4963
; 4-5 MV/マニュアル出力 AUT/MAN切換え
1247  LD      D4952.1  ; CH4_AUTO_SW
      MOV     H7FFE D4907  ; CH4 MV/マニュアル出力_入力
1250  LD      D4952.3  ; CH4_MAN_SW
      MOV     H7FFD D4907
1253  LD<>    D4907 D4964  ; CH4 MV/マニュアル出力_入力 / CH4_MV/マニュアル出力_前回値
      OR      D4952.1  ; CH4_AUTO_SW
      OR      D4952.3  ; CH4_MAN_SW
      SET     D4930.0
      MOV     D4907 D4964
; 4-6 実行中No
1269  LD<>    D4908 D4965  ; CH4 実行中No_入力 / CH4_実行中No_前回値
      SET     D4931.0
      MOV     D4908 D4965
; 4-7 実行中SV
1283  LD<>    D4909 D4966  ; CH4 実行中SV_入力 / CH4_実行中SV_前回値
      SET     D4932.0
      MOV     D4909 D4966
; 4-8 警報値1
1297  LD<>    D4910 D4967  ; CH4 実行中警報値1_入力 / CH4_実行中警報値1_前回値
      SET     D4933.0
      MOV     D4910 D4967
; 4-9 警報値2
1311  LD<>    D4911 D4968  ; CH4 実行中警報値2_入力 / CH4_実行中警報値2_前回値
      SET     D4934.0
      MOV     D4911 D4968
1317  END
END_PROGRAM

PROGRAM 01_SB  // Initial
; 1 SBｲﾆｼｬﾙ共通
9     LDF     L0  ; SB初期ﾊﾟﾗﾒｰﾀ書込み(0:書込/1:-)
      BKRSTP  L2 K8  ; #2SB初期ﾊﾟﾗﾒｰﾀ書込み(0:書込/1:-)
15    LD      L2  ; #2SB初期ﾊﾟﾗﾒｰﾀ書込み(0:書込/1:-)
      AND     L3  ; #3SB初期ﾊﾟﾗﾒｰﾀ書込み(0:書込/1:-)
      AND     L4  ; #4SB初期ﾊﾟﾗﾒｰﾀ書込み(0:書込/1:-)
      AND     L5  ; #5SB初期ﾊﾟﾗﾒｰﾀ書込み(0:書込/1:-)
      AND     L6  ; #6SB初期ﾊﾟﾗﾒｰﾀ書込み(0:書込/1:-)
      AND     L7  ; #7SB初期ﾊﾟﾗﾒｰﾀ書込み(0:書込/1:-)
      AND     L8  ; #8SB初期ﾊﾟﾗﾒｰﾀ書込み(0:書込/1:-)
      AND     L9  ; #9SB初期ﾊﾟﾗﾒｰﾀ書込み(0:書込/1:-)
      SET     L0  ; SB初期ﾊﾟﾗﾒｰﾀ書込み(0:書込/1:-)
24    END
END_PROGRAM

PROGRAM 03_#3  // SB_Initial
VAR
  __IST_06e6d74c13384652 : I+ST_06e6d74c13384652;
END_VAR
; FB BLK START I+ST_06e6d74c13384652(__IST_06e6d74c13384652)
; 1 SB初期化ﾊﾟﾗﾒｰﾀ設定
13    LDI     L3  ; #3SB初期ﾊﾟﾗﾒｰﾀ書込み(0:書込/1:-)
      OUT     ___IST_EN_IN
; FB START
; FB_NAME I+ST_06e6d74c13384652
; INSTANCE_NAME __IST_06e6d74c13384652
; FB IN_B:__IST_EN_IN
; FB OUT___IST_EN_OUT:B
; FB END
; FB BLK END
; 2 実行中No書込み
33    LDI     L3  ; #3SB初期ﾊﾟﾗﾒｰﾀ書込み(0:書込/1:-)
      SET     D1631.0
      SET     D1731.0
      SET     D1831.0
      SET     D1931.0
; 3 実行中No書込み後待機
51    LDI     L3  ; #3SB初期ﾊﾟﾗﾒｰﾀ書込み(0:書込/1:-)
      OR      M13  ; #3SB_初期化ｷｰ保持(PID書込用)
      ANI     T3  ; #3SB PID書込みT
      OUT     M13  ; #3SB_初期化ｷｰ保持(PID書込用)
      OUT     T3 K10  ; #3SB PID書込みT
; 4 実行中No以外書込み
71    LDP     T3  ; #3SB PID書込みT
      FMOV    K1 D1624 K7  ; CH1 実行中P_ﾄﾘｶﾞｰ
      FMOV    K1 D1632 K3  ; CH1 実行中SV_ﾄﾘｶﾞｰ
81    LDP     T3  ; #3SB PID書込みT
      FMOV    K1 D1724 K7  ; CH2 実行中P_ﾄﾘｶﾞｰ
      FMOV    K1 D1732 K3  ; CH2 実行中SV_ﾄﾘｶﾞｰ
91    LDP     T3  ; #3SB PID書込みT
      FMOV    K1 D1824 K7  ; CH3 実行中P_ﾄﾘｶﾞｰ
      FMOV    K1 D1832 K3  ; CH3 実行中SV_ﾄﾘｶﾞｰ
101   LDP     T3  ; #3SB PID書込みT
      FMOV    K1 D1924 K7  ; CH4 実行中P_ﾄﾘｶﾞｰ
      FMOV    K1 D1932 K3  ; CH4 実行中SV_ﾄﾘｶﾞｰ
; 5 初期化ﾌﾗｸﾞｾｯﾄ
121   LD      SM400  ; 常時ON
      SET     L3  ; #3SB初期ﾊﾟﾗﾒｰﾀ書込み(0:書込/1:-)
123   END
END_PROGRAM

FUNCTION_BLOCK I+ST_06e6d74c13384652
VAR_INPUT
  __IST_EN_IN : BOOL;
END_VAR
VAR_OUTPUT
  __IST_EN_OUT : BOOL;
END_VAR
(* IST HEADER START *)
IF NOT __IST_EN_IN THEN __IST_EN_OUT:=FALSE; RETURN; END_IF;
(* VERSION=1:TYPE=STB *)
(* IST HEADER END *)
D1601:=50;		(*CH1 実行中P*)
D1602:=60;		(*CH1 実行中I*)
D1603:=30;		(*CH1 実行中D*)
D1604:=0;		(*CH1 SV変化率下降*)
D1605:=0;		(*CH1 SV変化率上昇*)
D1606:=0;		(*CH1 プリセットマニュアル*)
D1608:=1;		(*CH1 実行中No*)
D1609:=234;		(*CH1 実行中SV*)
D1610:=30000;	(*CH1 実行中警報値1*)
D1611:=-30000;	(*CH1 実行中警報値2*)
D1701:=50;		(*CH2 実行中P*)
D1702:=60;		(*CH2 実行中I*)
D1703:=30;		(*CH2 実行中D*)
D1704:=0;		(*CH2 SV変化率下降*)
D1705:=0;		(*CH2 SV変化率上昇*)
D1706:=0;		(*CH2 プリセットマニュアル*)
D1708:=1;		(*CH2 実行中No*)
D1709:=234;		(*CH2 実行中SV*)
D1710:=30000;	(*CH2 実行中警報値1*)
D1711:=-30000;	(*CH2 実行中警報値2*)
D1801:=50;		(*CH3 実行中P*)
D1802:=60;		(*CH3 実行中I*)
D1803:=30;		(*CH3 実行中D*)
D1804:=0;		(*CH3 SV変化率下降*)
D1805:=0;		(*CH3 SV変化率上昇*)
D1806:=0;		(*CH3 プリセットマニュアル*)
D1808:=1;		(*CH3 実行中No*)
D1809:=234;		(*CH3 実行中SV*)
D1810:=30000;	(*CH3 実行中警報値1*)
D1811:=-30000;	(*CH3 実行中警報値2*)
D1901:=50;		(*CH4 実行中P*)
D1902:=60;		(*CH4 実行中I*)
D1903:=30;		(*CH4 実行中D*)
D1904:=0;		(*CH4 SV変化率下降*)
D1905:=0;		(*CH4 SV変化率上昇*)
D1906:=0;		(*CH4 プリセットマニュアル*)
D1908:=1;		(*CH4 実行中No*)
D1909:=234;		(*CH4 実行中SV*)
D1910:=30000;	(*CH4 実行中警報値1*)
D1911:=-30000;(*CH4 実行中警報値2*)
END_FUNCTION_BLOCK

PROGRAM 04_#4  // SB_Initial
VAR
  __IST_3ca76adcf7d949a6 : I+ST_3ca76adcf7d949a6;
END_VAR
; FB BLK START I+ST_3ca76adcf7d949a6(__IST_3ca76adcf7d949a6)
; 1 SB初期化ﾊﾟﾗﾒｰﾀ設定
13    LDI     L4  ; #4SB初期ﾊﾟﾗﾒｰﾀ書込み(0:書込/1:-)
      OUT     ___IST_EN_IN
; FB START
; FB_NAME I+ST_3ca76adcf7d949a6
; INSTANCE_NAME __IST_3ca76adcf7d949a6
; FB IN_B:__IST_EN_IN
; FB OUT___IST_EN_OUT:B
; FB END
; FB BLK END
; 2 実行中No書込み
33    LDI     L4  ; #4SB初期ﾊﾟﾗﾒｰﾀ書込み(0:書込/1:-)
      SET     D2131.0
      SET     D2231.0
      SET     D2331.0
      SET     D2431.0
; 3 実行中No書込み後待機
51    LDI     L4  ; #4SB初期ﾊﾟﾗﾒｰﾀ書込み(0:書込/1:-)
      OR      M14  ; #4SB_初期化ｷｰ保持(PID書込用)
      ANI     T4  ; #4SB PID書込みT
      OUT     M14  ; #4SB_初期化ｷｰ保持(PID書込用)
      OUT     T4 K10  ; #4SB PID書込みT
; 4 実行中No以外書込み
71    LDP     T4  ; #4SB PID書込みT
      FMOV    K1 D2124 K7  ; CH1 実行中P_ﾄﾘｶﾞｰ
      FMOV    K1 D2132 K3  ; CH1 実行中SV_ﾄﾘｶﾞｰ
81    LDP     T4  ; #4SB PID書込みT
      FMOV    K1 D2224 K7  ; CH2 実行中P_ﾄﾘｶﾞｰ
      FMOV    K1 D2232 K3  ; CH2 実行中SV_ﾄﾘｶﾞｰ
91    LDP     T4  ; #4SB PID書込みT
      FMOV    K1 D2324 K7  ; CH3 実行中P_ﾄﾘｶﾞｰ
      FMOV    K1 D2332 K3  ; CH3 実行中SV_ﾄﾘｶﾞｰ
101   LDP     T4  ; #4SB PID書込みT
      FMOV    K1 D2424 K7  ; CH4 実行中P_ﾄﾘｶﾞｰ
      FMOV    K1 D2432 K3  ; CH4 実行中SV_ﾄﾘｶﾞｰ
; 5 初期化ﾌﾗｸﾞｾｯﾄ
121   LD      SM400  ; 常時ON
      SET     L4  ; #4SB初期ﾊﾟﾗﾒｰﾀ書込み(0:書込/1:-)
123   END
END_PROGRAM

FUNCTION_BLOCK I+ST_3ca76adcf7d949a6
VAR_INPUT
  __IST_EN_IN : BOOL;
END_VAR
VAR_OUTPUT
  __IST_EN_OUT : BOOL;
END_VAR
(* IST HEADER START *)
IF NOT __IST_EN_IN THEN __IST_EN_OUT:=FALSE; RETURN; END_IF;
(* VERSION=1:TYPE=STB *)
(* IST HEADER END *)
D2101:=50;		(*CH1 実行中P*)
D2102:=60;		(*CH1 実行中I*)
D2103:=30;		(*CH1 実行中D*)
D2104:=0;		(*CH1 SV変化率下降*)
D2105:=0;		(*CH1 SV変化率上昇*)
D2106:=0;		(*CH1 プリセットマニュアル*)
D2108:=1;		(*CH1 実行中No*)
D2109:=234;		(*CH1 実行中SV*)
D2110:=30000;	(*CH1 実行中警報値1*)
D2111:=-30000;	(*CH1 実行中警報値2*)
D2201:=50;		(*CH2 実行中P*)
D2202:=60;		(*CH2 実行中I*)
D2203:=30;		(*CH2 実行中D*)
D2204:=0;		(*CH2 SV変化率下降*)
D2205:=0;		(*CH2 SV変化率上昇*)
D2206:=0;		(*CH2 プリセットマニュアル*)
D2208:=1;		(*CH2 実行中No*)
D2209:=234;		(*CH2 実行中SV*)
D2210:=30000;	(*CH2 実行中警報値1*)
D2211:=-30000;	(*CH2 実行中警報値2*)
D2301:=50;		(*CH3 実行中P*)
D2302:=60;		(*CH3 実行中I*)
D2303:=30;		(*CH3 実行中D*)
D2304:=0;		(*CH3 SV変化率下降*)
D2305:=0;		(*CH3 SV変化率上昇*)
D2306:=0;		(*CH3 プリセットマニュアル*)
D2308:=1;		(*CH3 実行中No*)
D2309:=234;		(*CH3 実行中SV*)
D2310:=30000;	(*CH3 実行中警報値1*)
D2311:=-30000;	(*CH3 実行中警報値2*)
D2401:=50;		(*CH4 実行中P*)
D2402:=60;		(*CH4 実行中I*)
D2403:=30;		(*CH4 実行中D*)
D2404:=0;		(*CH4 SV変化率下降*)
D2405:=0;		(*CH4 SV変化率上昇*)
D2406:=0;		(*CH4 プリセットマニュアル*)
D2408:=1;		(*CH4 実行中No*)
D2409:=234;		(*CH4 実行中SV*)
D2410:=30000;	(*CH4 実行中警報値1*)
D2411:=-30000;(*CH4 実行中警報値2*)
END_FUNCTION_BLOCK

PROGRAM 05_#5  // SB_Initial
VAR
  __IST_225c880c1e454953 : I+ST_225c880c1e454953;
END_VAR
; FB BLK START I+ST_225c880c1e454953(__IST_225c880c1e454953)
; 1 SB初期化ﾊﾟﾗﾒｰﾀ設定
13    LDI     L5  ; #5SB初期ﾊﾟﾗﾒｰﾀ書込み(0:書込/1:-)
      OUT     ___IST_EN_IN
; FB START
; FB_NAME I+ST_225c880c1e454953
; INSTANCE_NAME __IST_225c880c1e454953
; FB IN_B:__IST_EN_IN
; FB OUT___IST_EN_OUT:B
; FB END
; FB BLK END
; 2 実行中No書込み
33    LDI     L5  ; #5SB初期ﾊﾟﾗﾒｰﾀ書込み(0:書込/1:-)
      SET     D2631.0
      SET     D2731.0
      SET     D2831.0
      SET     D2931.0
; 3 実行中No書込み後待機
51    LDI     L5  ; #5SB初期ﾊﾟﾗﾒｰﾀ書込み(0:書込/1:-)
      OR      M15  ; #5SB_初期化ｷｰ保持(PID書込用)
      ANI     T5  ; #5SB PID書込みT
      OUT     M15  ; #5SB_初期化ｷｰ保持(PID書込用)
      OUT     T5 K10  ; #5SB PID書込みT
; 4 実行中No以外書込み
71    LDP     T5  ; #5SB PID書込みT
      FMOV    K1 D2624 K7  ; CH1 実行中P_ﾄﾘｶﾞｰ
      FMOV    K1 D2632 K3  ; CH1 実行中SV_ﾄﾘｶﾞｰ
81    LDP     T5  ; #5SB PID書込みT
      FMOV    K1 D2724 K7  ; CH2 実行中P_ﾄﾘｶﾞｰ
      FMOV    K1 D2732 K3  ; CH2 実行中SV_ﾄﾘｶﾞｰ
91    LDP     T5  ; #5SB PID書込みT
      FMOV    K1 D2824 K7  ; CH3 実行中P_ﾄﾘｶﾞｰ
      FMOV    K1 D2832 K3  ; CH3 実行中SV_ﾄﾘｶﾞｰ
101   LDP     T5  ; #5SB PID書込みT
      FMOV    K1 D2924 K7  ; CH4 実行中P_ﾄﾘｶﾞｰ
      FMOV    K1 D2932 K3  ; CH4 実行中SV_ﾄﾘｶﾞｰ
; 5 初期化ﾌﾗｸﾞｾｯﾄ
121   LD      SM400  ; 常時ON
      SET     L5  ; #5SB初期ﾊﾟﾗﾒｰﾀ書込み(0:書込/1:-)
123   END
END_PROGRAM

FUNCTION_BLOCK I+ST_225c880c1e454953
VAR_INPUT
  __IST_EN_IN : BOOL;
END_VAR
VAR_OUTPUT
  __IST_EN_OUT : BOOL;
END_VAR
(* IST HEADER START *)
IF NOT __IST_EN_IN THEN __IST_EN_OUT:=FALSE; RETURN; END_IF;
(* VERSION=1:TYPE=STB *)
(* IST HEADER END *)
D2601:=50;		(*CH1 実行中P*)
D2602:=60;		(*CH1 実行中I*)
D2603:=30;		(*CH1 実行中D*)
D2604:=0;		(*CH1 SV変化率下降*)
D2605:=0;		(*CH1 SV変化率上昇*)
D2606:=0;		(*CH1 プリセットマニュアル*)
D2608:=1;		(*CH1 実行中No*)
D2609:=234;		(*CH1 実行中SV*)
D2610:=30000;	(*CH1 実行中警報値1*)
D2611:=-30000;	(*CH1 実行中警報値2*)
D2701:=50;		(*CH2 実行中P*)
D2702:=60;		(*CH2 実行中I*)
D2703:=30;		(*CH2 実行中D*)
D2704:=0;		(*CH2 SV変化率下降*)
D2705:=0;		(*CH2 SV変化率上昇*)
D2706:=0;		(*CH2 プリセットマニュアル*)
D2708:=1;		(*CH2 実行中No*)
D2709:=234;		(*CH2 実行中SV*)
D2710:=30000;	(*CH2 実行中警報値1*)
D2711:=-30000;	(*CH2 実行中警報値2*)
D2801:=50;		(*CH3 実行中P*)
D2802:=60;		(*CH3 実行中I*)
D2803:=30;		(*CH3 実行中D*)
D2804:=0;		(*CH3 SV変化率下降*)
D2805:=0;		(*CH3 SV変化率上昇*)
D2806:=0;		(*CH3 プリセットマニュアル*)
D2808:=1;		(*CH3 実行中No*)
D2809:=234;		(*CH3 実行中SV*)
D2810:=30000;	(*CH3 実行中警報値1*)
D2811:=-30000;	(*CH3 実行中警報値2*)
D2901:=50;		(*CH4 実行中P*)
D2902:=60;		(*CH4 実行中I*)
D2903:=30;		(*CH4 実行中D*)
D2904:=0;		(*CH4 SV変化率下降*)
D2905:=0;		(*CH4 SV変化率上昇*)
D2906:=0;		(*CH4 プリセットマニュアル*)
D2908:=1;		(*CH4 実行中No*)
D2909:=234;		(*CH4 実行中SV*)
D2910:=30000;	(*CH4 実行中警報値1*)
D2911:=-30000;(*CH4 実行中警報値2*)
END_FUNCTION_BLOCK

PROGRAM 06_#6  // SB_Initial
VAR
  __IST_951498d1b4df4eeb : I+ST_951498d1b4df4eeb;
END_VAR
; FB BLK START I+ST_951498d1b4df4eeb(__IST_951498d1b4df4eeb)
; 1 SB初期化ﾊﾟﾗﾒｰﾀ設定
13    LDI     L6  ; #6SB初期ﾊﾟﾗﾒｰﾀ書込み(0:書込/1:-)
      OUT     ___IST_EN_IN
; FB START
; FB_NAME I+ST_951498d1b4df4eeb
; INSTANCE_NAME __IST_951498d1b4df4eeb
; FB IN_B:__IST_EN_IN
; FB OUT___IST_EN_OUT:B
; FB END
; FB BLK END
; 2 実行中No書込み
33    LDI     L6  ; #6SB初期ﾊﾟﾗﾒｰﾀ書込み(0:書込/1:-)
      SET     D3131.0
      SET     D3231.0
      SET     D3331.0
      SET     D3431.0
; 3 実行中No書込み後待機
51    LDI     L6  ; #6SB初期ﾊﾟﾗﾒｰﾀ書込み(0:書込/1:-)
      OR      M16  ; #6SB_初期化ｷｰ保持(PID書込用)
      ANI     T6  ; #6SB PID書込みT
      OUT     M16  ; #6SB_初期化ｷｰ保持(PID書込用)
      OUT     T6 K10  ; #6SB PID書込みT
; 4 実行中No以外書込み
71    LDP     T6  ; #6SB PID書込みT
      FMOV    K1 D3124 K7  ; CH1 実行中P_ﾄﾘｶﾞｰ
      FMOV    K1 D3132 K3  ; CH1 実行中SV_ﾄﾘｶﾞｰ
81    LDP     T6  ; #6SB PID書込みT
      FMOV    K1 D3224 K7  ; CH2 実行中P_ﾄﾘｶﾞｰ
      FMOV    K1 D3232 K3  ; CH2 実行中SV_ﾄﾘｶﾞｰ
91    LDP     T6  ; #6SB PID書込みT
      FMOV    K1 D3324 K7  ; CH3 実行中P_ﾄﾘｶﾞｰ
      FMOV    K1 D3332 K3  ; CH3 実行中SV_ﾄﾘｶﾞｰ
101   LDP     T6  ; #6SB PID書込みT
      FMOV    K1 D3424 K7  ; CH4 実行中P_ﾄﾘｶﾞｰ
      FMOV    K1 D3432 K3  ; CH4 実行中SV_ﾄﾘｶﾞｰ
; 5 初期化ﾌﾗｸﾞｾｯﾄ
121   LD      SM400  ; 常時ON
      SET     L6  ; #6SB初期ﾊﾟﾗﾒｰﾀ書込み(0:書込/1:-)
123   END
END_PROGRAM

FUNCTION_BLOCK I+ST_951498d1b4df4eeb
VAR_INPUT
  __IST_EN_IN : BOOL;
END_VAR
VAR_OUTPUT
  __IST_EN_OUT : BOOL;
END_VAR
(* IST HEADER START *)
IF NOT __IST_EN_IN THEN __IST_EN_OUT:=FALSE; RETURN; END_IF;
(* VERSION=1:TYPE=STB *)
(* IST HEADER END *)
D3101:=50;		(*CH1 実行中P*)
D3102:=60;		(*CH1 実行中I*)
D3103:=30;		(*CH1 実行中D*)
D3104:=0;		(*CH1 SV変化率下降*)
D3105:=0;		(*CH1 SV変化率上昇*)
D3106:=0;		(*CH1 プリセットマニュアル*)
D3108:=1;		(*CH1 実行中No*)
D3109:=234;		(*CH1 実行中SV*)
D3110:=30000;	(*CH1 実行中警報値1*)
D3111:=-30000;	(*CH1 実行中警報値2*)
D3201:=50;		(*CH2 実行中P*)
D3202:=60;		(*CH2 実行中I*)
D3203:=30;		(*CH2 実行中D*)
D3204:=0;		(*CH2 SV変化率下降*)
D3205:=0;		(*CH2 SV変化率上昇*)
D3206:=0;		(*CH2 プリセットマニュアル*)
D3208:=1;		(*CH2 実行中No*)
D3209:=234;		(*CH2 実行中SV*)
D3210:=30000;	(*CH2 実行中警報値1*)
D3211:=-30000;	(*CH2 実行中警報値2*)
D3301:=50;		(*CH3 実行中P*)
D3302:=60;		(*CH3 実行中I*)
D3303:=30;		(*CH3 実行中D*)
D3304:=0;		(*CH3 SV変化率下降*)
D3305:=0;		(*CH3 SV変化率上昇*)
D3306:=0;		(*CH3 プリセットマニュアル*)
D3308:=1;		(*CH3 実行中No*)
D3309:=234;		(*CH3 実行中SV*)
D3310:=30000;	(*CH3 実行中警報値1*)
D3311:=-30000;	(*CH3 実行中警報値2*)
D3401:=50;		(*CH4 実行中P*)
D3402:=60;		(*CH4 実行中I*)
D3403:=30;		(*CH4 実行中D*)
D3404:=0;		(*CH4 SV変化率下降*)
D3405:=0;		(*CH4 SV変化率上昇*)
D3406:=0;		(*CH4 プリセットマニュアル*)
D3408:=1;		(*CH4 実行中No*)
D3409:=234;		(*CH4 実行中SV*)
D3410:=30000;	(*CH4 実行中警報値1*)
D3411:=-30000;(*CH4 実行中警報値2*)
END_FUNCTION_BLOCK

PROGRAM 07_#7  // SB_Initial
VAR
  __IST_84f445d1093e4a9b : I+ST_84f445d1093e4a9b;
END_VAR
; FB BLK START I+ST_84f445d1093e4a9b(__IST_84f445d1093e4a9b)
; 1 SB初期化ﾊﾟﾗﾒｰﾀ設定
13    LDI     L7  ; #7SB初期ﾊﾟﾗﾒｰﾀ書込み(0:書込/1:-)
      OUT     ___IST_EN_IN
; FB START
; FB_NAME I+ST_84f445d1093e4a9b
; INSTANCE_NAME __IST_84f445d1093e4a9b
; FB IN_B:__IST_EN_IN
; FB OUT___IST_EN_OUT:B
; FB END
; FB BLK END
; 2 実行中No書込み
33    LDI     L7  ; #7SB初期ﾊﾟﾗﾒｰﾀ書込み(0:書込/1:-)
      SET     D3631.0
      SET     D3731.0
      SET     D3831.0
      SET     D3931.0
; 3 実行中No書込み後待機
51    LDI     L7  ; #7SB初期ﾊﾟﾗﾒｰﾀ書込み(0:書込/1:-)
      OR      M17  ; #7SB_初期化ｷｰ保持(PID書込用)
      ANI     T7  ; #7SB PID書込みT
      OUT     M17  ; #7SB_初期化ｷｰ保持(PID書込用)
      OUT     T7 K10  ; #7SB PID書込みT
; 4 実行中No以外書込み
71    LDP     T7  ; #7SB PID書込みT
      FMOV    K1 D3624 K7  ; CH1 実行中P_ﾄﾘｶﾞｰ
      FMOV    K1 D3632 K3  ; CH1 実行中SV_ﾄﾘｶﾞｰ
81    LDP     T7  ; #7SB PID書込みT
      FMOV    K1 D3724 K7  ; CH2 実行中P_ﾄﾘｶﾞｰ
      FMOV    K1 D3732 K3  ; CH2 実行中SV_ﾄﾘｶﾞｰ
91    LDP     T7  ; #7SB PID書込みT
      FMOV    K1 D3824 K7  ; CH3 実行中P_ﾄﾘｶﾞｰ
      FMOV    K1 D3832 K3  ; CH3 実行中SV_ﾄﾘｶﾞｰ
101   LDP     T7  ; #7SB PID書込みT
      FMOV    K1 D3924 K7  ; CH4 実行中P_ﾄﾘｶﾞｰ
      FMOV    K1 D3932 K3  ; CH4 実行中SV_ﾄﾘｶﾞｰ
; 5 初期化ﾌﾗｸﾞｾｯﾄ
121   LD      SM400  ; 常時ON
      SET     L7  ; #7SB初期ﾊﾟﾗﾒｰﾀ書込み(0:書込/1:-)
123   END
END_PROGRAM

FUNCTION_BLOCK I+ST_84f445d1093e4a9b
VAR_INPUT
  __IST_EN_IN : BOOL;
END_VAR
VAR_OUTPUT
  __IST_EN_OUT : BOOL;
END_VAR
(* IST HEADER START *)
IF NOT __IST_EN_IN THEN __IST_EN_OUT:=FALSE; RETURN; END_IF;
(* VERSION=1:TYPE=STB *)
(* IST HEADER END *)
D3601:=50;		(*CH1 実行中P*)
D3602:=60;		(*CH1 実行中I*)
D3603:=30;		(*CH1 実行中D*)
D3604:=0;		(*CH1 SV変化率下降*)
D3605:=0;		(*CH1 SV変化率上昇*)
D3606:=0;		(*CH1 プリセットマニュアル*)
D3608:=1;		(*CH1 実行中No*)
D3609:=234;		(*CH1 実行中SV*)
D3610:=30000;	(*CH1 実行中警報値1*)
D3611:=-30000;	(*CH1 実行中警報値2*)
D3701:=50;		(*CH2 実行中P*)
D3702:=60;		(*CH2 実行中I*)
D3703:=30;		(*CH2 実行中D*)
D3704:=0;		(*CH2 SV変化率下降*)
D3705:=0;		(*CH2 SV変化率上昇*)
D3706:=0;		(*CH2 プリセットマニュアル*)
D3708:=1;		(*CH2 実行中No*)
D3709:=234;		(*CH2 実行中SV*)
D3710:=30000;	(*CH2 実行中警報値1*)
D3711:=-30000;	(*CH2 実行中警報値2*)
D3801:=50;		(*CH3 実行中P*)
D3802:=60;		(*CH3 実行中I*)
D3803:=30;		(*CH3 実行中D*)
D3804:=0;		(*CH3 SV変化率下降*)
D3805:=0;		(*CH3 SV変化率上昇*)
D3806:=0;		(*CH3 プリセットマニュアル*)
D3808:=1;		(*CH3 実行中No*)
D3809:=234;		(*CH3 実行中SV*)
D3810:=30000;	(*CH3 実行中警報値1*)
D3811:=-30000;	(*CH3 実行中警報値2*)
D3901:=50;		(*CH4 実行中P*)
D3902:=60;		(*CH4 実行中I*)
D3903:=30;		(*CH4 実行中D*)
D3904:=0;		(*CH4 SV変化率下降*)
D3905:=0;		(*CH4 SV変化率上昇*)
D3906:=0;		(*CH4 プリセットマニュアル*)
D3908:=1;		(*CH4 実行中No*)
D3909:=234;		(*CH4 実行中SV*)
D3910:=30000;	(*CH4 実行中警報値1*)
D3911:=-30000;(*CH4 実行中警報値2*)
END_FUNCTION_BLOCK

PROGRAM 08_#8  // SB_Initial
VAR
  __IST_742c54a88d7049b7 : I+ST_742c54a88d7049b7;
END_VAR
; FB BLK START I+ST_742c54a88d7049b7(__IST_742c54a88d7049b7)
; 1 SB初期化ﾊﾟﾗﾒｰﾀ設定
13    LDI     L8  ; #8SB初期ﾊﾟﾗﾒｰﾀ書込み(0:書込/1:-)
      OUT     ___IST_EN_IN
; FB START
; FB_NAME I+ST_742c54a88d7049b7
; INSTANCE_NAME __IST_742c54a88d7049b7
; FB IN_B:__IST_EN_IN
; FB OUT___IST_EN_OUT:B
; FB END
; FB BLK END
; 2 実行中No書込み
33    LDI     L8  ; #8SB初期ﾊﾟﾗﾒｰﾀ書込み(0:書込/1:-)
      SET     D4131.0
      SET     D4231.0
      SET     D4331.0
      SET     D4431.0
; 3 実行中No書込み後待機
51    LDI     L8  ; #8SB初期ﾊﾟﾗﾒｰﾀ書込み(0:書込/1:-)
      OR      M18  ; #8SB_初期化ｷｰ保持(PID書込用)
      ANI     T8  ; #8SB PID書込みT
      OUT     M18  ; #8SB_初期化ｷｰ保持(PID書込用)
      OUT     T8 K10  ; #8SB PID書込みT
; 4 実行中No以外書込み
71    LDP     T8  ; #8SB PID書込みT
      FMOV    K1 D4124 K7  ; CH1 実行中P_ﾄﾘｶﾞｰ
      FMOV    K1 D4132 K3  ; CH1 実行中SV_ﾄﾘｶﾞｰ
81    LDP     T8  ; #8SB PID書込みT
      FMOV    K1 D4224 K7  ; CH2 実行中P_ﾄﾘｶﾞｰ
      FMOV    K1 D4232 K3  ; CH2 実行中SV_ﾄﾘｶﾞｰ
91    LDP     T8  ; #8SB PID書込みT
      FMOV    K1 D4324 K7  ; CH3 実行中P_ﾄﾘｶﾞｰ
      FMOV    K1 D4332 K3  ; CH3 実行中SV_ﾄﾘｶﾞｰ
101   LDP     T8  ; #8SB PID書込みT
      FMOV    K1 D4424 K7  ; CH4 実行中P_ﾄﾘｶﾞｰ
      FMOV    K1 D4432 K3  ; CH4 実行中SV_ﾄﾘｶﾞｰ
; 5 初期化ﾌﾗｸﾞｾｯﾄ
121   LD      SM400  ; 常時ON
      SET     L8  ; #8SB初期ﾊﾟﾗﾒｰﾀ書込み(0:書込/1:-)
123   END
END_PROGRAM

FUNCTION_BLOCK I+ST_742c54a88d7049b7
VAR_INPUT
  __IST_EN_IN : BOOL;
END_VAR
VAR_OUTPUT
  __IST_EN_OUT : BOOL;
END_VAR
(* IST HEADER START *)
IF NOT __IST_EN_IN THEN __IST_EN_OUT:=FALSE; RETURN; END_IF;
(* VERSION=1:TYPE=STB *)
(* IST HEADER END *)
D4101:=50;		(*CH1 実行中P*)
D4102:=60;		(*CH1 実行中I*)
D4103:=30;		(*CH1 実行中D*)
D4104:=0;		(*CH1 SV変化率下降*)
D4105:=0;		(*CH1 SV変化率上昇*)
D4106:=0;		(*CH1 プリセットマニュアル*)
D4108:=1;		(*CH1 実行中No*)
D4109:=234;		(*CH1 実行中SV*)
D4110:=30000;	(*CH1 実行中警報値1*)
D4111:=-30000;	(*CH1 実行中警報値2*)
D4201:=50;		(*CH2 実行中P*)
D4202:=60;		(*CH2 実行中I*)
D4203:=30;		(*CH2 実行中D*)
D4204:=0;		(*CH2 SV変化率下降*)
D4205:=0;		(*CH2 SV変化率上昇*)
D4206:=0;		(*CH2 プリセットマニュアル*)
D4208:=1;		(*CH2 実行中No*)
D4209:=234;		(*CH2 実行中SV*)
D4210:=30000;	(*CH2 実行中警報値1*)
D4211:=-30000;	(*CH2 実行中警報値2*)
D4301:=50;		(*CH3 実行中P*)
D4302:=60;		(*CH3 実行中I*)
D4303:=30;		(*CH3 実行中D*)
D4304:=0;		(*CH3 SV変化率下降*)
D4305:=0;		(*CH3 SV変化率上昇*)
D4306:=0;		(*CH3 プリセットマニュアル*)
D4308:=1;		(*CH3 実行中No*)
D4309:=234;		(*CH3 実行中SV*)
D4310:=30000;	(*CH3 実行中警報値1*)
D4311:=-30000;	(*CH3 実行中警報値2*)
D4401:=50;		(*CH4 実行中P*)
D4402:=60;		(*CH4 実行中I*)
D4403:=30;		(*CH4 実行中D*)
D4404:=0;		(*CH4 SV変化率下降*)
D4405:=0;		(*CH4 SV変化率上昇*)
D4406:=0;		(*CH4 プリセットマニュアル*)
D4408:=1;		(*CH4 実行中No*)
D4409:=234;		(*CH4 実行中SV*)
D4410:=30000;	(*CH4 実行中警報値1*)
D4411:=-30000;(*CH4 実行中警報値2*)
END_FUNCTION_BLOCK

PROGRAM 09_#9  // SB_Initial
VAR
  __IST_79e0117e5b4a4603 : I+ST_79e0117e5b4a4603;
END_VAR
; FB BLK START I+ST_79e0117e5b4a4603(__IST_79e0117e5b4a4603)
; 1 SB初期化ﾊﾟﾗﾒｰﾀ設定
13    LDI     L9  ; #9SB初期ﾊﾟﾗﾒｰﾀ書込み(0:書込/1:-)
      OUT     ___IST_EN_IN
; FB START
; FB_NAME I+ST_79e0117e5b4a4603
; INSTANCE_NAME __IST_79e0117e5b4a4603
; FB IN_B:__IST_EN_IN
; FB OUT___IST_EN_OUT:B
; FB END
; FB BLK END
; 2 実行中No書込み
33    LDI     L9  ; #9SB初期ﾊﾟﾗﾒｰﾀ書込み(0:書込/1:-)
      SET     D4631.0
      SET     D4731.0
      SET     D4831.0
      SET     D4931.0
; 3 実行中No書込み後待機
51    LDI     L9  ; #9SB初期ﾊﾟﾗﾒｰﾀ書込み(0:書込/1:-)
      OR      M19  ; #9SB_初期化ｷｰ保持(PID書込用)
      ANI     T9  ; #9SB PID書込みT
      OUT     M19  ; #9SB_初期化ｷｰ保持(PID書込用)
      OUT     T9 K10  ; #9SB PID書込みT
; 4 実行中No以外書込み
71    LDP     T9  ; #9SB PID書込みT
      FMOV    K1 D4624 K7  ; CH1 実行中P_ﾄﾘｶﾞｰ
      FMOV    K1 D4632 K3  ; CH1 実行中SV_ﾄﾘｶﾞｰ
81    LDP     T9  ; #9SB PID書込みT
      FMOV    K1 D4724 K7  ; CH2 実行中P_ﾄﾘｶﾞｰ
      FMOV    K1 D4732 K3  ; CH2 実行中SV_ﾄﾘｶﾞｰ
91    LDP     T9  ; #9SB PID書込みT
      FMOV    K1 D4824 K7  ; CH3 実行中P_ﾄﾘｶﾞｰ
      FMOV    K1 D4832 K3  ; CH3 実行中SV_ﾄﾘｶﾞｰ
101   LDP     T9  ; #9SB PID書込みT
      FMOV    K1 D4924 K7  ; CH4 実行中P_ﾄﾘｶﾞｰ
      FMOV    K1 D4932 K3  ; CH4 実行中SV_ﾄﾘｶﾞｰ
; 5 初期化ﾌﾗｸﾞｾｯﾄ
121   LD      SM400  ; 常時ON
      SET     L9  ; #9SB初期ﾊﾟﾗﾒｰﾀ書込み(0:書込/1:-)
123   END
END_PROGRAM

FUNCTION_BLOCK I+ST_79e0117e5b4a4603
VAR_INPUT
  __IST_EN_IN : BOOL;
END_VAR
VAR_OUTPUT
  __IST_EN_OUT : BOOL;
END_VAR
(* IST HEADER START *)
IF NOT __IST_EN_IN THEN __IST_EN_OUT:=FALSE; RETURN; END_IF;
(* VERSION=1:TYPE=STB *)
(* IST HEADER END *)
D4601:=50;		(*CH1 実行中P*)
D4602:=60;		(*CH1 実行中I*)
D4603:=30;		(*CH1 実行中D*)
D4604:=0;		(*CH1 SV変化率下降*)
D4605:=0;		(*CH1 SV変化率上昇*)
D4606:=0;		(*CH1 プリセットマニュアル*)
D4608:=1;		(*CH1 実行中No*)
D4609:=234;		(*CH1 実行中SV*)
D4610:=30000;	(*CH1 実行中警報値1*)
D4611:=-30000;	(*CH1 実行中警報値2*)
D4701:=50;		(*CH2 実行中P*)
D4702:=60;		(*CH2 実行中I*)
D4703:=30;		(*CH2 実行中D*)
D4704:=0;		(*CH2 SV変化率下降*)
D4705:=0;		(*CH2 SV変化率上昇*)
D4706:=0;		(*CH2 プリセットマニュアル*)
D4708:=1;		(*CH2 実行中No*)
D4709:=234;		(*CH2 実行中SV*)
D4710:=30000;	(*CH2 実行中警報値1*)
D4711:=-30000;	(*CH2 実行中警報値2*)
D4801:=50;		(*CH3 実行中P*)
D4802:=60;		(*CH3 実行中I*)
D4803:=30;		(*CH3 実行中D*)
D4804:=0;		(*CH3 SV変化率下降*)
D4805:=0;		(*CH3 SV変化率上昇*)
D4806:=0;		(*CH3 プリセットマニュアル*)
D4808:=1;		(*CH3 実行中No*)
D4809:=234;		(*CH3 実行中SV*)
D4810:=30000;	(*CH3 実行中警報値1*)
D4811:=-30000;	(*CH3 実行中警報値2*)
D4901:=50;		(*CH4 実行中P*)
D4902:=60;		(*CH4 実行中I*)
D4903:=30;		(*CH4 実行中D*)
D4904:=0;		(*CH4 SV変化率下降*)
D4905:=0;		(*CH4 SV変化率上昇*)
D4906:=0;		(*CH4 プリセットマニュアル*)
D4908:=1;		(*CH4 実行中No*)
D4909:=234;		(*CH4 実行中SV*)
D4910:=30000;	(*CH4 実行中警報値1*)
D4911:=-30000;(*CH4 実行中警報値2*)
END_FUNCTION_BLOCK

// device comments not shown above
D71  ; GOTﾍﾞｰｽ画面
D72  ; GOTｵｰﾊﾞｰﾗｯﾌﾟｳｨﾝﾄﾞｳ
D73  ; GOTｽｰﾊﾟｰｲﾝﾎﾟｰｽﾞｳｨﾝﾄﾞｳ
D80  ; GOTｼｽﾃﾑ信号1-1
D81  ; GOTｼｽﾃﾑ信号2-1
D82  ; GOT数値入力番号
D83  ; GOT数値入力変更前値(32ﾋﾞｯﾄ)
D84  ; GOT数値入力変更前値(32ﾋﾞｯﾄ)
D85  ; GOT数値入力変更後値(32ﾋﾞｯﾄ)
D86  ; GOT数値入力変更後値(32ﾋﾞｯﾄ)
D87  ; GOTｴﾗｰｺｰﾄﾞ
D88  ; GOTｴﾗｰｺｰﾄﾞ2
D89  ; GOT印字中ﾚﾎﾟｰﾄ画面番号
D90  ; GOT表示中ﾍﾞｰｽ画面番号
D91  ; GOT表示中ｳｨﾝﾄﾞｳ1画面番号
D92  ; GOT現在ｶｰｿﾙ表示ｵﾌﾞｼﾞｪｸﾄID
D93  ; GOT前回ｶｰｿﾙ表示ｵﾌﾞｼﾞｪｸﾄID
D94  ; GOT現在ｶｰｿﾙ表示ﾕｰｻﾞID
D95  ; GOT前回ｶｰｿﾙ表示ﾕｰｻﾞID
D96  ; GOT入力ｷｰｺｰﾄﾞ
D97  ; GOT外部入出力機能･入力情報1
D98  ; GOT外部入出力機能･入力情報2
D103  ; SBｼｽﾃﾑｴﾗｰ失敗ﾃﾞﾊﾞｲｽ
D104  ; SBｼｽﾃﾑｴﾗｰｴﾗｰﾃﾞﾊﾞｲｽ
D80.0  ; GOT自動ｽｸﾘｰﾝｾｰﾌﾞ無効信号
D80.1  ; GOT強制ｽｸﾘｰﾝｾｰﾌﾞ番号
D80.2  ; GOT強制ｽｸﾘｰﾝｾｰﾌﾞﾀｯﾁ解除信号
D80.3  ; GOT入力ｷｰ読出し完了信号
D80.4  ; GOT数値入力読出し完了信号
D80.5  ; GOTﾊﾞｰｺｰﾄﾞ入力無効信号(CH8)
D80.6  ; GOT外部機器入出力完了信号(CH8)
D80.7  ; GOT使用禁止
D80.8  ; GOTﾌﾞｻﾞｰｽﾘｰｼｮｯﾄ出力信号
D80.9  ; GOTﾀｯﾁ操作無効信号
D80.A  ; GOTﾊｰﾄﾞｺﾋﾟｰ設定有効信号
D80.B  ; GOT使用禁止
D80.C  ; GOTﾊｰﾄﾞｺﾋﾟｰ白黒反転信号
D80.D  ; GOTｴﾗｰﾘｾｯﾄ信号
D80.F  ; GOTﾌﾞｻﾞｰﾜﾝｼｮｯﾄ出力信号
